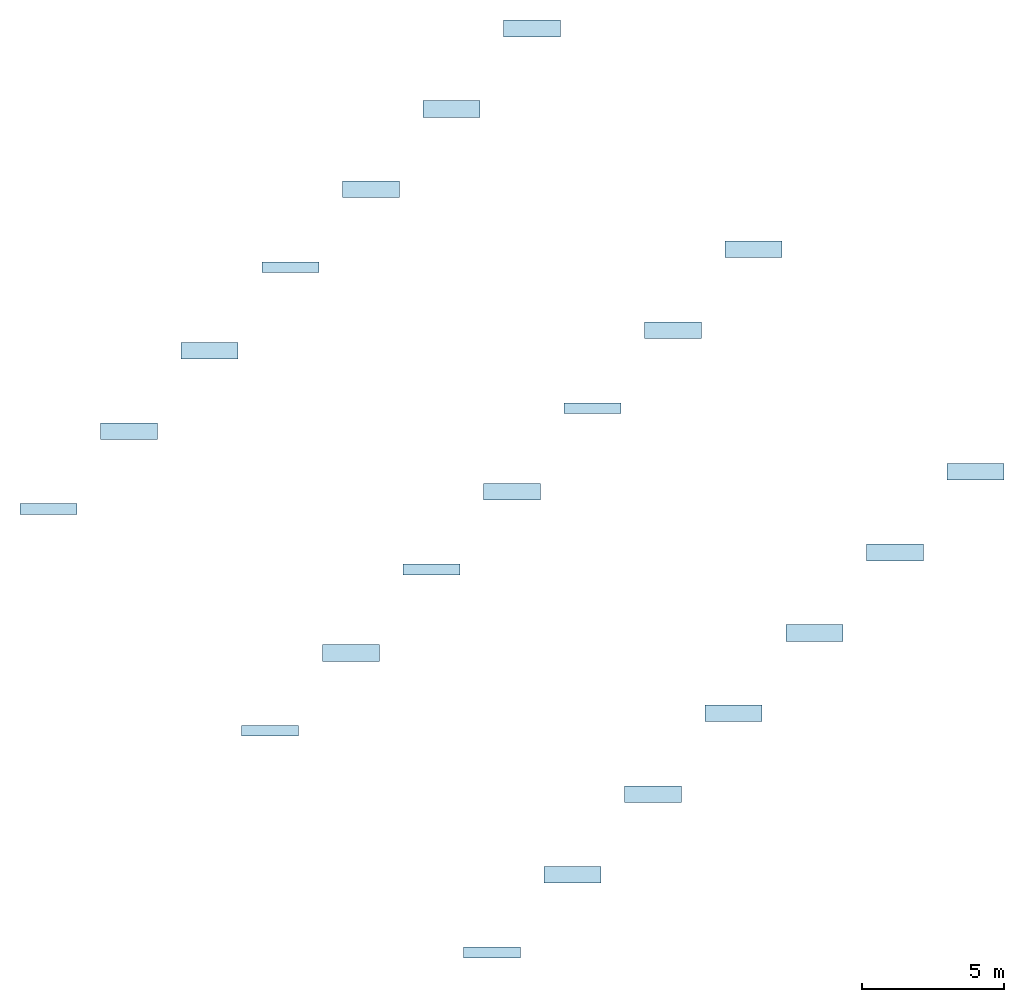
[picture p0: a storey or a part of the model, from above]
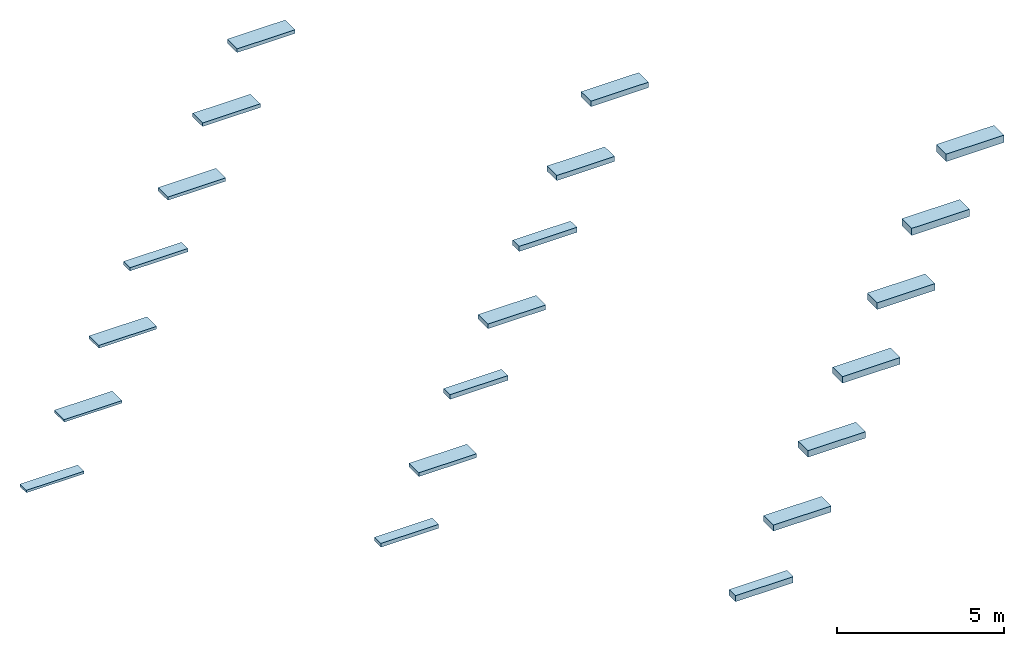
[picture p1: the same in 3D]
Properties of the parts of a building model (IFC2X3), part 1 of 3

# File
Description: ViewDefinition [CoordinationView]
Time: 2023-01-18T10:33:08
Written by: The EXPRESS Data Manager Version 5.02.0100.07 : 28 Aug 2013
Made in: 21.1.70.21 - Exporter 21.1.70.21 - Alternate UI 21.1.70.21
Comment: STEP Physical File produced by: The EXPRESS Data Manager Version 5.02.0100.07 : 28 Aug 2013 * Module: EDMstepFileFactory/EDMstandAlone * Creation date: Wed Jan 18 10:33:08 2023 * Host: BIM-LT03 * Database: C:\Users\DONNEE~1\AppData\Local\Temp\6dfd9f73-01cb-4fe2-bb7c-203e315a706e\b24bc6bb-a7e8-40af-8c49-64323bfd44da\ifc * Database version: 5507 * Database creation date: Wed Jan 18 10:33:06 2023 * Schema: IFC2X3 * Model: DataRepository.ifc * Model creation date: Wed Jan 18 10:33:06 2023 * Header model: DataRepository.ifc_HeaderModel * Header model creation date: Wed Jan 18 10:33:06 2023 * EDMuser: sdai-user * EDMgroup: sdai-group * License ID and type: 5605 : Permanent license. Expiry date: * EDMstepFileFactory options: 020000

# IfcSite, Default
RefLatitude: 42, 24, 53, 508911; RefLongitude: -71, -15, -29, -58837; RefElevation: 0 mm
Pset_ProductRequirements - Category: Project Information

# IfcBuilding
Pset_BuildingCommon - NumberOfStoreys: 2
Pset_ProductRequirements - Category: Project Information

# IfcBuildingStorey: Level:NL_00_niveau (2)
Pset_ProductRequirements - Category: Levels
Name | LongName = Pset_AirSideSystemInformation, Name = Pset_ProductRequirements, Name | Elevation (mm)
Begane grond | Begane grond | 0
Lengte | Lengte | 2500

# IfcRoof: Basic Roof:NLRS_27_RO_Naturoll 035_100x580x7400mm, Basic Roof:NLRS_27_RO_Naturoll 035_100x580x7400mm:35001
In: Lengte
Classification: 27 Daken (Uniformat)
Pset_ElementShading - Roughness: 304.8 mm
Pset_ManufacturerTypeInformation - Manufacturer: Knauf Insulation B.V.
Pset_ProductRequirements - Category: Roofs
Pset_QuantityTakeOff - Reference: Basic Roof:NLRS_27_RO_Naturoll 035_100x580x7400mm
Pset_RoofCommon - IsExternal: yes; Reference: Basic Roof:NLRS_27_RO_Naturoll 035_100x580x7400mm; ProjectedArea: 1.16 m2; TotalArea: 1.16 m2
Pset_Roof Schedule Naturoll 035 LOD400 - rollen / pak: 2; Type: Basic Roof: NLRS_27_RO_Naturoll 035_100x580x7400mm; Assembly Code: 27; Type Image: Raster image: Naturoll 035 .jpg (2); Model: Naturoll 035 is een onbeklede glaswoldeken met ECOSE® Technology; Manufacturer: Knauf Insulation B.V.; URL: www.knaufinsulation.nl; Description: Naturoll 035 - 100mm; phone: +31(0)162-421245; email: customerservice.nl@knaufinsulation.com; product URL: https://www.knaufinsulation.nl/producten-van-knauf-insulation/naturoll-035; warmteweerstand: 2.85; NLRS_C_Code_Brandklasse: A1; warmtegeleidingscoëfficiënt: 0.035; kortstondige waterabsorptie: WS; langdurige waterabsorptie: WL(P); waterdamptransmissie / waterdampdiffusie weerstandsfactor: MU1; luchtstroomweerstand: Afr5; DoP nummer (Declaration of performance): G4220LPCPR; NLRS_C_content_creator: Knauf Insulation; NLRS_C_content_versie: V1.0; diktebereik: 20 - 370; diktetolerantie: T2; pak (m2): 8.58; pakken / pallet: 24; pallet (m2): 206.02

# IfcRoof: Basic Roof:NLRS_27_RO_Naturoll 035_120x380x6200mm, Basic Roof:NLRS_27_RO_Naturoll 035_120x380x6200mm:35023
In: Lengte
Classification: 27 Daken (Uniformat)
Pset_ElementShading - Roughness: 304.8 mm
Pset_ManufacturerTypeInformation - Manufacturer: Knauf Insulation B.V.
Pset_ProductRequirements - Category: Roofs
Pset_QuantityTakeOff - Reference: Basic Roof:NLRS_27_RO_Naturoll 035_120x380x6200mm
Pset_RoofCommon - IsExternal: yes; Reference: Basic Roof:NLRS_27_RO_Naturoll 035_120x380x6200mm; ProjectedArea: 0.76 m2; TotalArea: 0.76 m2
Pset_Roof Schedule Naturoll 035 LOD400 - rollen / pak: 3; Type: Basic Roof: NLRS_27_RO_Naturoll 035_120x380x6200mm; Assembly Code: 27; Type Image: Raster image: Naturoll 035 .jpg (2); Model: Naturoll 035 is een onbeklede glaswoldeken met ECOSE® Technology; Manufacturer: Knauf Insulation B.V.; URL: www.knaufinsulation.nl; Description: Naturoll 035 - 120mm; phone: +31(0)162-421245; email: customerservice.nl@knaufinsulation.com; product URL: https://www.knaufinsulation.nl/producten-van-knauf-insulation/naturoll-035; warmteweerstand: 3.4; NLRS_C_Code_Brandklasse: A1; warmtegeleidingscoëfficiënt: 0.035; kortstondige waterabsorptie: WS; langdurige waterabsorptie: WL(P); waterdamptransmissie / waterdampdiffusie weerstandsfactor: MU1; luchtstroomweerstand: Afr5; DoP nummer (Declaration of performance): G4220LPCPR; NLRS_C_content_creator: Knauf Insulation; NLRS_C_content_versie: V1.0; diktebereik: 20 - 370; diktetolerantie: T2; pak (m2): 7.07; pakken / pallet: 24; pallet (m2): 169.63

# IfcRoof: Basic Roof:NLRS_27_RO_Naturoll 035_120x580x6200mm, Basic Roof:NLRS_27_RO_Naturoll 035_120x580x6200mm:35045
In: Lengte
Classification: 27 Daken (Uniformat)
Pset_ElementShading - Roughness: 304.8 mm
Pset_ManufacturerTypeInformation - Manufacturer: Knauf Insulation B.V.
Pset_ProductRequirements - Category: Roofs
Pset_QuantityTakeOff - Reference: Basic Roof:NLRS_27_RO_Naturoll 035_120x580x6200mm
Pset_RoofCommon - IsExternal: yes; Reference: Basic Roof:NLRS_27_RO_Naturoll 035_120x580x6200mm; ProjectedArea: 1.16 m2; TotalArea: 1.16 m2
Pset_Roof Schedule Naturoll 035 LOD400 - rollen / pak: 2; Type: Basic Roof: NLRS_27_RO_Naturoll 035_120x580x6200mm; Assembly Code: 27; Type Image: Raster image: Naturoll 035 .jpg (2); Model: Naturoll 035 is een onbeklede glaswoldeken met ECOSE® Technology; Manufacturer: Knauf Insulation B.V.; URL: www.knaufinsulation.nl; Description: Naturoll 035 - 120mm; phone: +31(0)162-421245; email: customerservice.nl@knaufinsulation.com; product URL: https://www.knaufinsulation.nl/producten-van-knauf-insulation/naturoll-035; warmteweerstand: 3.4; NLRS_C_Code_Brandklasse: A1; warmtegeleidingscoëfficiënt: 0.035; kortstondige waterabsorptie: WS; langdurige waterabsorptie: WL(P); waterdamptransmissie / waterdampdiffusie weerstandsfactor: MU1; luchtstroomweerstand: Afr5; DoP nummer (Declaration of performance): G4220LPCPR; NLRS_C_content_creator: Knauf Insulation; NLRS_C_content_versie: V1.0; diktebereik: 20 - 370; diktetolerantie: T2; pak (m2): 7.19; pakken / pallet: 24; pallet (m2): 172.61

# IfcRoof: Basic Roof:NLRS_27_RO_Naturoll 035_130x590x5500mm, Basic Roof:NLRS_27_RO_Naturoll 035_130x590x5500mm:35067
In: Lengte
Classification: 27 Daken (Uniformat)
Pset_ElementShading - Roughness: 304.8 mm
Pset_ManufacturerTypeInformation - Manufacturer: Knauf Insulation B.V.
Pset_ProductRequirements - Category: Roofs
Pset_QuantityTakeOff - Reference: Basic Roof:NLRS_27_RO_Naturoll 035_130x590x5500mm
Pset_RoofCommon - IsExternal: yes; Reference: Basic Roof:NLRS_27_RO_Naturoll 035_130x590x5500mm; ProjectedArea: 1.18 m2; TotalArea: 1.18 m2
Pset_Roof Schedule Naturoll 035 LOD400 - rollen / pak: 2; Type: Basic Roof: NLRS_27_RO_Naturoll 035_130x590x5500mm; Assembly Code: 27; Type Image: Raster image: Naturoll 035 .jpg (2); Model: Naturoll 035 is een onbeklede glaswoldeken met ECOSE® Technology; Manufacturer: Knauf Insulation B.V.; URL: www.knaufinsulation.nl; Description: Naturoll 035 - 130mm; phone: +31(0)162-421245; email: customerservice.nl@knaufinsulation.com; product URL: https://www.knaufinsulation.nl/producten-van-knauf-insulation/naturoll-035; warmteweerstand: 3.7; NLRS_C_Code_Brandklasse: A1; warmtegeleidingscoëfficiënt: 0.035; kortstondige waterabsorptie: WS; langdurige waterabsorptie: WL(P); waterdamptransmissie / waterdampdiffusie weerstandsfactor: MU1; luchtstroomweerstand: Afr5; DoP nummer (Declaration of performance): G4220LPCPR; NLRS_C_content_creator: Knauf Insulation; NLRS_C_content_versie: V1.0; diktebereik: 20 - 370; diktetolerantie: T2; pak (m2): 6.49; pakken / pallet: 24; pallet (m2): 155.76

# IfcRoof: Basic Roof:NLRS_27_RO_Naturoll 035_135x590x5300mm, Basic Roof:NLRS_27_RO_Naturoll 035_135x590x5300mm:42298
In: Lengte
Classification: 27 Daken (Uniformat)
Pset_ElementShading - Roughness: 304.8 mm
Pset_ManufacturerTypeInformation - Manufacturer: Knauf Insulation B.V.
Pset_ProductRequirements - Category: Roofs
Pset_QuantityTakeOff - Reference: Basic Roof:NLRS_27_RO_Naturoll 035_135x590x5300mm
Pset_RoofCommon - IsExternal: yes; Reference: Basic Roof:NLRS_27_RO_Naturoll 035_135x590x5300mm; ProjectedArea: 1.18 m2; TotalArea: 1.18 m2
Pset_Roof Schedule Naturoll 035 LOD400 - rollen / pak: 2; Type: Basic Roof: NLRS_27_RO_Naturoll 035_135x590x5300mm; Assembly Code: 27; Type Image: Raster image: Naturoll 035 .jpg (2); Model: Naturoll 035 is een onbeklede glaswoldeken met ECOSE® Technology; Manufacturer: Knauf Insulation B.V.; URL: www.knaufinsulation.nl; Description: Naturoll 035 - 135mm; phone: +31(0)162-421245; email: customerservice.nl@knaufinsulation.com; product URL: https://www.knaufinsulation.nl/producten-van-knauf-insulation/naturoll-035; warmteweerstand: 3.85; NLRS_C_Code_Brandklasse: A1; warmtegeleidingscoëfficiënt: 0.035; kortstondige waterabsorptie: WS; langdurige waterabsorptie: WL(P); waterdamptransmissie / waterdampdiffusie weerstandsfactor: MU1; luchtstroomweerstand: Afr5; DoP nummer (Declaration of performance): G4220LPCPR; NLRS_C_content_creator: Knauf Insulation; NLRS_C_content_versie: V1.0; diktebereik: 20 - 370; diktetolerantie: T2; pak (m2): 6.25; pakken / pallet: 24; pallet (m2): 150.1

# IfcRoof: Basic Roof:NLRS_27_RO_Naturoll 035_140x380x5300mm, Basic Roof:NLRS_27_RO_Naturoll 035_140x380x5300mm:35117
In: Lengte
Classification: 27 Daken (Uniformat)
Pset_ElementShading - Roughness: 304.8 mm
Pset_ManufacturerTypeInformation - Manufacturer: Knauf Insulation B.V.
Pset_ProductRequirements - Category: Roofs
Pset_QuantityTakeOff - Reference: Basic Roof:NLRS_27_RO_Naturoll 035_140x380x5300mm
Pset_RoofCommon - IsExternal: yes; Reference: Basic Roof:NLRS_27_RO_Naturoll 035_140x380x5300mm; ProjectedArea: 0.76 m2; TotalArea: 0.76 m2
Pset_Roof Schedule Naturoll 035 LOD400 - rollen / pak: 3; warmteweerstand: 4; Type: Basic Roof: NLRS_27_RO_Naturoll 035_140x380x5300mm; Assembly Code: 27; Type Image: Raster image: Naturoll 035 .jpg (2); Model: Naturoll 035 is een onbeklede glaswoldeken met ECOSE® Technology; Manufacturer: Knauf Insulation B.V.; URL: www.knaufinsulation.nl; Description: Naturoll 035 - 140mm; phone: +31(0)162-421245; email: customerservice.nl@knaufinsulation.com; product URL: https://www.knaufinsulation.nl/producten-van-knauf-insulation/naturoll-035; NLRS_C_Code_Brandklasse: A1; warmtegeleidingscoëfficiënt: 0.035; kortstondige waterabsorptie: WS; langdurige waterabsorptie: WL(P); waterdamptransmissie / waterdampdiffusie weerstandsfactor: MU1; luchtstroomweerstand: Afr5; DoP nummer (Declaration of performance): G4220LPCPR; NLRS_C_content_creator: Knauf Insulation; NLRS_C_content_versie: V1.0; diktebereik: 20 - 370; diktetolerantie: T2; pak (m2): 6.04; pakken / pallet: 24; pallet (m2): 145.01

# IfcRoof: Basic Roof:NLRS_27_RO_Naturoll 035_140x580x5300mm, Basic Roof:NLRS_27_RO_Naturoll 035_140x580x5300mm:35137
In: Lengte
Classification: 27 Daken (Uniformat)
Pset_ElementShading - Roughness: 304.8 mm
Pset_ManufacturerTypeInformation - Manufacturer: Knauf Insulation B.V.
Pset_ProductRequirements - Category: Roofs
Pset_QuantityTakeOff - Reference: Basic Roof:NLRS_27_RO_Naturoll 035_140x580x5300mm
Pset_RoofCommon - IsExternal: yes; Reference: Basic Roof:NLRS_27_RO_Naturoll 035_140x580x5300mm; ProjectedArea: 1.16 m2; TotalArea: 1.16 m2
Pset_Roof Schedule Naturoll 035 LOD400 - rollen / pak: 2; warmteweerstand: 4; Type: Basic Roof: NLRS_27_RO_Naturoll 035_140x580x5300mm; Assembly Code: 27; Type Image: Raster image: Naturoll 035 .jpg (2); Model: Naturoll 035 is een onbeklede glaswoldeken met ECOSE® Technology; Manufacturer: Knauf Insulation B.V.; URL: www.knaufinsulation.nl; Description: Naturoll 035 - 140mm; phone: +31(0)162-421245; email: customerservice.nl@knaufinsulation.com; product URL: https://www.knaufinsulation.nl/producten-van-knauf-insulation/naturoll-035; NLRS_C_Code_Brandklasse: A1; warmtegeleidingscoëfficiënt: 0.035; kortstondige waterabsorptie: WS; langdurige waterabsorptie: WL(P); waterdamptransmissie / waterdampdiffusie weerstandsfactor: MU1; luchtstroomweerstand: Afr5; DoP nummer (Declaration of performance): G4220LPCPR; NLRS_C_content_creator: Knauf Insulation; NLRS_C_content_versie: V1.0; diktebereik: 20 - 370; diktetolerantie: T2; pak (m2): 6.15; pakken / pallet: 24; pallet (m2): 147.55

# IfcRoof: Basic Roof:NLRS_27_RO_Naturoll 035_170x380x4350mm, Basic Roof:NLRS_27_RO_Naturoll 035_170x380x4350mm:35177
In: Lengte
Classification: 27 Daken (Uniformat)
Pset_ElementShading - Roughness: 304.8 mm
Pset_ManufacturerTypeInformation - Manufacturer: Knauf Insulation B.V.
Pset_ProductRequirements - Category: Roofs
Pset_QuantityTakeOff - Reference: Basic Roof:NLRS_27_RO_Naturoll 035_170x380x4350mm
Pset_RoofCommon - IsExternal: yes; Reference: Basic Roof:NLRS_27_RO_Naturoll 035_170x380x4350mm; ProjectedArea: 0.76 m2; TotalArea: 0.76 m2
Pset_Roof Schedule Naturoll 035 LOD400 - rollen / pak: 3; Type: Basic Roof: NLRS_27_RO_Naturoll 035_170x380x4350mm; Assembly Code: 27; Type Image: Raster image: Naturoll 035 .jpg (2); Model: Naturoll 035 is een onbeklede glaswoldeken met ECOSE® Technology; Manufacturer: Knauf Insulation B.V.; URL: www.knaufinsulation.nl; Description: Naturoll 035 - 170mm; phone: +31(0)162-421245; email: customerservice.nl@knaufinsulation.com; product URL: https://www.knaufinsulation.nl/producten-van-knauf-insulation/naturoll-035; warmteweerstand: 4.85; NLRS_C_Code_Brandklasse: A1; warmtegeleidingscoëfficiënt: 0.035; kortstondige waterabsorptie: WS; langdurige waterabsorptie: WL(P); waterdamptransmissie / waterdampdiffusie weerstandsfactor: MU1; luchtstroomweerstand: Afr5; DoP nummer (Declaration of performance): G4220LPCPR; NLRS_C_content_creator: Knauf Insulation; NLRS_C_content_versie: V1.0; diktebereik: 20 - 370; diktetolerantie: T2; pak (m2): 4.96; pakken / pallet: 24; pallet (m2): 119.02

# IfcRoof: Basic Roof:NLRS_27_RO_Naturoll 035_170x580x4350mm, Basic Roof:NLRS_27_RO_Naturoll 035_170x580x4350mm:35197
In: Lengte
Classification: 27 Daken (Uniformat)
Pset_ElementShading - Roughness: 304.8 mm
Pset_ManufacturerTypeInformation - Manufacturer: Knauf Insulation B.V.
Pset_ProductRequirements - Category: Roofs
Pset_QuantityTakeOff - Reference: Basic Roof:NLRS_27_RO_Naturoll 035_170x580x4350mm
Pset_RoofCommon - IsExternal: yes; Reference: Basic Roof:NLRS_27_RO_Naturoll 035_170x580x4350mm; ProjectedArea: 1.16 m2; TotalArea: 1.16 m2
Pset_Roof Schedule Naturoll 035 LOD400 - rollen / pak: 2; Type: Basic Roof: NLRS_27_RO_Naturoll 035_170x580x4350mm; Assembly Code: 27; Type Image: Raster image: Naturoll 035 .jpg (2); Model: Naturoll 035 is een onbeklede glaswoldeken met ECOSE® Technology; Manufacturer: Knauf Insulation B.V.; URL: www.knaufinsulation.nl; Description: Naturoll 035 - 170mm; phone: +31(0)162-421245; email: customerservice.nl@knaufinsulation.com; product URL: https://www.knaufinsulation.nl/producten-van-knauf-insulation/naturoll-035; warmteweerstand: 4.85; NLRS_C_Code_Brandklasse: A1; warmtegeleidingscoëfficiënt: 0.035; kortstondige waterabsorptie: WS; langdurige waterabsorptie: WL(P); waterdamptransmissie / waterdampdiffusie weerstandsfactor: MU1; luchtstroomweerstand: Afr5; DoP nummer (Declaration of performance): G4220LPCPR; NLRS_C_content_creator: Knauf Insulation; NLRS_C_content_versie: V1.0; diktebereik: 20 - 370; diktetolerantie: T2; pak (m2): 5.05; pakken / pallet: 24; pallet (m2): 121.1

# IfcRoof: Basic Roof:NLRS_27_RO_Naturoll 035_185x380x4000mm, Basic Roof:NLRS_27_RO_Naturoll 035_185x380x4000mm:35217
In: Lengte
Classification: 27 Daken (Uniformat)
Pset_ElementShading - Roughness: 304.8 mm
Pset_ManufacturerTypeInformation - Manufacturer: Knauf Insulation B.V.
Pset_ProductRequirements - Category: Roofs
Pset_QuantityTakeOff - Reference: Basic Roof:NLRS_27_RO_Naturoll 035_185x380x4000mm
Pset_RoofCommon - IsExternal: yes; Reference: Basic Roof:NLRS_27_RO_Naturoll 035_185x380x4000mm; ProjectedArea: 0.76 m2; TotalArea: 0.76 m2
Pset_Roof Schedule Naturoll 035 LOD400 - rollen / pak: 3; Type: Basic Roof: NLRS_27_RO_Naturoll 035_185x380x4000mm; Assembly Code: 27; Type Image: Raster image: Naturoll 035 .jpg (2); Model: Naturoll 035 is een onbeklede glaswoldeken met ECOSE® Technology; Manufacturer: Knauf Insulation B.V.; URL: www.knaufinsulation.nl; Description: Naturoll 035 - 185mm; phone: +31(0)162-421245; email: customerservice.nl@knaufinsulation.com; product URL: https://www.knaufinsulation.nl/producten-van-knauf-insulation/naturoll-035; warmteweerstand: 5.25; NLRS_C_Code_Brandklasse: A1; warmtegeleidingscoëfficiënt: 0.035; kortstondige waterabsorptie: WS; langdurige waterabsorptie: WL(P); waterdamptransmissie / waterdampdiffusie weerstandsfactor: MU1; luchtstroomweerstand: Afr5; DoP nummer (Declaration of performance): G4220LPCPR; NLRS_C_content_creator: Knauf Insulation; NLRS_C_content_versie: V1.0; diktebereik: 20 - 370; diktetolerantie: T2; pak (m2): 4.56; pakken / pallet: 24; pallet (m2): 109.44

# IfcRoof: Basic Roof:NLRS_27_RO_Naturoll 035_185x580x4000mm, Basic Roof:NLRS_27_RO_Naturoll 035_185x580x4000mm:37505
In: Lengte
Classification: 27 Daken (Uniformat)
Pset_ElementShading - Roughness: 304.8 mm
Pset_ManufacturerTypeInformation - Manufacturer: Knauf Insulation B.V.
Pset_ProductRequirements - Category: Roofs
Pset_QuantityTakeOff - Reference: Basic Roof:NLRS_27_RO_Naturoll 035_185x580x4000mm
Pset_RoofCommon - IsExternal: yes; Reference: Basic Roof:NLRS_27_RO_Naturoll 035_185x580x4000mm; ProjectedArea: 1.16 m2; TotalArea: 1.16 m2
Pset_Roof Schedule Naturoll 035 LOD400 - rollen / pak: 2; Type: Basic Roof: NLRS_27_RO_Naturoll 035_185x580x4000mm; Assembly Code: 27; Type Image: Raster image: Naturoll 035 .jpg (2); Model: Naturoll 035 is een onbeklede glaswoldeken met ECOSE® Technology; Manufacturer: Knauf Insulation B.V.; URL: www.knaufinsulation.nl; Description: Naturoll 035 - 185mm; phone: +31(0)162-421245; email: customerservice.nl@knaufinsulation.com; product URL: https://www.knaufinsulation.nl/producten-van-knauf-insulation/naturoll-035; warmteweerstand: 5.25; NLRS_C_Code_Brandklasse: A1; warmtegeleidingscoëfficiënt: 0.035; kortstondige waterabsorptie: WS; langdurige waterabsorptie: WL(P); waterdamptransmissie / waterdampdiffusie weerstandsfactor: MU1; luchtstroomweerstand: Afr5; DoP nummer (Declaration of performance): G4220LPCPR; NLRS_C_content_creator: Knauf Insulation; NLRS_C_content_versie: V1.0; diktebereik: 20 - 370; diktetolerantie: T2; pak (m2): 4.64; pakken / pallet: 24; pallet (m2): 111.36

# IfcRoof: Basic Roof:NLRS_27_RO_Naturoll 035_200x580x3700mm, Basic Roof:NLRS_27_RO_Naturoll 035_200x580x3700mm:35405
In: Lengte
Classification: 27 Daken (Uniformat)
Pset_ElementShading - Roughness: 304.8 mm
Pset_ManufacturerTypeInformation - Manufacturer: Knauf Insulation B.V.
Pset_ProductRequirements - Category: Roofs
Pset_QuantityTakeOff - Reference: Basic Roof:NLRS_27_RO_Naturoll 035_200x580x3700mm
Pset_RoofCommon - IsExternal: yes; Reference: Basic Roof:NLRS_27_RO_Naturoll 035_200x580x3700mm; ProjectedArea: 1.16 m2; TotalArea: 1.16 m2
Pset_Roof Schedule Naturoll 035 LOD400 - rollen / pak: 2; Type: Basic Roof: NLRS_27_RO_Naturoll 035_200x580x3700mm; Assembly Code: 27; Type Image: Raster image: Naturoll 035 .jpg (2); Model: Naturoll 035 is een onbeklede glaswoldeken met ECOSE® Technology; Manufacturer: Knauf Insulation B.V.; URL: www.knaufinsulation.nl; Description: Naturoll 035 - 200mm; phone: +31(0)162-421245; email: customerservice.nl@knaufinsulation.com; product URL: https://www.knaufinsulation.nl/producten-van-knauf-insulation/naturoll-035; warmteweerstand: 5.7; NLRS_C_Code_Brandklasse: A1; warmtegeleidingscoëfficiënt: 0.035; kortstondige waterabsorptie: WS; langdurige waterabsorptie: WL(P); waterdamptransmissie / waterdampdiffusie weerstandsfactor: MU1; luchtstroomweerstand: Afr5; DoP nummer (Declaration of performance): G4220LPCPR; NLRS_C_content_creator: Knauf Insulation; NLRS_C_content_versie: V1.0; diktebereik: 20 - 370; diktetolerantie: T2; pak (m2): 4.29; pakken / pallet: 24; pallet (m2): 103.01

# IfcRoof: Basic Roof:NLRS_27_RO_Naturoll 035_220x380x3400mm, Basic Roof:NLRS_27_RO_Naturoll 035_220x380x3400mm:35424
In: Lengte
Classification: 27 Daken (Uniformat)
Pset_ElementShading - Roughness: 304.8 mm
Pset_ManufacturerTypeInformation - Manufacturer: Knauf Insulation B.V.
Pset_ProductRequirements - Category: Roofs
Pset_QuantityTakeOff - Reference: Basic Roof:NLRS_27_RO_Naturoll 035_220x380x3400mm
Pset_RoofCommon - IsExternal: yes; Reference: Basic Roof:NLRS_27_RO_Naturoll 035_220x380x3400mm; ProjectedArea: 0.76 m2; TotalArea: 0.76 m2
Pset_Roof Schedule Naturoll 035 LOD400 - rollen / pak: 3; Type: Basic Roof: NLRS_27_RO_Naturoll 035_220x380x3400mm; Assembly Code: 27; Type Image: Raster image: Naturoll 035 .jpg (2); Model: Naturoll 035 is een onbeklede glaswoldeken met ECOSE® Technology; Manufacturer: Knauf Insulation B.V.; URL: www.knaufinsulation.nl; Description: Naturoll 035 - 220mm; phone: +31(0)162-421245; email: customerservice.nl@knaufinsulation.com; product URL: https://www.knaufinsulation.nl/producten-van-knauf-insulation/naturoll-035; warmteweerstand: 6.25; NLRS_C_Code_Brandklasse: A1; warmtegeleidingscoëfficiënt: 0.035; kortstondige waterabsorptie: WS; langdurige waterabsorptie: WL(P); waterdamptransmissie / waterdampdiffusie weerstandsfactor: MU1; luchtstroomweerstand: Afr5; DoP nummer (Declaration of performance): G4220LPCPR; NLRS_C_content_creator: Knauf Insulation; NLRS_C_content_versie: V1.0; diktebereik: 20 - 370; diktetolerantie: T2; pak (m2): 3.88; pakken / pallet: 24; pallet (m2): 93.02

# IfcRoof: Basic Roof:NLRS_27_RO_Naturoll 035_220x580x3400mm, Basic Roof:NLRS_27_RO_Naturoll 035_220x580x3400mm:35443
In: Lengte
Classification: 27 Daken (Uniformat)
Pset_ElementShading - Roughness: 304.8 mm
Pset_ManufacturerTypeInformation - Manufacturer: Knauf Insulation B.V.
Pset_ProductRequirements - Category: Roofs
Pset_QuantityTakeOff - Reference: Basic Roof:NLRS_27_RO_Naturoll 035_220x580x3400mm
Pset_RoofCommon - IsExternal: yes; Reference: Basic Roof:NLRS_27_RO_Naturoll 035_220x580x3400mm; ProjectedArea: 1.16 m2; TotalArea: 1.16 m2
Pset_Roof Schedule Naturoll 035 LOD400 - rollen / pak: 2; Type: Basic Roof: NLRS_27_RO_Naturoll 035_220x580x3400mm; Assembly Code: 27; Type Image: Raster image: Naturoll 035 .jpg (2); Model: Naturoll 035 is een onbeklede glaswoldeken met ECOSE® Technology; Manufacturer: Knauf Insulation B.V.; URL: www.knaufinsulation.nl; Description: Naturoll 035 - 220mm; phone: +31(0)162-421245; email: customerservice.nl@knaufinsulation.com; product URL: https://www.knaufinsulation.nl/producten-van-knauf-insulation/naturoll-035; warmteweerstand: 6.25; NLRS_C_Code_Brandklasse: A1; warmtegeleidingscoëfficiënt: 0.035; kortstondige waterabsorptie: WS; langdurige waterabsorptie: WL(P); waterdamptransmissie / waterdampdiffusie weerstandsfactor: MU1; luchtstroomweerstand: Afr5; DoP nummer (Declaration of performance): G4220LPCPR; NLRS_C_content_creator: Knauf Insulation; NLRS_C_content_versie: V1.0; diktebereik: 20 - 370; diktetolerantie: T2; pak (m2): 3.94; pakken / pallet: 24; pallet (m2): 94.66

# IfcRoof: Basic Roof:NLRS_27_RO_Naturoll 035_235x580x3100mm, Basic Roof:NLRS_27_RO_Naturoll 035_235x580x3100mm:35462
In: Lengte
Classification: 27 Daken (Uniformat)
Pset_ElementShading - Roughness: 304.8 mm
Pset_ManufacturerTypeInformation - Manufacturer: Knauf Insulation B.V.
Pset_ProductRequirements - Category: Roofs
Pset_QuantityTakeOff - Reference: Basic Roof:NLRS_27_RO_Naturoll 035_235x580x3100mm
Pset_RoofCommon - IsExternal: yes; Reference: Basic Roof:NLRS_27_RO_Naturoll 035_235x580x3100mm; ProjectedArea: 1.16 m2; TotalArea: 1.16 m2
Pset_Roof Schedule Naturoll 035 LOD400 - rollen / pak: 2; Type: Basic Roof: NLRS_27_RO_Naturoll 035_235x580x3100mm; Assembly Code: 27; Type Image: Raster image: Naturoll 035 .jpg (2); Model: Naturoll 035 is een onbeklede glaswoldeken met ECOSE® Technology; Manufacturer: Knauf Insulation B.V.; URL: www.knaufinsulation.nl; Description: Naturoll 035 - 235mm; phone: +31(0)162-421245; email: customerservice.nl@knaufinsulation.com; product URL: https://www.knaufinsulation.nl/producten-van-knauf-insulation/naturoll-035; warmteweerstand: 6.7; NLRS_C_Code_Brandklasse: A1; warmtegeleidingscoëfficiënt: 0.035; kortstondige waterabsorptie: WS; langdurige waterabsorptie: WL(P); waterdamptransmissie / waterdampdiffusie weerstandsfactor: MU1; luchtstroomweerstand: Afr5; DoP nummer (Declaration of performance): G4220LPCPR; NLRS_C_content_creator: Knauf Insulation; NLRS_C_content_versie: V1.0; diktebereik: 20 - 370; diktetolerantie: T2; pak (m2): 3.6; pakken / pallet: 24; pallet (m2): 86.3

# IfcRoof: Basic Roof:NLRS_27_RO_Naturoll 035_240x580x3100mm, Basic Roof:NLRS_27_RO_Naturoll 035_240x580x3100mm:35481
In: Lengte
Classification: 27 Daken (Uniformat)
Pset_ElementShading - Roughness: 304.8 mm
Pset_ManufacturerTypeInformation - Manufacturer: Knauf Insulation B.V.
Pset_ProductRequirements - Category: Roofs
Pset_QuantityTakeOff - Reference: Basic Roof:NLRS_27_RO_Naturoll 035_240x580x3100mm
Pset_RoofCommon - IsExternal: yes; Reference: Basic Roof:NLRS_27_RO_Naturoll 035_240x580x3100mm; ProjectedArea: 1.16 m2; TotalArea: 1.16 m2
Pset_Roof Schedule Naturoll 035 LOD400 - rollen / pak: 2; Type: Basic Roof: NLRS_27_RO_Naturoll 035_240x580x3100mm; Assembly Code: 27; Type Image: Raster image: Naturoll 035 .jpg (2); Model: Naturoll 035 is een onbeklede glaswoldeken met ECOSE® Technology; Manufacturer: Knauf Insulation B.V.; URL: www.knaufinsulation.nl; Description: Naturoll 035 - 240mm; phone: +31(0)162-421245; email: customerservice.nl@knaufinsulation.com; product URL: https://www.knaufinsulation.nl/producten-van-knauf-insulation/naturoll-035; warmteweerstand: 6.85; NLRS_C_Code_Brandklasse: A1; warmtegeleidingscoëfficiënt: 0.035; kortstondige waterabsorptie: WS; langdurige waterabsorptie: WL(P); waterdamptransmissie / waterdampdiffusie weerstandsfactor: MU1; luchtstroomweerstand: Afr5; DoP nummer (Declaration of performance): G4220LPCPR; NLRS_C_content_creator: Knauf Insulation; NLRS_C_content_versie: V1.0; diktebereik: 20 - 370; diktetolerantie: T2; pak (m2): 3.6; pakken / pallet: 24; pallet (m2): 86.3

# IfcRoof: Basic Roof:NLRS_27_RO_Naturoll 035_245x590x2600mm, Basic Roof:NLRS_27_RO_Naturoll 035_245x590x2600mm:42674
In: Lengte
Classification: 27 Daken (Uniformat)
Pset_ElementShading - Roughness: 304.8 mm
Pset_ManufacturerTypeInformation - Manufacturer: Knauf Insulation B.V.
Pset_ProductRequirements - Category: Roofs
Pset_QuantityTakeOff - Reference: Basic Roof:NLRS_27_RO_Naturoll 035_245x590x2600mm
Pset_RoofCommon - IsExternal: yes; Reference: Basic Roof:NLRS_27_RO_Naturoll 035_245x590x2600mm; ProjectedArea: 1.18 m2; TotalArea: 1.18 m2
Pset_Roof Schedule Naturoll 035 LOD400 - rollen / pak: 2; warmteweerstand: 7; Type: Basic Roof: NLRS_27_RO_Naturoll 035_245x590x2600mm; Assembly Code: 27; Type Image: Raster image: Naturoll 035 .jpg (2); Model: Naturoll 035 is een onbeklede glaswoldeken met ECOSE® Technology; Manufacturer: Knauf Insulation B.V.; URL: www.knaufinsulation.nl; Description: Naturoll 035 - 245mm; phone: +31(0)162-421245; email: customerservice.nl@knaufinsulation.com; product URL: https://www.knaufinsulation.nl/producten-van-knauf-insulation/naturoll-035; NLRS_C_Code_Brandklasse: A1; warmtegeleidingscoëfficiënt: 0.035; kortstondige waterabsorptie: WS; langdurige waterabsorptie: WL(P); waterdamptransmissie / waterdampdiffusie weerstandsfactor: MU1; luchtstroomweerstand: Afr5; DoP nummer (Declaration of performance): G4220LPCPR; NLRS_C_content_creator: Knauf Insulation; NLRS_C_content_versie: V1.0; diktebereik: 20 - 370; diktetolerantie: T2; pak (m2): 3.07; pakken / pallet: 24; pallet (m2): 73.63

# IfcRoof: Basic Roof:NLRS_27_RO_Naturoll 035_260x590x2700mm, Basic Roof:NLRS_27_RO_Naturoll 035_260x590x2700mm:42613
In: Lengte
Classification: 27 Daken (Uniformat)
Pset_ElementShading - Roughness: 304.8 mm
Pset_ManufacturerTypeInformation - Manufacturer: Knauf Insulation B.V.
Pset_ProductRequirements - Category: Roofs
Pset_QuantityTakeOff - Reference: Basic Roof:NLRS_27_RO_Naturoll 035_260x590x2700mm
Pset_RoofCommon - IsExternal: yes; Reference: Basic Roof:NLRS_27_RO_Naturoll 035_260x590x2700mm; ProjectedArea: 1.18 m2; TotalArea: 1.18 m2
Pset_Roof Schedule Naturoll 035 LOD400 - rollen / pak: 2; Type: Basic Roof: NLRS_27_RO_Naturoll 035_260x590x2700mm; Assembly Code: 27; Type Image: Raster image: Naturoll 035 .jpg (2); Model: Naturoll 035 is een onbeklede glaswoldeken met ECOSE® Technology; Manufacturer: Knauf Insulation B.V.; URL: www.knaufinsulation.nl; Description: Naturoll 035 - 260mm; phone: +31(0)162-421245; email: customerservice.nl@knaufinsulation.com; product URL: https://www.knaufinsulation.nl/producten-van-knauf-insulation/naturoll-035; warmteweerstand: 7.4; NLRS_C_Code_Brandklasse: A1; warmtegeleidingscoëfficiënt: 0.035; kortstondige waterabsorptie: WS; langdurige waterabsorptie: WL(P); waterdamptransmissie / waterdampdiffusie weerstandsfactor: MU1; luchtstroomweerstand: Afr5; DoP nummer (Declaration of performance): G4220LPCPR; NLRS_C_content_creator: Knauf Insulation; NLRS_C_content_versie: V1.0; diktebereik: 20 - 370; diktetolerantie: T2; pak (m2): 3.19; pakken / pallet: 24; pallet (m2): 76.05

# IfcRoof: Basic Roof:NLRS_27_RO_Naturoll 035_270x590x2600mm, Basic Roof:NLRS_27_RO_Naturoll 035_270x590x2600mm:35500
In: Lengte
Classification: 27 Daken (Uniformat)
Pset_ElementShading - Roughness: 304.8 mm
Pset_ManufacturerTypeInformation - Manufacturer: Knauf Insulation B.V.
Pset_ProductRequirements - Category: Roofs
Pset_QuantityTakeOff - Reference: Basic Roof:NLRS_27_RO_Naturoll 035_270x590x2600mm
Pset_RoofCommon - IsExternal: yes; Reference: Basic Roof:NLRS_27_RO_Naturoll 035_270x590x2600mm; ProjectedArea: 1.18 m2; TotalArea: 1.18 m2
Pset_Roof Schedule Naturoll 035 LOD400 - rollen / pak: 2; Type: Basic Roof: NLRS_27_RO_Naturoll 035_270x590x2600mm; Assembly Code: 27; Type Image: Raster image: Naturoll 035 .jpg (2); Model: Naturoll 035 is een onbeklede glaswoldeken met ECOSE® Technology; Manufacturer: Knauf Insulation B.V.; URL: www.knaufinsulation.nl; Description: Naturoll 035 - 270mm; phone: +31(0)162-421245; email: customerservice.nl@knaufinsulation.com; product URL: https://www.knaufinsulation.nl/producten-van-knauf-insulation/naturoll-035; warmteweerstand: 7.7; NLRS_C_Code_Brandklasse: A1; warmtegeleidingscoëfficiënt: 0.035; kortstondige waterabsorptie: WS; langdurige waterabsorptie: WL(P); waterdamptransmissie / waterdampdiffusie weerstandsfactor: MU1; luchtstroomweerstand: Afr5; DoP nummer (Declaration of performance): G4220LPCPR; NLRS_C_content_creator: Knauf Insulation; NLRS_C_content_versie: V1.0; diktebereik: 20 - 370; diktetolerantie: T2; pak (m2): 3.07; pakken / pallet: 24; pallet (m2): 73.63

# IfcRoof: Basic Roof:NLRS_27_RO_Naturoll 035_90x380x7600mm, Basic Roof:NLRS_27_RO_Naturoll 035_90x380x7600mm:34727
In: Lengte
Classification: 27 Daken (Uniformat)
Pset_ElementShading - Roughness: 304.8 mm
Pset_ManufacturerTypeInformation - Manufacturer: Knauf Insulation B.V.
Pset_ProductRequirements - Category: Roofs
Pset_QuantityTakeOff - Reference: Basic Roof:NLRS_27_RO_Naturoll 035_90x380x7600mm
Pset_RoofCommon - IsExternal: yes; Reference: Basic Roof:NLRS_27_RO_Naturoll 035_90x380x7600mm; ProjectedArea: 0.76 m2; TotalArea: 0.76 m2
Pset_Roof Schedule Naturoll 035 LOD400 - rollen / pak: 3; Type: Basic Roof: NLRS_27_RO_Naturoll 035_90x380x7600mm; Assembly Code: 27; Type Image: Raster image: Naturoll 035 .jpg (2); Model: Naturoll 035 is een onbeklede glaswoldeken met ECOSE® Technology; Manufacturer: Knauf Insulation B.V.; URL: www.knaufinsulation.nl; Description: Naturoll 035 - 90mm; phone: +31(0)162-421245; email: customerservice.nl@knaufinsulation.com; product URL: https://www.knaufinsulation.nl/producten-van-knauf-insulation/naturoll-035; warmteweerstand: 2.55; NLRS_C_Code_Brandklasse: A1; warmtegeleidingscoëfficiënt: 0.035; kortstondige waterabsorptie: WS; langdurige waterabsorptie: WL(P); waterdamptransmissie / waterdampdiffusie weerstandsfactor: MU1; luchtstroomweerstand: Afr5; DoP nummer (Declaration of performance): G4220LPCPR; NLRS_C_content_creator: Knauf Insulation; NLRS_C_content_versie: V1.0; diktebereik: 20 - 370; diktetolerantie: T2; pak (m2): 8.66; pakken / pallet: 24; pallet (m2): 207.94

# IfcRoof: Basic Roof:NLRS_27_RO_Naturoll 035_90x580x7600mm, Basic Roof:NLRS_27_RO_Naturoll 035_90x580x7600mm:34921
In: Lengte
Classification: 27 Daken (Uniformat)
Pset_ElementShading - Roughness: 304.8 mm
Pset_ManufacturerTypeInformation - Manufacturer: Knauf Insulation B.V.
Pset_ProductRequirements - Category: Roofs
Pset_QuantityTakeOff - Reference: Basic Roof:NLRS_27_RO_Naturoll 035_90x580x7600mm
Pset_RoofCommon - IsExternal: yes; Reference: Basic Roof:NLRS_27_RO_Naturoll 035_90x580x7600mm; ProjectedArea: 1.16 m2; TotalArea: 1.16 m2
Pset_Roof Schedule Naturoll 035 LOD400 - rollen / pak: 2; Type: Basic Roof: NLRS_27_RO_Naturoll 035_90x580x7600mm; Assembly Code: 27; Type Image: Raster image: Naturoll 035 .jpg (2); Model: Naturoll 035 is een onbeklede glaswoldeken met ECOSE® Technology; Manufacturer: Knauf Insulation B.V.; URL: www.knaufinsulation.nl; Description: Naturoll 035 - 90mm; phone: +31(0)162-421245; email: customerservice.nl@knaufinsulation.com; product URL: https://www.knaufinsulation.nl/producten-van-knauf-insulation/naturoll-035; warmteweerstand: 2.55; NLRS_C_Code_Brandklasse: A1; warmtegeleidingscoëfficiënt: 0.035; kortstondige waterabsorptie: WS; langdurige waterabsorptie: WL(P); waterdamptransmissie / waterdampdiffusie weerstandsfactor: MU1; luchtstroomweerstand: Afr5; DoP nummer (Declaration of performance): G4220LPCPR; NLRS_C_content_creator: Knauf Insulation; NLRS_C_content_versie: V1.0; diktebereik: 20 - 370; diktetolerantie: T2; pak (m2): 8.82; pakken / pallet: 24; pallet (m2): 211.58

# IfcSlab: Basic Roof:NLRS_27_RO_Naturoll 035_100x580x7400mm, Basic Roof:NLRS_27_RO_Naturoll 035_100x580x7400mm:35001
In: Lengte
Type - PredefinedType: ROOF
Type - Pset_ElementShading - Roughness: 304.8 mm
Type - Pset_ManufacturerTypeInformation - Manufacturer: Knauf Insulation B.V.
Type - Pset_ProductRequirements - Category: Roofs
Type - Pset_QuantityTakeOff - Reference: Basic Roof:NLRS_27_RO_Naturoll 035_100x580x7400mm
Type - Pset_ReinforcementBarPitchOfSlab - Description: Naturoll 035 - 100mm; Reference: Basic Roof:NLRS_27_RO_Naturoll 035_100x580x7400mm
Type - Pset_SlabCommon - IsExternal: yes; ThermalTransmittance: 0.35 kg/K/s3; Reference: Basic Roof:NLRS_27_RO_Naturoll 035_100x580x7400mm
Type - Pset_Roof Schedule Naturoll 035 LOD400 - rollen / pak: 2; Assembly Code: 27; Type Image: Raster image: Naturoll 035 .jpg (2); Model: Naturoll 035 is een onbeklede glaswoldeken met ECOSE® Technology; Manufacturer: Knauf Insulation B.V.; URL: www.knaufinsulation.nl; Description: Naturoll 035 - 100mm; phone: +31(0)162-421245; email: customerservice.nl@knaufinsulation.com; product URL: https://www.knaufinsulation.nl/producten-van-knauf-insulation/naturoll-035; warmteweerstand: 2.85; NLRS_C_Code_Brandklasse: A1; warmtegeleidingscoëfficiënt: 0.035; kortstondige waterabsorptie: WS; langdurige waterabsorptie: WL(P); waterdamptransmissie / waterdampdiffusie weerstandsfactor: MU1; luchtstroomweerstand: Afr5; DoP nummer (Declaration of performance): G4220LPCPR; NLRS_C_content_creator: Knauf Insulation; NLRS_C_content_versie: V1.0; diktebereik: 20 - 370; diktetolerantie: T2; pak (m2): 8.58; pakken / pallet: 24; pallet (m2): 206.02
Classification: 27 Daken (Uniformat); Material: Knauf Insulation_Ecose® glaswol_naturoll 035; Knauf Insulation_Ecose® glaswol_naturoll 035 100 mm
Pset_SlabCommon - PitchAngle: 0 deg
Pset_Roof Schedule Naturoll 035 LOD400 - Type: Basic Roof: NLRS_27_RO_Naturoll 035_100x580x7400mm

# IfcSlab: Basic Roof:NLRS_27_RO_Naturoll 035_120x380x6200mm, Basic Roof:NLRS_27_RO_Naturoll 035_120x380x6200mm:35023
In: Lengte
Type - PredefinedType: ROOF
Type - Pset_ElementShading - Roughness: 304.8 mm
Type - Pset_ManufacturerTypeInformation - Manufacturer: Knauf Insulation B.V.
Type - Pset_ProductRequirements - Category: Roofs
Type - Pset_QuantityTakeOff - Reference: Basic Roof:NLRS_27_RO_Naturoll 035_120x380x6200mm
Type - Pset_ReinforcementBarPitchOfSlab - Description: Naturoll 035 - 120mm; Reference: Basic Roof:NLRS_27_RO_Naturoll 035_120x380x6200mm
Type - Pset_SlabCommon - IsExternal: yes; Reference: Basic Roof:NLRS_27_RO_Naturoll 035_120x380x6200mm; ThermalTransmittance: 0.291667 kg/K/s3
Type - Pset_Roof Schedule Naturoll 035 LOD400 - rollen / pak: 3; Assembly Code: 27; Type Image: Raster image: Naturoll 035 .jpg (2); Model: Naturoll 035 is een onbeklede glaswoldeken met ECOSE® Technology; Manufacturer: Knauf Insulation B.V.; URL: www.knaufinsulation.nl; Description: Naturoll 035 - 120mm; phone: +31(0)162-421245; email: customerservice.nl@knaufinsulation.com; product URL: https://www.knaufinsulation.nl/producten-van-knauf-insulation/naturoll-035; warmteweerstand: 3.4; NLRS_C_Code_Brandklasse: A1; warmtegeleidingscoëfficiënt: 0.035; kortstondige waterabsorptie: WS; langdurige waterabsorptie: WL(P); waterdamptransmissie / waterdampdiffusie weerstandsfactor: MU1; luchtstroomweerstand: Afr5; DoP nummer (Declaration of performance): G4220LPCPR; NLRS_C_content_creator: Knauf Insulation; NLRS_C_content_versie: V1.0; diktebereik: 20 - 370; diktetolerantie: T2; pak (m2): 7.07; pakken / pallet: 24; pallet (m2): 169.63
Classification: 27 Daken (Uniformat); Material: Knauf Insulation_Ecose® glaswol_naturoll 035; Knauf Insulation_Ecose® glaswol_naturoll 035 120 mm
Pset_SlabCommon - PitchAngle: 0 deg
Pset_Roof Schedule Naturoll 035 LOD400 - Type: Basic Roof: NLRS_27_RO_Naturoll 035_120x380x6200mm

# IfcSlab: Basic Roof:NLRS_27_RO_Naturoll 035_120x580x6200mm, Basic Roof:NLRS_27_RO_Naturoll 035_120x580x6200mm:35045
In: Lengte
Type - PredefinedType: ROOF
Type - Pset_ElementShading - Roughness: 304.8 mm
Type - Pset_ManufacturerTypeInformation - Manufacturer: Knauf Insulation B.V.
Type - Pset_ProductRequirements - Category: Roofs
Type - Pset_QuantityTakeOff - Reference: Basic Roof:NLRS_27_RO_Naturoll 035_120x580x6200mm
Type - Pset_ReinforcementBarPitchOfSlab - Description: Naturoll 035 - 120mm; Reference: Basic Roof:NLRS_27_RO_Naturoll 035_120x580x6200mm
Type - Pset_SlabCommon - IsExternal: yes; Reference: Basic Roof:NLRS_27_RO_Naturoll 035_120x580x6200mm; ThermalTransmittance: 0.291667 kg/K/s3
Type - Pset_Roof Schedule Naturoll 035 LOD400 - rollen / pak: 2; Assembly Code: 27; Type Image: Raster image: Naturoll 035 .jpg (2); Model: Naturoll 035 is een onbeklede glaswoldeken met ECOSE® Technology; Manufacturer: Knauf Insulation B.V.; URL: www.knaufinsulation.nl; Description: Naturoll 035 - 120mm; phone: +31(0)162-421245; email: customerservice.nl@knaufinsulation.com; product URL: https://www.knaufinsulation.nl/producten-van-knauf-insulation/naturoll-035; warmteweerstand: 3.4; NLRS_C_Code_Brandklasse: A1; warmtegeleidingscoëfficiënt: 0.035; kortstondige waterabsorptie: WS; langdurige waterabsorptie: WL(P); waterdamptransmissie / waterdampdiffusie weerstandsfactor: MU1; luchtstroomweerstand: Afr5; DoP nummer (Declaration of performance): G4220LPCPR; NLRS_C_content_creator: Knauf Insulation; NLRS_C_content_versie: V1.0; diktebereik: 20 - 370; diktetolerantie: T2; pak (m2): 7.19; pakken / pallet: 24; pallet (m2): 172.61
Classification: 27 Daken (Uniformat); Material: Knauf Insulation_Ecose® glaswol_naturoll 035; Knauf Insulation_Ecose® glaswol_naturoll 035 120 mm
Pset_SlabCommon - PitchAngle: 0 deg
Pset_Roof Schedule Naturoll 035 LOD400 - Type: Basic Roof: NLRS_27_RO_Naturoll 035_120x580x6200mm

# IfcSlab: Basic Roof:NLRS_27_RO_Naturoll 035_130x590x5500mm, Basic Roof:NLRS_27_RO_Naturoll 035_130x590x5500mm:35067
In: Lengte
Type - PredefinedType: ROOF
Type - Pset_ElementShading - Roughness: 304.8 mm
Type - Pset_ManufacturerTypeInformation - Manufacturer: Knauf Insulation B.V.
Type - Pset_ProductRequirements - Category: Roofs
Type - Pset_QuantityTakeOff - Reference: Basic Roof:NLRS_27_RO_Naturoll 035_130x590x5500mm
Type - Pset_ReinforcementBarPitchOfSlab - Description: Naturoll 035 - 130mm; Reference: Basic Roof:NLRS_27_RO_Naturoll 035_130x590x5500mm
Type - Pset_SlabCommon - IsExternal: yes; Reference: Basic Roof:NLRS_27_RO_Naturoll 035_130x590x5500mm; ThermalTransmittance: 0.269231 kg/K/s3
Type - Pset_Roof Schedule Naturoll 035 LOD400 - rollen / pak: 2; Assembly Code: 27; Type Image: Raster image: Naturoll 035 .jpg (2); Model: Naturoll 035 is een onbeklede glaswoldeken met ECOSE® Technology; Manufacturer: Knauf Insulation B.V.; URL: www.knaufinsulation.nl; Description: Naturoll 035 - 130mm; phone: +31(0)162-421245; email: customerservice.nl@knaufinsulation.com; product URL: https://www.knaufinsulation.nl/producten-van-knauf-insulation/naturoll-035; warmteweerstand: 3.7; NLRS_C_Code_Brandklasse: A1; warmtegeleidingscoëfficiënt: 0.035; kortstondige waterabsorptie: WS; langdurige waterabsorptie: WL(P); waterdamptransmissie / waterdampdiffusie weerstandsfactor: MU1; luchtstroomweerstand: Afr5; DoP nummer (Declaration of performance): G4220LPCPR; NLRS_C_content_creator: Knauf Insulation; NLRS_C_content_versie: V1.0; diktebereik: 20 - 370; diktetolerantie: T2; pak (m2): 6.49; pakken / pallet: 24; pallet (m2): 155.76
Classification: 27 Daken (Uniformat); Material: Knauf Insulation_Ecose® glaswol_naturoll 035; Knauf Insulation_Ecose® glaswol_naturoll 035 130 mm
Pset_SlabCommon - PitchAngle: 0 deg
Pset_Roof Schedule Naturoll 035 LOD400 - Type: Basic Roof: NLRS_27_RO_Naturoll 035_130x590x5500mm

# IfcSlab: Basic Roof:NLRS_27_RO_Naturoll 035_135x590x5300mm, Basic Roof:NLRS_27_RO_Naturoll 035_135x590x5300mm:42298
In: Lengte
Type - PredefinedType: ROOF
Type - Pset_ElementShading - Roughness: 304.8 mm
Type - Pset_ManufacturerTypeInformation - Manufacturer: Knauf Insulation B.V.
Type - Pset_ProductRequirements - Category: Roofs
Type - Pset_QuantityTakeOff - Reference: Basic Roof:NLRS_27_RO_Naturoll 035_135x590x5300mm
Type - Pset_ReinforcementBarPitchOfSlab - Description: Naturoll 035 - 135mm; Reference: Basic Roof:NLRS_27_RO_Naturoll 035_135x590x5300mm
Type - Pset_SlabCommon - IsExternal: yes; Reference: Basic Roof:NLRS_27_RO_Naturoll 035_135x590x5300mm; ThermalTransmittance: 0.259259 kg/K/s3
Type - Pset_Roof Schedule Naturoll 035 LOD400 - rollen / pak: 2; Assembly Code: 27; Type Image: Raster image: Naturoll 035 .jpg (2); Model: Naturoll 035 is een onbeklede glaswoldeken met ECOSE® Technology; Manufacturer: Knauf Insulation B.V.; URL: www.knaufinsulation.nl; Description: Naturoll 035 - 135mm; phone: +31(0)162-421245; email: customerservice.nl@knaufinsulation.com; product URL: https://www.knaufinsulation.nl/producten-van-knauf-insulation/naturoll-035; warmteweerstand: 3.85; NLRS_C_Code_Brandklasse: A1; warmtegeleidingscoëfficiënt: 0.035; kortstondige waterabsorptie: WS; langdurige waterabsorptie: WL(P); waterdamptransmissie / waterdampdiffusie weerstandsfactor: MU1; luchtstroomweerstand: Afr5; DoP nummer (Declaration of performance): G4220LPCPR; NLRS_C_content_creator: Knauf Insulation; NLRS_C_content_versie: V1.0; diktebereik: 20 - 370; diktetolerantie: T2; pak (m2): 6.25; pakken / pallet: 24; pallet (m2): 150.1
Classification: 27 Daken (Uniformat); Material: Knauf Insulation_Ecose® glaswol_naturoll 035; Knauf Insulation_Ecose® glaswol_naturoll 035 135 mm
Pset_SlabCommon - PitchAngle: 0 deg
Pset_Roof Schedule Naturoll 035 LOD400 - Type: Basic Roof: NLRS_27_RO_Naturoll 035_135x590x5300mm

# IfcSlab: Basic Roof:NLRS_27_RO_Naturoll 035_140x380x5300mm, Basic Roof:NLRS_27_RO_Naturoll 035_140x380x5300mm:35117
In: Lengte
Type - PredefinedType: ROOF
Type - Pset_ElementShading - Roughness: 304.8 mm
Type - Pset_ManufacturerTypeInformation - Manufacturer: Knauf Insulation B.V.
Type - Pset_ProductRequirements - Category: Roofs
Type - Pset_QuantityTakeOff - Reference: Basic Roof:NLRS_27_RO_Naturoll 035_140x380x5300mm
Type - Pset_ReinforcementBarPitchOfSlab - Description: Naturoll 035 - 140mm; Reference: Basic Roof:NLRS_27_RO_Naturoll 035_140x380x5300mm
Type - Pset_SlabCommon - IsExternal: yes; ThermalTransmittance: 0.25 kg/K/s3; Reference: Basic Roof:NLRS_27_RO_Naturoll 035_140x380x5300mm
Type - Pset_Roof Schedule Naturoll 035 LOD400 - rollen / pak: 3; warmteweerstand: 4; Assembly Code: 27; Type Image: Raster image: Naturoll 035 .jpg (2); Model: Naturoll 035 is een onbeklede glaswoldeken met ECOSE® Technology; Manufacturer: Knauf Insulation B.V.; URL: www.knaufinsulation.nl; Description: Naturoll 035 - 140mm; phone: +31(0)162-421245; email: customerservice.nl@knaufinsulation.com; product URL: https://www.knaufinsulation.nl/producten-van-knauf-insulation/naturoll-035; NLRS_C_Code_Brandklasse: A1; warmtegeleidingscoëfficiënt: 0.035; kortstondige waterabsorptie: WS; langdurige waterabsorptie: WL(P); waterdamptransmissie / waterdampdiffusie weerstandsfactor: MU1; luchtstroomweerstand: Afr5; DoP nummer (Declaration of performance): G4220LPCPR; NLRS_C_content_creator: Knauf Insulation; NLRS_C_content_versie: V1.0; diktebereik: 20 - 370; diktetolerantie: T2; pak (m2): 6.04; pakken / pallet: 24; pallet (m2): 145.01
Classification: 27 Daken (Uniformat); Material: Knauf Insulation_Ecose® glaswol_naturoll 035; Knauf Insulation_Ecose® glaswol_naturoll 035 140 mm
Pset_SlabCommon - PitchAngle: 0 deg
Pset_Roof Schedule Naturoll 035 LOD400 - Type: Basic Roof: NLRS_27_RO_Naturoll 035_140x380x5300mm

# IfcSlab: Basic Roof:NLRS_27_RO_Naturoll 035_140x580x5300mm, Basic Roof:NLRS_27_RO_Naturoll 035_140x580x5300mm:35137
In: Lengte
Type - PredefinedType: ROOF
Type - Pset_ElementShading - Roughness: 304.8 mm
Type - Pset_ManufacturerTypeInformation - Manufacturer: Knauf Insulation B.V.
Type - Pset_ProductRequirements - Category: Roofs
Type - Pset_QuantityTakeOff - Reference: Basic Roof:NLRS_27_RO_Naturoll 035_140x580x5300mm
Type - Pset_ReinforcementBarPitchOfSlab - Description: Naturoll 035 - 140mm; Reference: Basic Roof:NLRS_27_RO_Naturoll 035_140x580x5300mm
Type - Pset_SlabCommon - IsExternal: yes; ThermalTransmittance: 0.25 kg/K/s3; Reference: Basic Roof:NLRS_27_RO_Naturoll 035_140x580x5300mm
Type - Pset_Roof Schedule Naturoll 035 LOD400 - rollen / pak: 2; warmteweerstand: 4; Assembly Code: 27; Type Image: Raster image: Naturoll 035 .jpg (2); Model: Naturoll 035 is een onbeklede glaswoldeken met ECOSE® Technology; Manufacturer: Knauf Insulation B.V.; URL: www.knaufinsulation.nl; Description: Naturoll 035 - 140mm; phone: +31(0)162-421245; email: customerservice.nl@knaufinsulation.com; product URL: https://www.knaufinsulation.nl/producten-van-knauf-insulation/naturoll-035; NLRS_C_Code_Brandklasse: A1; warmtegeleidingscoëfficiënt: 0.035; kortstondige waterabsorptie: WS; langdurige waterabsorptie: WL(P); waterdamptransmissie / waterdampdiffusie weerstandsfactor: MU1; luchtstroomweerstand: Afr5; DoP nummer (Declaration of performance): G4220LPCPR; NLRS_C_content_creator: Knauf Insulation; NLRS_C_content_versie: V1.0; diktebereik: 20 - 370; diktetolerantie: T2; pak (m2): 6.15; pakken / pallet: 24; pallet (m2): 147.55
Classification: 27 Daken (Uniformat); Material: Knauf Insulation_Ecose® glaswol_naturoll 035; Knauf Insulation_Ecose® glaswol_naturoll 035 140 mm
Pset_SlabCommon - PitchAngle: 0 deg
Pset_Roof Schedule Naturoll 035 LOD400 - Type: Basic Roof: NLRS_27_RO_Naturoll 035_140x580x5300mm

# IfcSlab: Basic Roof:NLRS_27_RO_Naturoll 035_170x380x4350mm, Basic Roof:NLRS_27_RO_Naturoll 035_170x380x4350mm:35177
In: Lengte
Type - PredefinedType: ROOF
Type - Pset_ElementShading - Roughness: 304.8 mm
Type - Pset_ManufacturerTypeInformation - Manufacturer: Knauf Insulation B.V.
Type - Pset_ProductRequirements - Category: Roofs
Type - Pset_QuantityTakeOff - Reference: Basic Roof:NLRS_27_RO_Naturoll 035_170x380x4350mm
Type - Pset_ReinforcementBarPitchOfSlab - Description: Naturoll 035 - 170mm; Reference: Basic Roof:NLRS_27_RO_Naturoll 035_170x380x4350mm
Type - Pset_SlabCommon - IsExternal: yes; Reference: Basic Roof:NLRS_27_RO_Naturoll 035_170x380x4350mm; ThermalTransmittance: 0.205882 kg/K/s3
Type - Pset_Roof Schedule Naturoll 035 LOD400 - rollen / pak: 3; Assembly Code: 27; Type Image: Raster image: Naturoll 035 .jpg (2); Model: Naturoll 035 is een onbeklede glaswoldeken met ECOSE® Technology; Manufacturer: Knauf Insulation B.V.; URL: www.knaufinsulation.nl; Description: Naturoll 035 - 170mm; phone: +31(0)162-421245; email: customerservice.nl@knaufinsulation.com; product URL: https://www.knaufinsulation.nl/producten-van-knauf-insulation/naturoll-035; warmteweerstand: 4.85; NLRS_C_Code_Brandklasse: A1; warmtegeleidingscoëfficiënt: 0.035; kortstondige waterabsorptie: WS; langdurige waterabsorptie: WL(P); waterdamptransmissie / waterdampdiffusie weerstandsfactor: MU1; luchtstroomweerstand: Afr5; DoP nummer (Declaration of performance): G4220LPCPR; NLRS_C_content_creator: Knauf Insulation; NLRS_C_content_versie: V1.0; diktebereik: 20 - 370; diktetolerantie: T2; pak (m2): 4.96; pakken / pallet: 24; pallet (m2): 119.02
Classification: 27 Daken (Uniformat); Material: Knauf Insulation_Ecose® glaswol_naturoll 035; Knauf Insulation_Ecose® glaswol_naturoll 035 170 mm
Pset_SlabCommon - PitchAngle: 0 deg
Pset_Roof Schedule Naturoll 035 LOD400 - Type: Basic Roof: NLRS_27_RO_Naturoll 035_170x380x4350mm

# IfcSlab: Basic Roof:NLRS_27_RO_Naturoll 035_170x580x4350mm, Basic Roof:NLRS_27_RO_Naturoll 035_170x580x4350mm:35197
In: Lengte
Type - PredefinedType: ROOF
Type - Pset_ElementShading - Roughness: 304.8 mm
Type - Pset_ManufacturerTypeInformation - Manufacturer: Knauf Insulation B.V.
Type - Pset_ProductRequirements - Category: Roofs
Type - Pset_QuantityTakeOff - Reference: Basic Roof:NLRS_27_RO_Naturoll 035_170x580x4350mm
Type - Pset_ReinforcementBarPitchOfSlab - Description: Naturoll 035 - 170mm; Reference: Basic Roof:NLRS_27_RO_Naturoll 035_170x580x4350mm
Type - Pset_SlabCommon - IsExternal: yes; Reference: Basic Roof:NLRS_27_RO_Naturoll 035_170x580x4350mm; ThermalTransmittance: 0.205882 kg/K/s3
Type - Pset_Roof Schedule Naturoll 035 LOD400 - rollen / pak: 2; Assembly Code: 27; Type Image: Raster image: Naturoll 035 .jpg (2); Model: Naturoll 035 is een onbeklede glaswoldeken met ECOSE® Technology; Manufacturer: Knauf Insulation B.V.; URL: www.knaufinsulation.nl; Description: Naturoll 035 - 170mm; phone: +31(0)162-421245; email: customerservice.nl@knaufinsulation.com; product URL: https://www.knaufinsulation.nl/producten-van-knauf-insulation/naturoll-035; warmteweerstand: 4.85; NLRS_C_Code_Brandklasse: A1; warmtegeleidingscoëfficiënt: 0.035; kortstondige waterabsorptie: WS; langdurige waterabsorptie: WL(P); waterdamptransmissie / waterdampdiffusie weerstandsfactor: MU1; luchtstroomweerstand: Afr5; DoP nummer (Declaration of performance): G4220LPCPR; NLRS_C_content_creator: Knauf Insulation; NLRS_C_content_versie: V1.0; diktebereik: 20 - 370; diktetolerantie: T2; pak (m2): 5.05; pakken / pallet: 24; pallet (m2): 121.1
Classification: 27 Daken (Uniformat); Material: Knauf Insulation_Ecose® glaswol_naturoll 035; Knauf Insulation_Ecose® glaswol_naturoll 035 170 mm
Pset_SlabCommon - PitchAngle: 0 deg
Pset_Roof Schedule Naturoll 035 LOD400 - Type: Basic Roof: NLRS_27_RO_Naturoll 035_170x580x4350mm

# IfcSlab: Basic Roof:NLRS_27_RO_Naturoll 035_185x380x4000mm, Basic Roof:NLRS_27_RO_Naturoll 035_185x380x4000mm:35217
In: Lengte
Type - PredefinedType: ROOF
Type - Pset_ElementShading - Roughness: 304.8 mm
Type - Pset_ManufacturerTypeInformation - Manufacturer: Knauf Insulation B.V.
Type - Pset_ProductRequirements - Category: Roofs
Type - Pset_QuantityTakeOff - Reference: Basic Roof:NLRS_27_RO_Naturoll 035_185x380x4000mm
Type - Pset_ReinforcementBarPitchOfSlab - Description: Naturoll 035 - 185mm; Reference: Basic Roof:NLRS_27_RO_Naturoll 035_185x380x4000mm
Type - Pset_SlabCommon - IsExternal: yes; Reference: Basic Roof:NLRS_27_RO_Naturoll 035_185x380x4000mm; ThermalTransmittance: 0.189189 kg/K/s3
Type - Pset_Roof Schedule Naturoll 035 LOD400 - rollen / pak: 3; Assembly Code: 27; Type Image: Raster image: Naturoll 035 .jpg (2); Model: Naturoll 035 is een onbeklede glaswoldeken met ECOSE® Technology; Manufacturer: Knauf Insulation B.V.; URL: www.knaufinsulation.nl; Description: Naturoll 035 - 185mm; phone: +31(0)162-421245; email: customerservice.nl@knaufinsulation.com; product URL: https://www.knaufinsulation.nl/producten-van-knauf-insulation/naturoll-035; warmteweerstand: 5.25; NLRS_C_Code_Brandklasse: A1; warmtegeleidingscoëfficiënt: 0.035; kortstondige waterabsorptie: WS; langdurige waterabsorptie: WL(P); waterdamptransmissie / waterdampdiffusie weerstandsfactor: MU1; luchtstroomweerstand: Afr5; DoP nummer (Declaration of performance): G4220LPCPR; NLRS_C_content_creator: Knauf Insulation; NLRS_C_content_versie: V1.0; diktebereik: 20 - 370; diktetolerantie: T2; pak (m2): 4.56; pakken / pallet: 24; pallet (m2): 109.44
Classification: 27 Daken (Uniformat); Material: Knauf Insulation_Ecose® glaswol_naturoll 035; Knauf Insulation_Ecose® glaswol_naturoll 035 185 mm
Pset_SlabCommon - PitchAngle: 0 deg
Pset_Roof Schedule Naturoll 035 LOD400 - Type: Basic Roof: NLRS_27_RO_Naturoll 035_185x380x4000mm

# IfcSlab: Basic Roof:NLRS_27_RO_Naturoll 035_185x580x4000mm, Basic Roof:NLRS_27_RO_Naturoll 035_185x580x4000mm:37505
In: Lengte
Type - PredefinedType: ROOF
Type - Pset_ElementShading - Roughness: 304.8 mm
Type - Pset_ManufacturerTypeInformation - Manufacturer: Knauf Insulation B.V.
Type - Pset_ProductRequirements - Category: Roofs
Type - Pset_QuantityTakeOff - Reference: Basic Roof:NLRS_27_RO_Naturoll 035_185x580x4000mm
Type - Pset_ReinforcementBarPitchOfSlab - Description: Naturoll 035 - 185mm; Reference: Basic Roof:NLRS_27_RO_Naturoll 035_185x580x4000mm
Type - Pset_SlabCommon - IsExternal: yes; Reference: Basic Roof:NLRS_27_RO_Naturoll 035_185x580x4000mm; ThermalTransmittance: 0.189189 kg/K/s3
Type - Pset_Roof Schedule Naturoll 035 LOD400 - rollen / pak: 2; Assembly Code: 27; Type Image: Raster image: Naturoll 035 .jpg (2); Model: Naturoll 035 is een onbeklede glaswoldeken met ECOSE® Technology; Manufacturer: Knauf Insulation B.V.; URL: www.knaufinsulation.nl; Description: Naturoll 035 - 185mm; phone: +31(0)162-421245; email: customerservice.nl@knaufinsulation.com; product URL: https://www.knaufinsulation.nl/producten-van-knauf-insulation/naturoll-035; warmteweerstand: 5.25; NLRS_C_Code_Brandklasse: A1; warmtegeleidingscoëfficiënt: 0.035; kortstondige waterabsorptie: WS; langdurige waterabsorptie: WL(P); waterdamptransmissie / waterdampdiffusie weerstandsfactor: MU1; luchtstroomweerstand: Afr5; DoP nummer (Declaration of performance): G4220LPCPR; NLRS_C_content_creator: Knauf Insulation; NLRS_C_content_versie: V1.0; diktebereik: 20 - 370; diktetolerantie: T2; pak (m2): 4.64; pakken / pallet: 24; pallet (m2): 111.36
Classification: 27 Daken (Uniformat); Material: Knauf Insulation_Ecose® glaswol_naturoll 035; Knauf Insulation_Ecose® glaswol_naturoll 035 185 mm
Pset_SlabCommon - PitchAngle: 0 deg
Pset_Roof Schedule Naturoll 035 LOD400 - Type: Basic Roof: NLRS_27_RO_Naturoll 035_185x580x4000mm

# IfcSlab: Basic Roof:NLRS_27_RO_Naturoll 035_200x580x3700mm, Basic Roof:NLRS_27_RO_Naturoll 035_200x580x3700mm:35405
In: Lengte
Type - PredefinedType: ROOF
Type - Pset_ElementShading - Roughness: 304.8 mm
Type - Pset_ManufacturerTypeInformation - Manufacturer: Knauf Insulation B.V.
Type - Pset_ProductRequirements - Category: Roofs
Type - Pset_QuantityTakeOff - Reference: Basic Roof:NLRS_27_RO_Naturoll 035_200x580x3700mm
Type - Pset_ReinforcementBarPitchOfSlab - Description: Naturoll 035 - 200mm; Reference: Basic Roof:NLRS_27_RO_Naturoll 035_200x580x3700mm
Type - Pset_SlabCommon - IsExternal: yes; Reference: Basic Roof:NLRS_27_RO_Naturoll 035_200x580x3700mm; ThermalTransmittance: 0.175 kg/K/s3
Type - Pset_Roof Schedule Naturoll 035 LOD400 - rollen / pak: 2; Assembly Code: 27; Type Image: Raster image: Naturoll 035 .jpg (2); Model: Naturoll 035 is een onbeklede glaswoldeken met ECOSE® Technology; Manufacturer: Knauf Insulation B.V.; URL: www.knaufinsulation.nl; Description: Naturoll 035 - 200mm; phone: +31(0)162-421245; email: customerservice.nl@knaufinsulation.com; product URL: https://www.knaufinsulation.nl/producten-van-knauf-insulation/naturoll-035; warmteweerstand: 5.7; NLRS_C_Code_Brandklasse: A1; warmtegeleidingscoëfficiënt: 0.035; kortstondige waterabsorptie: WS; langdurige waterabsorptie: WL(P); waterdamptransmissie / waterdampdiffusie weerstandsfactor: MU1; luchtstroomweerstand: Afr5; DoP nummer (Declaration of performance): G4220LPCPR; NLRS_C_content_creator: Knauf Insulation; NLRS_C_content_versie: V1.0; diktebereik: 20 - 370; diktetolerantie: T2; pak (m2): 4.29; pakken / pallet: 24; pallet (m2): 103.01
Classification: 27 Daken (Uniformat); Material: Knauf Insulation_Ecose® glaswol_naturoll 035; Knauf Insulation_Ecose® glaswol_naturoll 035 200 mm
Pset_SlabCommon - PitchAngle: 0 deg
Pset_Roof Schedule Naturoll 035 LOD400 - Type: Basic Roof: NLRS_27_RO_Naturoll 035_200x580x3700mm

# IfcSlab: Basic Roof:NLRS_27_RO_Naturoll 035_220x380x3400mm, Basic Roof:NLRS_27_RO_Naturoll 035_220x380x3400mm:35424
In: Lengte
Type - PredefinedType: ROOF
Type - Pset_ElementShading - Roughness: 304.8 mm
Type - Pset_ManufacturerTypeInformation - Manufacturer: Knauf Insulation B.V.
Type - Pset_ProductRequirements - Category: Roofs
Type - Pset_QuantityTakeOff - Reference: Basic Roof:NLRS_27_RO_Naturoll 035_220x380x3400mm
Type - Pset_ReinforcementBarPitchOfSlab - Description: Naturoll 035 - 220mm; Reference: Basic Roof:NLRS_27_RO_Naturoll 035_220x380x3400mm
Type - Pset_SlabCommon - IsExternal: yes; Reference: Basic Roof:NLRS_27_RO_Naturoll 035_220x380x3400mm; ThermalTransmittance: 0.159091 kg/K/s3
Type - Pset_Roof Schedule Naturoll 035 LOD400 - rollen / pak: 3; Assembly Code: 27; Type Image: Raster image: Naturoll 035 .jpg (2); Model: Naturoll 035 is een onbeklede glaswoldeken met ECOSE® Technology; Manufacturer: Knauf Insulation B.V.; URL: www.knaufinsulation.nl; Description: Naturoll 035 - 220mm; phone: +31(0)162-421245; email: customerservice.nl@knaufinsulation.com; product URL: https://www.knaufinsulation.nl/producten-van-knauf-insulation/naturoll-035; warmteweerstand: 6.25; NLRS_C_Code_Brandklasse: A1; warmtegeleidingscoëfficiënt: 0.035; kortstondige waterabsorptie: WS; langdurige waterabsorptie: WL(P); waterdamptransmissie / waterdampdiffusie weerstandsfactor: MU1; luchtstroomweerstand: Afr5; DoP nummer (Declaration of performance): G4220LPCPR; NLRS_C_content_creator: Knauf Insulation; NLRS_C_content_versie: V1.0; diktebereik: 20 - 370; diktetolerantie: T2; pak (m2): 3.88; pakken / pallet: 24; pallet (m2): 93.02
Classification: 27 Daken (Uniformat); Material: Knauf Insulation_Ecose® glaswol_naturoll 035; Knauf Insulation_Ecose® glaswol_naturoll 035 220 mm
Pset_SlabCommon - PitchAngle: 0 deg
Pset_Roof Schedule Naturoll 035 LOD400 - Type: Basic Roof: NLRS_27_RO_Naturoll 035_220x380x3400mm

# IfcSlab: Basic Roof:NLRS_27_RO_Naturoll 035_220x580x3400mm, Basic Roof:NLRS_27_RO_Naturoll 035_220x580x3400mm:35443
In: Lengte
Type - PredefinedType: ROOF
Type - Pset_ElementShading - Roughness: 304.8 mm
Type - Pset_ManufacturerTypeInformation - Manufacturer: Knauf Insulation B.V.
Type - Pset_ProductRequirements - Category: Roofs
Type - Pset_QuantityTakeOff - Reference: Basic Roof:NLRS_27_RO_Naturoll 035_220x580x3400mm
Type - Pset_ReinforcementBarPitchOfSlab - Description: Naturoll 035 - 220mm; Reference: Basic Roof:NLRS_27_RO_Naturoll 035_220x580x3400mm
Type - Pset_SlabCommon - IsExternal: yes; Reference: Basic Roof:NLRS_27_RO_Naturoll 035_220x580x3400mm; ThermalTransmittance: 0.159091 kg/K/s3
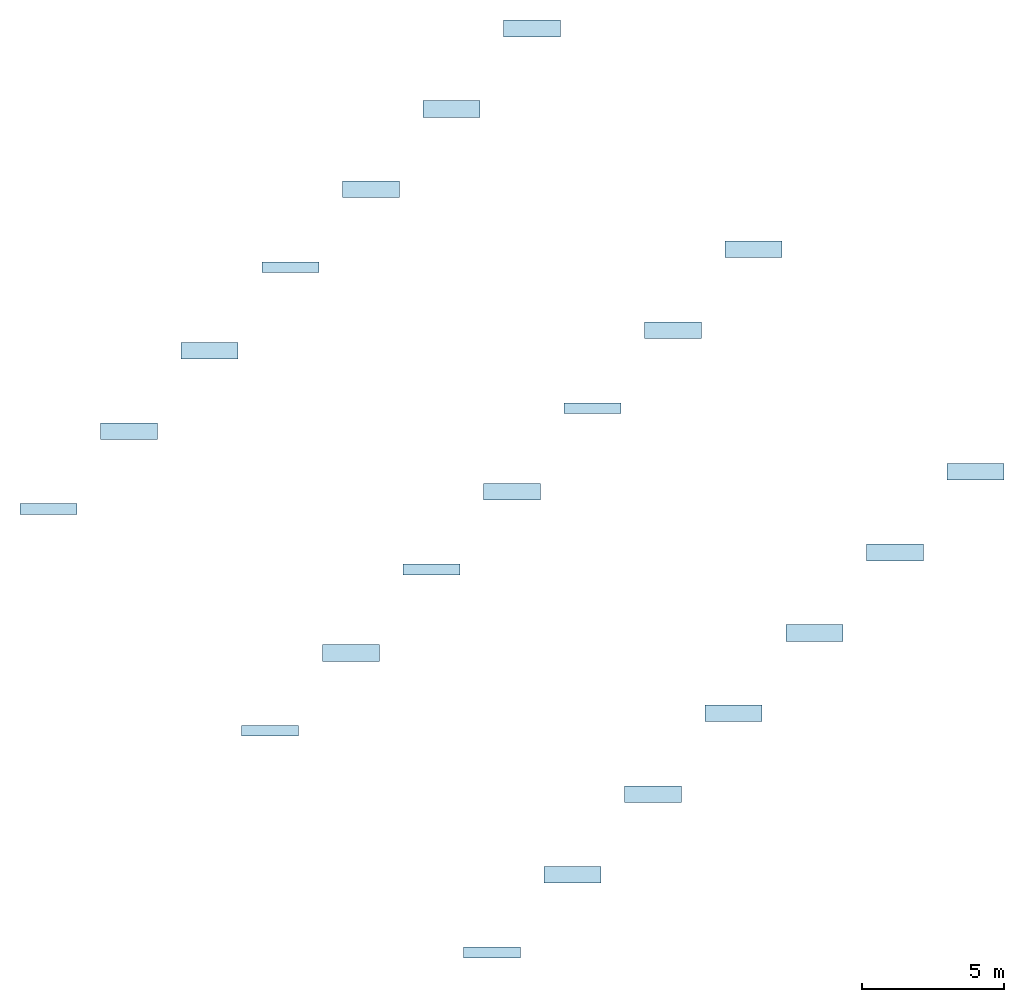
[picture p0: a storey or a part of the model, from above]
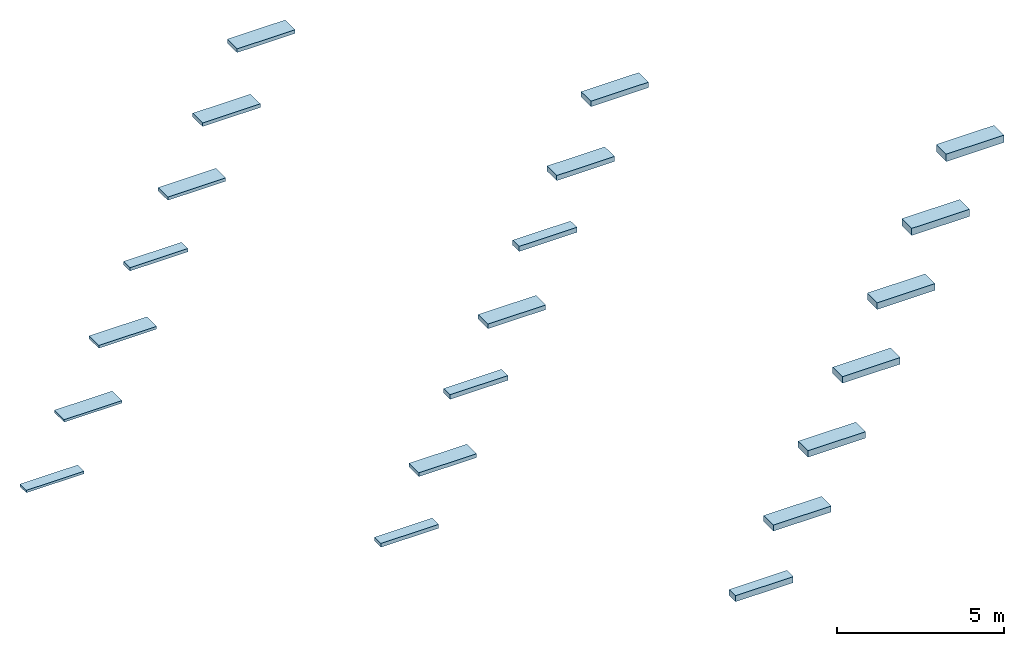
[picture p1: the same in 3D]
Properties of the parts of a building model (IFC2X3), part 2 of 3

# IfcSlab: Basic Roof:NLRS_27_RO_Naturoll 035_220x580x3400mm, Basic Roof:NLRS_27_RO_Naturoll 035_220x580x3400mm:35443
Type - Pset_Roof Schedule Naturoll 035 LOD400 - rollen / pak: 2; Assembly Code: 27; Type Image: Raster image: Naturoll 035 .jpg (2); Model: Naturoll 035 is een onbeklede glaswoldeken met ECOSE® Technology; Manufacturer: Knauf Insulation B.V.; URL: www.knaufinsulation.nl; Description: Naturoll 035 - 220mm; phone: +31(0)162-421245; email: customerservice.nl@knaufinsulation.com; product URL: https://www.knaufinsulation.nl/producten-van-knauf-insulation/naturoll-035; warmteweerstand: 6.25; NLRS_C_Code_Brandklasse: A1; warmtegeleidingscoëfficiënt: 0.035; kortstondige waterabsorptie: WS; langdurige waterabsorptie: WL(P); waterdamptransmissie / waterdampdiffusie weerstandsfactor: MU1; luchtstroomweerstand: Afr5; DoP nummer (Declaration of performance): G4220LPCPR; NLRS_C_content_creator: Knauf Insulation; NLRS_C_content_versie: V1.0; diktebereik: 20 - 370; diktetolerantie: T2; pak (m2): 3.94; pakken / pallet: 24; pallet (m2): 94.66
Classification: 27 Daken (Uniformat); Material: Knauf Insulation_Ecose® glaswol_naturoll 035; Knauf Insulation_Ecose® glaswol_naturoll 035 220 mm
Pset_SlabCommon - PitchAngle: 0 deg
Pset_Roof Schedule Naturoll 035 LOD400 - Type: Basic Roof: NLRS_27_RO_Naturoll 035_220x580x3400mm

# IfcSlab: Basic Roof:NLRS_27_RO_Naturoll 035_235x580x3100mm, Basic Roof:NLRS_27_RO_Naturoll 035_235x580x3100mm:35462
In: Lengte
Type - PredefinedType: ROOF
Type - Pset_ElementShading - Roughness: 304.8 mm
Type - Pset_ManufacturerTypeInformation - Manufacturer: Knauf Insulation B.V.
Type - Pset_ProductRequirements - Category: Roofs
Type - Pset_QuantityTakeOff - Reference: Basic Roof:NLRS_27_RO_Naturoll 035_235x580x3100mm
Type - Pset_ReinforcementBarPitchOfSlab - Description: Naturoll 035 - 235mm; Reference: Basic Roof:NLRS_27_RO_Naturoll 035_235x580x3100mm
Type - Pset_SlabCommon - IsExternal: yes; Reference: Basic Roof:NLRS_27_RO_Naturoll 035_235x580x3100mm; ThermalTransmittance: 0.148936 kg/K/s3
Type - Pset_Roof Schedule Naturoll 035 LOD400 - rollen / pak: 2; Assembly Code: 27; Type Image: Raster image: Naturoll 035 .jpg (2); Model: Naturoll 035 is een onbeklede glaswoldeken met ECOSE® Technology; Manufacturer: Knauf Insulation B.V.; URL: www.knaufinsulation.nl; Description: Naturoll 035 - 235mm; phone: +31(0)162-421245; email: customerservice.nl@knaufinsulation.com; product URL: https://www.knaufinsulation.nl/producten-van-knauf-insulation/naturoll-035; warmteweerstand: 6.7; NLRS_C_Code_Brandklasse: A1; warmtegeleidingscoëfficiënt: 0.035; kortstondige waterabsorptie: WS; langdurige waterabsorptie: WL(P); waterdamptransmissie / waterdampdiffusie weerstandsfactor: MU1; luchtstroomweerstand: Afr5; DoP nummer (Declaration of performance): G4220LPCPR; NLRS_C_content_creator: Knauf Insulation; NLRS_C_content_versie: V1.0; diktebereik: 20 - 370; diktetolerantie: T2; pak (m2): 3.6; pakken / pallet: 24; pallet (m2): 86.3
Classification: 27 Daken (Uniformat); Material: Knauf Insulation_Ecose® glaswol_naturoll 035; Knauf Insulation_Ecose® glaswol_naturoll 035 235 mm
Pset_SlabCommon - PitchAngle: 0 deg
Pset_Roof Schedule Naturoll 035 LOD400 - Type: Basic Roof: NLRS_27_RO_Naturoll 035_235x580x3100mm

# IfcSlab: Basic Roof:NLRS_27_RO_Naturoll 035_240x580x3100mm, Basic Roof:NLRS_27_RO_Naturoll 035_240x580x3100mm:35481
In: Lengte
Type - PredefinedType: ROOF
Type - Pset_ElementShading - Roughness: 304.8 mm
Type - Pset_ManufacturerTypeInformation - Manufacturer: Knauf Insulation B.V.
Type - Pset_ProductRequirements - Category: Roofs
Type - Pset_QuantityTakeOff - Reference: Basic Roof:NLRS_27_RO_Naturoll 035_240x580x3100mm
Type - Pset_ReinforcementBarPitchOfSlab - Description: Naturoll 035 - 240mm; Reference: Basic Roof:NLRS_27_RO_Naturoll 035_240x580x3100mm
Type - Pset_SlabCommon - IsExternal: yes; Reference: Basic Roof:NLRS_27_RO_Naturoll 035_240x580x3100mm; ThermalTransmittance: 0.145833 kg/K/s3
Type - Pset_Roof Schedule Naturoll 035 LOD400 - rollen / pak: 2; Assembly Code: 27; Type Image: Raster image: Naturoll 035 .jpg (2); Model: Naturoll 035 is een onbeklede glaswoldeken met ECOSE® Technology; Manufacturer: Knauf Insulation B.V.; URL: www.knaufinsulation.nl; Description: Naturoll 035 - 240mm; phone: +31(0)162-421245; email: customerservice.nl@knaufinsulation.com; product URL: https://www.knaufinsulation.nl/producten-van-knauf-insulation/naturoll-035; warmteweerstand: 6.85; NLRS_C_Code_Brandklasse: A1; warmtegeleidingscoëfficiënt: 0.035; kortstondige waterabsorptie: WS; langdurige waterabsorptie: WL(P); waterdamptransmissie / waterdampdiffusie weerstandsfactor: MU1; luchtstroomweerstand: Afr5; DoP nummer (Declaration of performance): G4220LPCPR; NLRS_C_content_creator: Knauf Insulation; NLRS_C_content_versie: V1.0; diktebereik: 20 - 370; diktetolerantie: T2; pak (m2): 3.6; pakken / pallet: 24; pallet (m2): 86.3
Classification: 27 Daken (Uniformat); Material: Knauf Insulation_Ecose® glaswol_naturoll 035; Knauf Insulation_Ecose® glaswol_naturoll 035 240 mm
Pset_SlabCommon - PitchAngle: 0 deg
Pset_Roof Schedule Naturoll 035 LOD400 - Type: Basic Roof: NLRS_27_RO_Naturoll 035_240x580x3100mm

# IfcSlab: Basic Roof:NLRS_27_RO_Naturoll 035_245x590x2600mm, Basic Roof:NLRS_27_RO_Naturoll 035_245x590x2600mm:42674
In: Lengte
Type - PredefinedType: ROOF
Type - Pset_ElementShading - Roughness: 304.8 mm
Type - Pset_ManufacturerTypeInformation - Manufacturer: Knauf Insulation B.V.
Type - Pset_ProductRequirements - Category: Roofs
Type - Pset_QuantityTakeOff - Reference: Basic Roof:NLRS_27_RO_Naturoll 035_245x590x2600mm
Type - Pset_ReinforcementBarPitchOfSlab - Description: Naturoll 035 - 245mm; Reference: Basic Roof:NLRS_27_RO_Naturoll 035_245x590x2600mm
Type - Pset_SlabCommon - IsExternal: yes; Reference: Basic Roof:NLRS_27_RO_Naturoll 035_245x590x2600mm; ThermalTransmittance: 0.142857 kg/K/s3
Type - Pset_Roof Schedule Naturoll 035 LOD400 - rollen / pak: 2; warmteweerstand: 7; Assembly Code: 27; Type Image: Raster image: Naturoll 035 .jpg (2); Model: Naturoll 035 is een onbeklede glaswoldeken met ECOSE® Technology; Manufacturer: Knauf Insulation B.V.; URL: www.knaufinsulation.nl; Description: Naturoll 035 - 245mm; phone: +31(0)162-421245; email: customerservice.nl@knaufinsulation.com; product URL: https://www.knaufinsulation.nl/producten-van-knauf-insulation/naturoll-035; NLRS_C_Code_Brandklasse: A1; warmtegeleidingscoëfficiënt: 0.035; kortstondige waterabsorptie: WS; langdurige waterabsorptie: WL(P); waterdamptransmissie / waterdampdiffusie weerstandsfactor: MU1; luchtstroomweerstand: Afr5; DoP nummer (Declaration of performance): G4220LPCPR; NLRS_C_content_creator: Knauf Insulation; NLRS_C_content_versie: V1.0; diktebereik: 20 - 370; diktetolerantie: T2; pak (m2): 3.07; pakken / pallet: 24; pallet (m2): 73.63
Classification: 27 Daken (Uniformat); Material: Knauf Insulation_Ecose® glaswol_naturoll 035; Knauf Insulation_Ecose® glaswol_naturoll 035 245 mm
Pset_SlabCommon - PitchAngle: 0 deg
Pset_Roof Schedule Naturoll 035 LOD400 - Type: Basic Roof: NLRS_27_RO_Naturoll 035_245x590x2600mm

# IfcSlab: Basic Roof:NLRS_27_RO_Naturoll 035_260x590x2700mm, Basic Roof:NLRS_27_RO_Naturoll 035_260x590x2700mm:42613
In: Lengte
Type - PredefinedType: ROOF
Type - Pset_ElementShading - Roughness: 304.8 mm
Type - Pset_ManufacturerTypeInformation - Manufacturer: Knauf Insulation B.V.
Type - Pset_ProductRequirements - Category: Roofs
Type - Pset_QuantityTakeOff - Reference: Basic Roof:NLRS_27_RO_Naturoll 035_260x590x2700mm
Type - Pset_ReinforcementBarPitchOfSlab - Description: Naturoll 035 - 260mm; Reference: Basic Roof:NLRS_27_RO_Naturoll 035_260x590x2700mm
Type - Pset_SlabCommon - IsExternal: yes; Reference: Basic Roof:NLRS_27_RO_Naturoll 035_260x590x2700mm; ThermalTransmittance: 0.134615 kg/K/s3
Type - Pset_Roof Schedule Naturoll 035 LOD400 - rollen / pak: 2; Assembly Code: 27; Type Image: Raster image: Naturoll 035 .jpg (2); Model: Naturoll 035 is een onbeklede glaswoldeken met ECOSE® Technology; Manufacturer: Knauf Insulation B.V.; URL: www.knaufinsulation.nl; Description: Naturoll 035 - 260mm; phone: +31(0)162-421245; email: customerservice.nl@knaufinsulation.com; product URL: https://www.knaufinsulation.nl/producten-van-knauf-insulation/naturoll-035; warmteweerstand: 7.4; NLRS_C_Code_Brandklasse: A1; warmtegeleidingscoëfficiënt: 0.035; kortstondige waterabsorptie: WS; langdurige waterabsorptie: WL(P); waterdamptransmissie / waterdampdiffusie weerstandsfactor: MU1; luchtstroomweerstand: Afr5; DoP nummer (Declaration of performance): G4220LPCPR; NLRS_C_content_creator: Knauf Insulation; NLRS_C_content_versie: V1.0; diktebereik: 20 - 370; diktetolerantie: T2; pak (m2): 3.19; pakken / pallet: 24; pallet (m2): 76.05
Classification: 27 Daken (Uniformat); Material: Knauf Insulation_Ecose® glaswol_naturoll 035; Knauf Insulation_Ecose® glaswol_naturoll 035 260 mm
Pset_SlabCommon - PitchAngle: 0 deg
Pset_Roof Schedule Naturoll 035 LOD400 - Type: Basic Roof: NLRS_27_RO_Naturoll 035_260x590x2700mm

# IfcSlab: Basic Roof:NLRS_27_RO_Naturoll 035_270x590x2600mm, Basic Roof:NLRS_27_RO_Naturoll 035_270x590x2600mm:35500
In: Lengte
Type - PredefinedType: ROOF
Type - Pset_ElementShading - Roughness: 304.8 mm
Type - Pset_ManufacturerTypeInformation - Manufacturer: Knauf Insulation B.V.
Type - Pset_ProductRequirements - Category: Roofs
Type - Pset_QuantityTakeOff - Reference: Basic Roof:NLRS_27_RO_Naturoll 035_270x590x2600mm
Type - Pset_ReinforcementBarPitchOfSlab - Description: Naturoll 035 - 270mm; Reference: Basic Roof:NLRS_27_RO_Naturoll 035_270x590x2600mm
Type - Pset_SlabCommon - IsExternal: yes; Reference: Basic Roof:NLRS_27_RO_Naturoll 035_270x590x2600mm; ThermalTransmittance: 0.12963 kg/K/s3
Type - Pset_Roof Schedule Naturoll 035 LOD400 - rollen / pak: 2; Assembly Code: 27; Type Image: Raster image: Naturoll 035 .jpg (2); Model: Naturoll 035 is een onbeklede glaswoldeken met ECOSE® Technology; Manufacturer: Knauf Insulation B.V.; URL: www.knaufinsulation.nl; Description: Naturoll 035 - 270mm; phone: +31(0)162-421245; email: customerservice.nl@knaufinsulation.com; product URL: https://www.knaufinsulation.nl/producten-van-knauf-insulation/naturoll-035; warmteweerstand: 7.7; NLRS_C_Code_Brandklasse: A1; warmtegeleidingscoëfficiënt: 0.035; kortstondige waterabsorptie: WS; langdurige waterabsorptie: WL(P); waterdamptransmissie / waterdampdiffusie weerstandsfactor: MU1; luchtstroomweerstand: Afr5; DoP nummer (Declaration of performance): G4220LPCPR; NLRS_C_content_creator: Knauf Insulation; NLRS_C_content_versie: V1.0; diktebereik: 20 - 370; diktetolerantie: T2; pak (m2): 3.07; pakken / pallet: 24; pallet (m2): 73.63
Classification: 27 Daken (Uniformat); Material: Knauf Insulation_Ecose® glaswol_naturoll 035; Knauf Insulation_Ecose® glaswol_naturoll 035 270 mm
Pset_SlabCommon - PitchAngle: 0 deg
Pset_Roof Schedule Naturoll 035 LOD400 - Type: Basic Roof: NLRS_27_RO_Naturoll 035_270x590x2600mm

# IfcSlab: Basic Roof:NLRS_27_RO_Naturoll 035_90x380x7600mm, Basic Roof:NLRS_27_RO_Naturoll 035_90x380x7600mm:34727
In: Lengte
Type - PredefinedType: ROOF
Type - Pset_ElementShading - Roughness: 304.8 mm
Type - Pset_ManufacturerTypeInformation - Manufacturer: Knauf Insulation B.V.
Type - Pset_ProductRequirements - Category: Roofs
Type - Pset_QuantityTakeOff - Reference: Basic Roof:NLRS_27_RO_Naturoll 035_90x380x7600mm
Type - Pset_ReinforcementBarPitchOfSlab - Description: Naturoll 035 - 90mm; Reference: Basic Roof:NLRS_27_RO_Naturoll 035_90x380x7600mm
Type - Pset_SlabCommon - IsExternal: yes; Reference: Basic Roof:NLRS_27_RO_Naturoll 035_90x380x7600mm; ThermalTransmittance: 0.388889 kg/K/s3
Type - Pset_Roof Schedule Naturoll 035 LOD400 - rollen / pak: 3; Assembly Code: 27; Type Image: Raster image: Naturoll 035 .jpg (2); Model: Naturoll 035 is een onbeklede glaswoldeken met ECOSE® Technology; Manufacturer: Knauf Insulation B.V.; URL: www.knaufinsulation.nl; Description: Naturoll 035 - 90mm; phone: +31(0)162-421245; email: customerservice.nl@knaufinsulation.com; product URL: https://www.knaufinsulation.nl/producten-van-knauf-insulation/naturoll-035; warmteweerstand: 2.55; NLRS_C_Code_Brandklasse: A1; warmtegeleidingscoëfficiënt: 0.035; kortstondige waterabsorptie: WS; langdurige waterabsorptie: WL(P); waterdamptransmissie / waterdampdiffusie weerstandsfactor: MU1; luchtstroomweerstand: Afr5; DoP nummer (Declaration of performance): G4220LPCPR; NLRS_C_content_creator: Knauf Insulation; NLRS_C_content_versie: V1.0; diktebereik: 20 - 370; diktetolerantie: T2; pak (m2): 8.66; pakken / pallet: 24; pallet (m2): 207.94
Classification: 27 Daken (Uniformat); Material: Knauf Insulation_Ecose® glaswol_naturoll 035; Knauf Insulation_Ecose® glaswol_naturoll 035 90 mm
Pset_SlabCommon - PitchAngle: 0 deg
Pset_Roof Schedule Naturoll 035 LOD400 - Type: Basic Roof: NLRS_27_RO_Naturoll 035_90x380x7600mm

# IfcSlab: Basic Roof:NLRS_27_RO_Naturoll 035_90x580x7600mm, Basic Roof:NLRS_27_RO_Naturoll 035_90x580x7600mm:34921
In: Lengte
Type - PredefinedType: ROOF
Type - Pset_ElementShading - Roughness: 304.8 mm
Type - Pset_ManufacturerTypeInformation - Manufacturer: Knauf Insulation B.V.
Type - Pset_ProductRequirements - Category: Roofs
Type - Pset_QuantityTakeOff - Reference: Basic Roof:NLRS_27_RO_Naturoll 035_90x580x7600mm
Type - Pset_ReinforcementBarPitchOfSlab - Description: Naturoll 035 - 90mm; Reference: Basic Roof:NLRS_27_RO_Naturoll 035_90x580x7600mm
Type - Pset_SlabCommon - IsExternal: yes; Reference: Basic Roof:NLRS_27_RO_Naturoll 035_90x580x7600mm; ThermalTransmittance: 0.388889 kg/K/s3
Type - Pset_Roof Schedule Naturoll 035 LOD400 - rollen / pak: 2; Assembly Code: 27; Type Image: Raster image: Naturoll 035 .jpg (2); Model: Naturoll 035 is een onbeklede glaswoldeken met ECOSE® Technology; Manufacturer: Knauf Insulation B.V.; URL: www.knaufinsulation.nl; Description: Naturoll 035 - 90mm; phone: +31(0)162-421245; email: customerservice.nl@knaufinsulation.com; product URL: https://www.knaufinsulation.nl/producten-van-knauf-insulation/naturoll-035; warmteweerstand: 2.55; NLRS_C_Code_Brandklasse: A1; warmtegeleidingscoëfficiënt: 0.035; kortstondige waterabsorptie: WS; langdurige waterabsorptie: WL(P); waterdamptransmissie / waterdampdiffusie weerstandsfactor: MU1; luchtstroomweerstand: Afr5; DoP nummer (Declaration of performance): G4220LPCPR; NLRS_C_content_creator: Knauf Insulation; NLRS_C_content_versie: V1.0; diktebereik: 20 - 370; diktetolerantie: T2; pak (m2): 8.82; pakken / pallet: 24; pallet (m2): 211.58
Classification: 27 Daken (Uniformat); Material: Knauf Insulation_Ecose® glaswol_naturoll 035; Knauf Insulation_Ecose® glaswol_naturoll 035 90 mm
Pset_SlabCommon - PitchAngle: 0 deg
Pset_Roof Schedule Naturoll 035 LOD400 - Type: Basic Roof: NLRS_27_RO_Naturoll 035_90x580x7600mm

# IfcSlab: Floor:NLRS_23_FL_Naturoll 035_100x580x7400mm, Floor:NLRS_23_FL_Naturoll 035_100x580x7400mm:34991
In: Begane grond
Type - PredefinedType: FLOOR; Material: Knauf Insulation_Ecose® glaswol_naturoll 035 100 mm
Type - Pset_ElementShading - Roughness: 304.8 mm
Type - Pset_ManufacturerTypeInformation - Manufacturer: Knauf Insulation B.V.
Type - Pset_ProductRequirements - Category: Floors
Type - Pset_QuantityTakeOff - Reference: Floor:NLRS_23_FL_Naturoll 035_100x580x7400mm
Type - Pset_ReinforcementBarPitchOfSlab - Description: Naturoll 035 - 100mm; Reference: Floor:NLRS_23_FL_Naturoll 035_100x580x7400mm
Type - Pset_SlabCommon - IsExternal: no; Reference: Floor:NLRS_23_FL_Naturoll 035_100x580x7400mm; ThermalTransmittance: 0.35 kg/K/s3
Type - Pset_Floor Schedule Naturoll 035 LOD400 - rollen / pak: 2; Assembly Code: 23; Type Image: Raster image: Naturoll 035 .jpg (2); Model: Naturoll 035 is een onbeklede glaswoldeken met ECOSE® Technology; Manufacturer: Knauf Insulation B.V.; URL: www.knaufinsulation.nl; Description: Naturoll 035 - 100mm; phone: +31(0)162-421245; email: customerservice.nl@knaufinsulation.com; product URL: https://www.knaufinsulation.nl/producten-van-knauf-insulation/naturoll-035; warmteweerstand: 2.85; NLRS_C_Code_Brandklasse: A1; warmtegeleidingscoëfficiënt: 0.035; kortstondige waterabsorptie: WS; langdurige waterabsorptie: WL(P); waterdamptransmissie / waterdampdiffusie weerstandsfactor: MU1; luchtstroomweerstand: Afr5; DoP nummer (Declaration of performance): G4220LPCPR; NLRS_C_content_creator: Knauf Insulation; NLRS_C_content_versie: V1.0; diktebereik: 20 - 370; diktetolerantie: T2; pak (m2): 8.58; pakken / pallet: 24; pallet (m2): 206.02
Classification: 23 Vloeren (Uniformat)
Pset_SlabCommon - LoadBearing: no; PitchAngle: 0 deg
Pset_Floor Schedule Naturoll 035 LOD400 - Type: Floor: NLRS_23_FL_Naturoll 035_100x580x7400mm

# IfcSlab: Floor:NLRS_23_FL_Naturoll 035_120x380x6200mm, Floor:NLRS_23_FL_Naturoll 035_120x380x6200mm:35013
In: Begane grond
Type - PredefinedType: FLOOR; Material: Knauf Insulation_Ecose® glaswol_naturoll 035 120 mm
Type - Pset_ElementShading - Roughness: 304.8 mm
Type - Pset_ManufacturerTypeInformation - Manufacturer: Knauf Insulation B.V.
Type - Pset_ProductRequirements - Category: Floors
Type - Pset_QuantityTakeOff - Reference: Floor:NLRS_23_FL_Naturoll 035_120x380x6200mm
Type - Pset_ReinforcementBarPitchOfSlab - Description: Naturoll 035 - 120mm; Reference: Floor:NLRS_23_FL_Naturoll 035_120x380x6200mm
Type - Pset_SlabCommon - IsExternal: no; Reference: Floor:NLRS_23_FL_Naturoll 035_120x380x6200mm; ThermalTransmittance: 0.291667 kg/K/s3
Type - Pset_Floor Schedule Naturoll 035 LOD400 - rollen / pak: 3; Assembly Code: 23; Type Image: Raster image: Naturoll 035 .jpg (2); Model: Naturoll 035 is een onbeklede glaswoldeken met ECOSE® Technology; Manufacturer: Knauf Insulation B.V.; URL: www.knaufinsulation.nl; Description: Naturoll 035 - 120mm; phone: +31(0)162-421245; email: customerservice.nl@knaufinsulation.com; product URL: https://www.knaufinsulation.nl/producten-van-knauf-insulation/naturoll-035; warmteweerstand: 3.4; NLRS_C_Code_Brandklasse: A1; warmtegeleidingscoëfficiënt: 0.035; kortstondige waterabsorptie: WS; langdurige waterabsorptie: WL(P); waterdamptransmissie / waterdampdiffusie weerstandsfactor: MU1; luchtstroomweerstand: Afr5; DoP nummer (Declaration of performance): G4220LPCPR; NLRS_C_content_creator: Knauf Insulation; NLRS_C_content_versie: V1.0; diktebereik: 20 - 370; diktetolerantie: T2; pak (m2): 7.07; pakken / pallet: 24; pallet (m2): 169.63
Classification: 23 Vloeren (Uniformat)
Pset_SlabCommon - LoadBearing: no; PitchAngle: 0 deg
Pset_Floor Schedule Naturoll 035 LOD400 - Type: Floor: NLRS_23_FL_Naturoll 035_120x380x6200mm

# IfcSlab: Floor:NLRS_23_FL_Naturoll 035_120x580x6200mm, Floor:NLRS_23_FL_Naturoll 035_120x580x6200mm:35035
In: Begane grond
Type - PredefinedType: FLOOR; Material: Knauf Insulation_Ecose® glaswol_naturoll 035 120 mm
Type - Pset_ElementShading - Roughness: 304.8 mm
Type - Pset_ManufacturerTypeInformation - Manufacturer: Knauf Insulation B.V.
Type - Pset_ProductRequirements - Category: Floors
Type - Pset_QuantityTakeOff - Reference: Floor:NLRS_23_FL_Naturoll 035_120x580x6200mm
Type - Pset_ReinforcementBarPitchOfSlab - Description: Naturoll 035 - 120mm; Reference: Floor:NLRS_23_FL_Naturoll 035_120x580x6200mm
Type - Pset_SlabCommon - IsExternal: no; Reference: Floor:NLRS_23_FL_Naturoll 035_120x580x6200mm; ThermalTransmittance: 0.291667 kg/K/s3
Type - Pset_Floor Schedule Naturoll 035 LOD400 - rollen / pak: 2; Assembly Code: 23; Type Image: Raster image: Naturoll 035 .jpg (2); Model: Naturoll 035 is een onbeklede glaswoldeken met ECOSE® Technology; Manufacturer: Knauf Insulation B.V.; URL: www.knaufinsulation.nl; Description: Naturoll 035 - 120mm; phone: +31(0)162-421245; email: customerservice.nl@knaufinsulation.com; product URL: https://www.knaufinsulation.nl/producten-van-knauf-insulation/naturoll-035; warmteweerstand: 3.4; NLRS_C_Code_Brandklasse: A1; warmtegeleidingscoëfficiënt: 0.035; kortstondige waterabsorptie: WS; langdurige waterabsorptie: WL(P); waterdamptransmissie / waterdampdiffusie weerstandsfactor: MU1; luchtstroomweerstand: Afr5; DoP nummer (Declaration of performance): G4220LPCPR; NLRS_C_content_creator: Knauf Insulation; NLRS_C_content_versie: V1.0; diktebereik: 20 - 370; diktetolerantie: T2; pak (m2): 7.19; pakken / pallet: 24; pallet (m2): 172.61
Classification: 23 Vloeren (Uniformat)
Pset_SlabCommon - LoadBearing: no; PitchAngle: 0 deg
Pset_Floor Schedule Naturoll 035 LOD400 - Type: Floor: NLRS_23_FL_Naturoll 035_120x580x6200mm

# IfcSlab: Floor:NLRS_23_FL_Naturoll 035_130x590x5500mm, Floor:NLRS_23_FL_Naturoll 035_130x590x5500mm:35057
In: Begane grond
Type - PredefinedType: FLOOR; Material: Knauf Insulation_Ecose® glaswol_naturoll 035 130 mm
Type - Pset_ElementShading - Roughness: 304.8 mm
Type - Pset_ManufacturerTypeInformation - Manufacturer: Knauf Insulation B.V.
Type - Pset_ProductRequirements - Category: Floors
Type - Pset_QuantityTakeOff - Reference: Floor:NLRS_23_FL_Naturoll 035_130x590x5500mm
Type - Pset_ReinforcementBarPitchOfSlab - Description: Naturoll 035 - 130mm; Reference: Floor:NLRS_23_FL_Naturoll 035_130x590x5500mm
Type - Pset_SlabCommon - IsExternal: no; Reference: Floor:NLRS_23_FL_Naturoll 035_130x590x5500mm; ThermalTransmittance: 0.269231 kg/K/s3
Type - Pset_Floor Schedule Naturoll 035 LOD400 - rollen / pak: 2; Assembly Code: 23; Type Image: Raster image: Naturoll 035 .jpg (2); Model: Naturoll 035 is een onbeklede glaswoldeken met ECOSE® Technology; Manufacturer: Knauf Insulation B.V.; URL: www.knaufinsulation.nl; Description: Naturoll 035 - 130mm; phone: +31(0)162-421245; email: customerservice.nl@knaufinsulation.com; product URL: https://www.knaufinsulation.nl/producten-van-knauf-insulation/naturoll-035; warmteweerstand: 3.7; NLRS_C_Code_Brandklasse: A1; warmtegeleidingscoëfficiënt: 0.035; kortstondige waterabsorptie: WS; langdurige waterabsorptie: WL(P); waterdamptransmissie / waterdampdiffusie weerstandsfactor: MU1; luchtstroomweerstand: Afr5; DoP nummer (Declaration of performance): G4220LPCPR; NLRS_C_content_creator: Knauf Insulation; NLRS_C_content_versie: V1.0; diktebereik: 20 - 370; diktetolerantie: T2; pak (m2): 6.49; pakken / pallet: 24; pallet (m2): 155.76
Classification: 23 Vloeren (Uniformat)
Pset_SlabCommon - LoadBearing: no; PitchAngle: 0 deg
Pset_Floor Schedule Naturoll 035 LOD400 - Type: Floor: NLRS_23_FL_Naturoll 035_130x590x5500mm

# IfcSlab: Floor:NLRS_23_FL_Naturoll 035_135x590x5300mm, Floor:NLRS_23_FL_Naturoll 035_135x590x5300mm:42288
In: Begane grond
Type - PredefinedType: FLOOR; Material: Knauf Insulation_Ecose® glaswol_naturoll 035 135 mm
Type - Pset_ElementShading - Roughness: 304.8 mm
Type - Pset_ManufacturerTypeInformation - Manufacturer: Knauf Insulation B.V.
Type - Pset_ProductRequirements - Category: Floors
Type - Pset_QuantityTakeOff - Reference: Floor:NLRS_23_FL_Naturoll 035_135x590x5300mm
Type - Pset_ReinforcementBarPitchOfSlab - Description: Naturoll 035 - 135mm; Reference: Floor:NLRS_23_FL_Naturoll 035_135x590x5300mm
Type - Pset_SlabCommon - IsExternal: no; Reference: Floor:NLRS_23_FL_Naturoll 035_135x590x5300mm; ThermalTransmittance: 0.259259 kg/K/s3
Type - Pset_Floor Schedule Naturoll 035 LOD400 - rollen / pak: 2; Assembly Code: 23; Type Image: Raster image: Naturoll 035 .jpg (2); Model: Naturoll 035 is een onbeklede glaswoldeken met ECOSE® Technology; Manufacturer: Knauf Insulation B.V.; URL: www.knaufinsulation.nl; Description: Naturoll 035 - 135mm; phone: +31(0)162-421245; email: customerservice.nl@knaufinsulation.com; product URL: https://www.knaufinsulation.nl/producten-van-knauf-insulation/naturoll-035; warmteweerstand: 3.85; NLRS_C_Code_Brandklasse: A1; warmtegeleidingscoëfficiënt: 0.035; kortstondige waterabsorptie: WS; langdurige waterabsorptie: WL(P); waterdamptransmissie / waterdampdiffusie weerstandsfactor: MU1; luchtstroomweerstand: Afr5; DoP nummer (Declaration of performance): G4220LPCPR; NLRS_C_content_creator: Knauf Insulation; NLRS_C_content_versie: V1.0; diktebereik: 20 - 370; diktetolerantie: T2; pak (m2): 6.25; pakken / pallet: 24; pallet (m2): 150.1
Classification: 23 Vloeren (Uniformat)
Pset_SlabCommon - LoadBearing: no; PitchAngle: 0 deg
Pset_Floor Schedule Naturoll 035 LOD400 - Type: Floor: NLRS_23_FL_Naturoll 035_135x590x5300mm

# IfcSlab: Floor:NLRS_23_FL_Naturoll 035_140x380x5300mm, Floor:NLRS_23_FL_Naturoll 035_140x380x5300mm:35107
In: Begane grond
Type - PredefinedType: FLOOR; Material: Knauf Insulation_Ecose® glaswol_naturoll 035 140 mm
Type - Pset_ElementShading - Roughness: 304.8 mm
Type - Pset_ManufacturerTypeInformation - Manufacturer: Knauf Insulation B.V.
Type - Pset_ProductRequirements - Category: Floors
Type - Pset_QuantityTakeOff - Reference: Floor:NLRS_23_FL_Naturoll 035_140x380x5300mm
Type - Pset_ReinforcementBarPitchOfSlab - Description: Naturoll 035 - 140mm; Reference: Floor:NLRS_23_FL_Naturoll 035_140x380x5300mm
Type - Pset_SlabCommon - IsExternal: no; Reference: Floor:NLRS_23_FL_Naturoll 035_140x380x5300mm; ThermalTransmittance: 0.25 kg/K/s3
Type - Pset_Floor Schedule Naturoll 035 LOD400 - rollen / pak: 3; warmteweerstand: 4; Assembly Code: 23; Type Image: Raster image: Naturoll 035 .jpg (2); Model: Naturoll 035 is een onbeklede glaswoldeken met ECOSE® Technology; Manufacturer: Knauf Insulation B.V.; URL: www.knaufinsulation.nl; Description: Naturoll 035 - 140mm; phone: +31(0)162-421245; email: customerservice.nl@knaufinsulation.com; product URL: https://www.knaufinsulation.nl/producten-van-knauf-insulation/naturoll-035; NLRS_C_Code_Brandklasse: A1; warmtegeleidingscoëfficiënt: 0.035; kortstondige waterabsorptie: WS; langdurige waterabsorptie: WL(P); waterdamptransmissie / waterdampdiffusie weerstandsfactor: MU1; luchtstroomweerstand: Afr5; DoP nummer (Declaration of performance): G4220LPCPR; NLRS_C_content_creator: Knauf Insulation; NLRS_C_content_versie: V1.0; diktebereik: 20 - 370; diktetolerantie: T2; pak (m2): 6.04; pakken / pallet: 24; pallet (m2): 145.01
Classification: 23 Vloeren (Uniformat)
Pset_SlabCommon - LoadBearing: no; PitchAngle: 0 deg
Pset_Floor Schedule Naturoll 035 LOD400 - Type: Floor: NLRS_23_FL_Naturoll 035_140x380x5300mm

# IfcSlab: Floor:NLRS_23_FL_Naturoll 035_140x580x5300mm, Floor:NLRS_23_FL_Naturoll 035_140x580x5300mm:35127
In: Begane grond
Type - PredefinedType: FLOOR; Material: Knauf Insulation_Ecose® glaswol_naturoll 035 140 mm
Type - Pset_ElementShading - Roughness: 304.8 mm
Type - Pset_ManufacturerTypeInformation - Manufacturer: Knauf Insulation B.V.
Type - Pset_ProductRequirements - Category: Floors
Type - Pset_QuantityTakeOff - Reference: Floor:NLRS_23_FL_Naturoll 035_140x580x5300mm
Type - Pset_ReinforcementBarPitchOfSlab - Description: Naturoll 035 - 140mm; Reference: Floor:NLRS_23_FL_Naturoll 035_140x580x5300mm
Type - Pset_SlabCommon - IsExternal: no; ThermalTransmittance: 0.25 kg/K/s3; Reference: Floor:NLRS_23_FL_Naturoll 035_140x580x5300mm
Type - Pset_Floor Schedule Naturoll 035 LOD400 - rollen / pak: 2; warmteweerstand: 4; Assembly Code: 23; Type Image: Raster image: Naturoll 035 .jpg (2); Model: Naturoll 035 is een onbeklede glaswoldeken met ECOSE® Technology; Manufacturer: Knauf Insulation B.V.; URL: www.knaufinsulation.nl; Description: Naturoll 035 - 140mm; phone: +31(0)162-421245; email: customerservice.nl@knaufinsulation.com; product URL: https://www.knaufinsulation.nl/producten-van-knauf-insulation/naturoll-035; NLRS_C_Code_Brandklasse: A1; warmtegeleidingscoëfficiënt: 0.035; kortstondige waterabsorptie: WS; langdurige waterabsorptie: WL(P); waterdamptransmissie / waterdampdiffusie weerstandsfactor: MU1; luchtstroomweerstand: Afr5; DoP nummer (Declaration of performance): G4220LPCPR; NLRS_C_content_creator: Knauf Insulation; NLRS_C_content_versie: V1.0; diktebereik: 20 - 370; diktetolerantie: T2; pak (m2): 6.15; pakken / pallet: 24; pallet (m2): 147.55
Classification: 23 Vloeren (Uniformat)
Pset_SlabCommon - LoadBearing: no; PitchAngle: 0 deg
Pset_Floor Schedule Naturoll 035 LOD400 - Type: Floor: NLRS_23_FL_Naturoll 035_140x580x5300mm

# IfcSlab: Floor:NLRS_23_FL_Naturoll 035_170x380x4350mm, Floor:NLRS_23_FL_Naturoll 035_170x380x4350mm:35167
In: Begane grond
Type - PredefinedType: FLOOR; Material: Knauf Insulation_Ecose® glaswol_naturoll 035 170 mm
Type - Pset_ElementShading - Roughness: 304.8 mm
Type - Pset_ManufacturerTypeInformation - Manufacturer: Knauf Insulation B.V.
Type - Pset_ProductRequirements - Category: Floors
Type - Pset_QuantityTakeOff - Reference: Floor:NLRS_23_FL_Naturoll 035_170x380x4350mm
Type - Pset_ReinforcementBarPitchOfSlab - Description: Naturoll 035 - 170mm; Reference: Floor:NLRS_23_FL_Naturoll 035_170x380x4350mm
Type - Pset_SlabCommon - IsExternal: no; Reference: Floor:NLRS_23_FL_Naturoll 035_170x380x4350mm; ThermalTransmittance: 0.205882 kg/K/s3
Type - Pset_Floor Schedule Naturoll 035 LOD400 - rollen / pak: 3; Assembly Code: 23; Type Image: Raster image: Naturoll 035 .jpg (2); Model: Naturoll 035 is een onbeklede glaswoldeken met ECOSE® Technology; Manufacturer: Knauf Insulation B.V.; URL: www.knaufinsulation.nl; Description: Naturoll 035 - 170mm; phone: +31(0)162-421245; email: customerservice.nl@knaufinsulation.com; product URL: https://www.knaufinsulation.nl/producten-van-knauf-insulation/naturoll-035; warmteweerstand: 4.85; NLRS_C_Code_Brandklasse: A1; warmtegeleidingscoëfficiënt: 0.035; kortstondige waterabsorptie: WS; langdurige waterabsorptie: WL(P); waterdamptransmissie / waterdampdiffusie weerstandsfactor: MU1; luchtstroomweerstand: Afr5; DoP nummer (Declaration of performance): G4220LPCPR; NLRS_C_content_creator: Knauf Insulation; NLRS_C_content_versie: V1.0; diktebereik: 20 - 370; diktetolerantie: T2; pak (m2): 4.96; pakken / pallet: 24; pallet (m2): 119.02
Classification: 23 Vloeren (Uniformat)
Pset_SlabCommon - LoadBearing: no; PitchAngle: 0 deg
Pset_Floor Schedule Naturoll 035 LOD400 - Type: Floor: NLRS_23_FL_Naturoll 035_170x380x4350mm

# IfcSlab: Floor:NLRS_23_FL_Naturoll 035_170x580x4350mm, Floor:NLRS_23_FL_Naturoll 035_170x580x4350mm:35187
In: Begane grond
Type - PredefinedType: FLOOR; Material: Knauf Insulation_Ecose® glaswol_naturoll 035 170 mm
Type - Pset_ElementShading - Roughness: 304.8 mm
Type - Pset_ManufacturerTypeInformation - Manufacturer: Knauf Insulation B.V.
Type - Pset_ProductRequirements - Category: Floors
Type - Pset_QuantityTakeOff - Reference: Floor:NLRS_23_FL_Naturoll 035_170x580x4350mm
Type - Pset_ReinforcementBarPitchOfSlab - Description: Naturoll 035 - 170mm; Reference: Floor:NLRS_23_FL_Naturoll 035_170x580x4350mm
Type - Pset_SlabCommon - IsExternal: no; Reference: Floor:NLRS_23_FL_Naturoll 035_170x580x4350mm; ThermalTransmittance: 0.205882 kg/K/s3
Type - Pset_Floor Schedule Naturoll 035 LOD400 - rollen / pak: 2; Assembly Code: 23; Type Image: Raster image: Naturoll 035 .jpg (2); Model: Naturoll 035 is een onbeklede glaswoldeken met ECOSE® Technology; Manufacturer: Knauf Insulation B.V.; URL: www.knaufinsulation.nl; Description: Naturoll 035 - 170mm; phone: +31(0)162-421245; email: customerservice.nl@knaufinsulation.com; product URL: https://www.knaufinsulation.nl/producten-van-knauf-insulation/naturoll-035; warmteweerstand: 4.85; NLRS_C_Code_Brandklasse: A1; warmtegeleidingscoëfficiënt: 0.035; kortstondige waterabsorptie: WS; langdurige waterabsorptie: WL(P); waterdamptransmissie / waterdampdiffusie weerstandsfactor: MU1; luchtstroomweerstand: Afr5; DoP nummer (Declaration of performance): G4220LPCPR; NLRS_C_content_creator: Knauf Insulation; NLRS_C_content_versie: V1.0; diktebereik: 20 - 370; diktetolerantie: T2; pak (m2): 5.05; pakken / pallet: 24; pallet (m2): 121.1
Classification: 23 Vloeren (Uniformat)
Pset_SlabCommon - LoadBearing: no; PitchAngle: 0 deg
Pset_Floor Schedule Naturoll 035 LOD400 - Type: Floor: NLRS_23_FL_Naturoll 035_170x580x4350mm

# IfcSlab: Floor:NLRS_23_FL_Naturoll 035_185x380x4000mm, Floor:NLRS_23_FL_Naturoll 035_185x380x4000mm:35207
In: Begane grond
Type - PredefinedType: FLOOR; Material: Knauf Insulation_Ecose® glaswol_naturoll 035 185 mm
Type - Pset_ElementShading - Roughness: 304.8 mm
Type - Pset_ManufacturerTypeInformation - Manufacturer: Knauf Insulation B.V.
Type - Pset_ProductRequirements - Category: Floors
Type - Pset_QuantityTakeOff - Reference: Floor:NLRS_23_FL_Naturoll 035_185x380x4000mm
Type - Pset_ReinforcementBarPitchOfSlab - Description: Naturoll 035 - 185mm; Reference: Floor:NLRS_23_FL_Naturoll 035_185x380x4000mm
Type - Pset_SlabCommon - IsExternal: no; Reference: Floor:NLRS_23_FL_Naturoll 035_185x380x4000mm; ThermalTransmittance: 0.189189 kg/K/s3
Type - Pset_Floor Schedule Naturoll 035 LOD400 - rollen / pak: 3; Assembly Code: 23; Type Image: Raster image: Naturoll 035 .jpg (2); Model: Naturoll 035 is een onbeklede glaswoldeken met ECOSE® Technology; Manufacturer: Knauf Insulation B.V.; URL: www.knaufinsulation.nl; Description: Naturoll 035 - 185mm; phone: +31(0)162-421245; email: customerservice.nl@knaufinsulation.com; product URL: https://www.knaufinsulation.nl/producten-van-knauf-insulation/naturoll-035; warmteweerstand: 5.25; NLRS_C_Code_Brandklasse: A1; warmtegeleidingscoëfficiënt: 0.035; kortstondige waterabsorptie: WS; langdurige waterabsorptie: WL(P); waterdamptransmissie / waterdampdiffusie weerstandsfactor: MU1; luchtstroomweerstand: Afr5; DoP nummer (Declaration of performance): G4220LPCPR; NLRS_C_content_creator: Knauf Insulation; NLRS_C_content_versie: V1.0; diktebereik: 20 - 370; diktetolerantie: T2; pak (m2): 4.56; pakken / pallet: 24; pallet (m2): 109.44
Classification: 23 Vloeren (Uniformat)
Pset_SlabCommon - LoadBearing: no; PitchAngle: 0 deg
Pset_Floor Schedule Naturoll 035 LOD400 - Type: Floor: NLRS_23_FL_Naturoll 035_185x380x4000mm

# IfcSlab: Floor:NLRS_23_FL_Naturoll 035_185x580x4000mm, Floor:NLRS_23_FL_Naturoll 035_185x580x4000mm:37495
In: Begane grond
Type - PredefinedType: FLOOR; Material: Knauf Insulation_Ecose® glaswol_naturoll 035 185 mm
Type - Pset_ElementShading - Roughness: 304.8 mm
Type - Pset_ManufacturerTypeInformation - Manufacturer: Knauf Insulation B.V.
Type - Pset_ProductRequirements - Category: Floors
Type - Pset_QuantityTakeOff - Reference: Floor:NLRS_23_FL_Naturoll 035_185x580x4000mm
Type - Pset_ReinforcementBarPitchOfSlab - Description: Naturoll 035 - 185mm; Reference: Floor:NLRS_23_FL_Naturoll 035_185x580x4000mm
Type - Pset_SlabCommon - IsExternal: no; Reference: Floor:NLRS_23_FL_Naturoll 035_185x580x4000mm; ThermalTransmittance: 0.189189 kg/K/s3
Type - Pset_Floor Schedule Naturoll 035 LOD400 - rollen / pak: 2; Assembly Code: 23; Type Image: Raster image: Naturoll 035 .jpg (2); Model: Naturoll 035 is een onbeklede glaswoldeken met ECOSE® Technology; Manufacturer: Knauf Insulation B.V.; URL: www.knaufinsulation.nl; Description: Naturoll 035 - 185mm; phone: +31(0)162-421245; email: customerservice.nl@knaufinsulation.com; product URL: https://www.knaufinsulation.nl/producten-van-knauf-insulation/naturoll-035; warmteweerstand: 5.25; NLRS_C_Code_Brandklasse: A1; warmtegeleidingscoëfficiënt: 0.035; kortstondige waterabsorptie: WS; langdurige waterabsorptie: WL(P); waterdamptransmissie / waterdampdiffusie weerstandsfactor: MU1; luchtstroomweerstand: Afr5; DoP nummer (Declaration of performance): G4220LPCPR; NLRS_C_content_creator: Knauf Insulation; NLRS_C_content_versie: V1.0; diktebereik: 20 - 370; diktetolerantie: T2; pak (m2): 4.64; pakken / pallet: 24; pallet (m2): 111.36
Classification: 23 Vloeren (Uniformat)
Pset_SlabCommon - LoadBearing: no; PitchAngle: 0 deg
Pset_Floor Schedule Naturoll 035 LOD400 - Type: Floor: NLRS_23_FL_Naturoll 035_185x580x4000mm

# IfcSlab: Floor:NLRS_23_FL_Naturoll 035_200x580x3700mm, Floor:NLRS_23_FL_Naturoll 035_200x580x3700mm:35395
In: Begane grond
Type - PredefinedType: FLOOR; Material: Knauf Insulation_Ecose® glaswol_naturoll 035 200 mm
Type - Pset_ElementShading - Roughness: 304.8 mm
Type - Pset_ManufacturerTypeInformation - Manufacturer: Knauf Insulation B.V.
Type - Pset_ProductRequirements - Category: Floors
Type - Pset_QuantityTakeOff - Reference: Floor:NLRS_23_FL_Naturoll 035_200x580x3700mm
Type - Pset_ReinforcementBarPitchOfSlab - Description: Naturoll 035 - 200mm; Reference: Floor:NLRS_23_FL_Naturoll 035_200x580x3700mm
Type - Pset_SlabCommon - IsExternal: no; Reference: Floor:NLRS_23_FL_Naturoll 035_200x580x3700mm; ThermalTransmittance: 0.175 kg/K/s3
Type - Pset_Floor Schedule Naturoll 035 LOD400 - rollen / pak: 2; Assembly Code: 23; Type Image: Raster image: Naturoll 035 .jpg (2); Model: Naturoll 035 is een onbeklede glaswoldeken met ECOSE® Technology; Manufacturer: Knauf Insulation B.V.; URL: www.knaufinsulation.nl; Description: Naturoll 035 - 200mm; phone: +31(0)162-421245; email: customerservice.nl@knaufinsulation.com; product URL: https://www.knaufinsulation.nl/producten-van-knauf-insulation/naturoll-035; warmteweerstand: 5.7; NLRS_C_Code_Brandklasse: A1; warmtegeleidingscoëfficiënt: 0.035; kortstondige waterabsorptie: WS; langdurige waterabsorptie: WL(P); waterdamptransmissie / waterdampdiffusie weerstandsfactor: MU1; luchtstroomweerstand: Afr5; DoP nummer (Declaration of performance): G4220LPCPR; NLRS_C_content_creator: Knauf Insulation; NLRS_C_content_versie: V1.0; diktebereik: 20 - 370; diktetolerantie: T2; pak (m2): 4.29; pakken / pallet: 24; pallet (m2): 103.01
Classification: 23 Vloeren (Uniformat)
Pset_SlabCommon - LoadBearing: no; PitchAngle: 0 deg
Pset_Floor Schedule Naturoll 035 LOD400 - Type: Floor: NLRS_23_FL_Naturoll 035_200x580x3700mm

# IfcSlab: Floor:NLRS_23_FL_Naturoll 035_220x380x3400mm, Floor:NLRS_23_FL_Naturoll 035_220x380x3400mm:35414
In: Begane grond
Type - PredefinedType: FLOOR; Material: Knauf Insulation_Ecose® glaswol_naturoll 035 220 mm
Type - Pset_ElementShading - Roughness: 304.8 mm
Type - Pset_ManufacturerTypeInformation - Manufacturer: Knauf Insulation B.V.
Type - Pset_ProductRequirements - Category: Floors
Type - Pset_QuantityTakeOff - Reference: Floor:NLRS_23_FL_Naturoll 035_220x380x3400mm
Type - Pset_ReinforcementBarPitchOfSlab - Description: Naturoll 035 - 220mm; Reference: Floor:NLRS_23_FL_Naturoll 035_220x380x3400mm
Type - Pset_SlabCommon - IsExternal: no; Reference: Floor:NLRS_23_FL_Naturoll 035_220x380x3400mm; ThermalTransmittance: 0.159091 kg/K/s3
Type - Pset_Floor Schedule Naturoll 035 LOD400 - rollen / pak: 3; Assembly Code: 23; Type Image: Raster image: Naturoll 035 .jpg (2); Model: Naturoll 035 is een onbeklede glaswoldeken met ECOSE® Technology; Manufacturer: Knauf Insulation B.V.; URL: www.knaufinsulation.nl; Description: Naturoll 035 - 220mm; phone: +31(0)162-421245; email: customerservice.nl@knaufinsulation.com; product URL: https://www.knaufinsulation.nl/producten-van-knauf-insulation/naturoll-035; warmteweerstand: 6.25; NLRS_C_Code_Brandklasse: A1; warmtegeleidingscoëfficiënt: 0.035; kortstondige waterabsorptie: WS; langdurige waterabsorptie: WL(P); waterdamptransmissie / waterdampdiffusie weerstandsfactor: MU1; luchtstroomweerstand: Afr5; DoP nummer (Declaration of performance): G4220LPCPR; NLRS_C_content_creator: Knauf Insulation; NLRS_C_content_versie: V1.0; diktebereik: 20 - 370; diktetolerantie: T2; pak (m2): 3.88; pakken / pallet: 24; pallet (m2): 93.02
Classification: 23 Vloeren (Uniformat)
Pset_SlabCommon - LoadBearing: no; PitchAngle: 0 deg
Pset_Floor Schedule Naturoll 035 LOD400 - Type: Floor: NLRS_23_FL_Naturoll 035_220x380x3400mm

# IfcSlab: Floor:NLRS_23_FL_Naturoll 035_220x580x3400mm, Floor:NLRS_23_FL_Naturoll 035_220x580x3400mm:35433
In: Begane grond
Type - PredefinedType: FLOOR; Material: Knauf Insulation_Ecose® glaswol_naturoll 035 220 mm
Type - Pset_ElementShading - Roughness: 304.8 mm
Type - Pset_ManufacturerTypeInformation - Manufacturer: Knauf Insulation B.V.
Type - Pset_ProductRequirements - Category: Floors
Type - Pset_QuantityTakeOff - Reference: Floor:NLRS_23_FL_Naturoll 035_220x580x3400mm
Type - Pset_ReinforcementBarPitchOfSlab - Description: Naturoll 035 - 220mm; Reference: Floor:NLRS_23_FL_Naturoll 035_220x580x3400mm
Type - Pset_SlabCommon - IsExternal: no; Reference: Floor:NLRS_23_FL_Naturoll 035_220x580x3400mm; ThermalTransmittance: 0.159091 kg/K/s3
Type - Pset_Floor Schedule Naturoll 035 LOD400 - rollen / pak: 2; Assembly Code: 23; Type Image: Raster image: Naturoll 035 .jpg (2); Model: Naturoll 035 is een onbeklede glaswoldeken met ECOSE® Technology; Manufacturer: Knauf Insulation B.V.; URL: www.knaufinsulation.nl; Description: Naturoll 035 - 220mm; phone: +31(0)162-421245; email: customerservice.nl@knaufinsulation.com; product URL: https://www.knaufinsulation.nl/producten-van-knauf-insulation/naturoll-035; warmteweerstand: 6.25; NLRS_C_Code_Brandklasse: A1; warmtegeleidingscoëfficiënt: 0.035; kortstondige waterabsorptie: WS; langdurige waterabsorptie: WL(P); waterdamptransmissie / waterdampdiffusie weerstandsfactor: MU1; luchtstroomweerstand: Afr5; DoP nummer (Declaration of performance): G4220LPCPR; NLRS_C_content_creator: Knauf Insulation; NLRS_C_content_versie: V1.0; diktebereik: 20 - 370; diktetolerantie: T2; pak (m2): 3.94; pakken / pallet: 24; pallet (m2): 94.66
Classification: 23 Vloeren (Uniformat)
Pset_SlabCommon - LoadBearing: no; PitchAngle: 0 deg
Pset_Floor Schedule Naturoll 035 LOD400 - Type: Floor: NLRS_23_FL_Naturoll 035_220x580x3400mm

# IfcSlab: Floor:NLRS_23_FL_Naturoll 035_235x580x3100mm, Floor:NLRS_23_FL_Naturoll 035_235x580x3100mm:35452
In: Begane grond
Type - PredefinedType: FLOOR; Material: Knauf Insulation_Ecose® glaswol_naturoll 035 235 mm
Type - Pset_ElementShading - Roughness: 304.8 mm
Type - Pset_ManufacturerTypeInformation - Manufacturer: Knauf Insulation B.V.
Type - Pset_ProductRequirements - Category: Floors
Type - Pset_QuantityTakeOff - Reference: Floor:NLRS_23_FL_Naturoll 035_235x580x3100mm
Type - Pset_ReinforcementBarPitchOfSlab - Description: Naturoll 035 - 235mm; Reference: Floor:NLRS_23_FL_Naturoll 035_235x580x3100mm
Type - Pset_SlabCommon - IsExternal: no; Reference: Floor:NLRS_23_FL_Naturoll 035_235x580x3100mm; ThermalTransmittance: 0.148936 kg/K/s3
Type - Pset_Floor Schedule Naturoll 035 LOD400 - rollen / pak: 2; Assembly Code: 23; Type Image: Raster image: Naturoll 035 .jpg (2); Model: Naturoll 035 is een onbeklede glaswoldeken met ECOSE® Technology; Manufacturer: Knauf Insulation B.V.; URL: www.knaufinsulation.nl; Description: Naturoll 035 - 235mm; phone: +31(0)162-421245; email: customerservice.nl@knaufinsulation.com; product URL: https://www.knaufinsulation.nl/producten-van-knauf-insulation/naturoll-035; warmteweerstand: 6.7; NLRS_C_Code_Brandklasse: A1; warmtegeleidingscoëfficiënt: 0.035; kortstondige waterabsorptie: WS; langdurige waterabsorptie: WL(P); waterdamptransmissie / waterdampdiffusie weerstandsfactor: MU1; luchtstroomweerstand: Afr5; DoP nummer (Declaration of performance): G4220LPCPR; NLRS_C_content_creator: Knauf Insulation; NLRS_C_content_versie: V1.0; diktebereik: 20 - 370; diktetolerantie: T2; pak (m2): 3.6; pakken / pallet: 24; pallet (m2): 86.3
Classification: 23 Vloeren (Uniformat)
Pset_SlabCommon - LoadBearing: no; PitchAngle: 0 deg
Pset_Floor Schedule Naturoll 035 LOD400 - Type: Floor: NLRS_23_FL_Naturoll 035_235x580x3100mm

# IfcSlab: Floor:NLRS_23_FL_Naturoll 035_240x580x3100mm, Floor:NLRS_23_FL_Naturoll 035_240x580x3100mm:35471
In: Begane grond
Type - PredefinedType: FLOOR; Material: Knauf Insulation_Ecose® glaswol_naturoll 035 240 mm
Type - Pset_ElementShading - Roughness: 304.8 mm
Type - Pset_ManufacturerTypeInformation - Manufacturer: Knauf Insulation B.V.
Type - Pset_ProductRequirements - Category: Floors
Type - Pset_QuantityTakeOff - Reference: Floor:NLRS_23_FL_Naturoll 035_240x580x3100mm
Type - Pset_ReinforcementBarPitchOfSlab - Description: Naturoll 035 - 240mm; Reference: Floor:NLRS_23_FL_Naturoll 035_240x580x3100mm
Type - Pset_SlabCommon - IsExternal: no; Reference: Floor:NLRS_23_FL_Naturoll 035_240x580x3100mm; ThermalTransmittance: 0.145833 kg/K/s3
Type - Pset_Floor Schedule Naturoll 035 LOD400 - rollen / pak: 2; Assembly Code: 23; Type Image: Raster image: Naturoll 035 .jpg (2); Model: Naturoll 035 is een onbeklede glaswoldeken met ECOSE® Technology; Manufacturer: Knauf Insulation B.V.; URL: www.knaufinsulation.nl; Description: Naturoll 035 - 240mm; phone: +31(0)162-421245; email: customerservice.nl@knaufinsulation.com; product URL: https://www.knaufinsulation.nl/producten-van-knauf-insulation/naturoll-035; warmteweerstand: 6.85; NLRS_C_Code_Brandklasse: A1; warmtegeleidingscoëfficiënt: 0.035; kortstondige waterabsorptie: WS; langdurige waterabsorptie: WL(P); waterdamptransmissie / waterdampdiffusie weerstandsfactor: MU1; luchtstroomweerstand: Afr5; DoP nummer (Declaration of performance): G4220LPCPR; NLRS_C_content_creator: Knauf Insulation; NLRS_C_content_versie: V1.0; diktebereik: 20 - 370; diktetolerantie: T2; pak (m2): 3.6; pakken / pallet: 24; pallet (m2): 86.3
Classification: 23 Vloeren (Uniformat)
Pset_SlabCommon - LoadBearing: no; PitchAngle: 0 deg
Pset_Floor Schedule Naturoll 035 LOD400 - Type: Floor: NLRS_23_FL_Naturoll 035_240x580x3100mm

# IfcSlab: Floor:NLRS_23_FL_Naturoll 035_245x590x2600mm, Floor:NLRS_23_FL_Naturoll 035_245x590x2600mm:42664
In: Begane grond
Type - PredefinedType: FLOOR; Material: Knauf Insulation_Ecose® glaswol_naturoll 035 245 mm
Type - Pset_ElementShading - Roughness: 304.8 mm
Type - Pset_ManufacturerTypeInformation - Manufacturer: Knauf Insulation B.V.
Type - Pset_ProductRequirements - Category: Floors
Type - Pset_QuantityTakeOff - Reference: Floor:NLRS_23_FL_Naturoll 035_245x590x2600mm
Type - Pset_ReinforcementBarPitchOfSlab - Description: Naturoll 035 - 245mm; Reference: Floor:NLRS_23_FL_Naturoll 035_245x590x2600mm
Type - Pset_SlabCommon - IsExternal: no; Reference: Floor:NLRS_23_FL_Naturoll 035_245x590x2600mm; ThermalTransmittance: 0.142857 kg/K/s3
Type - Pset_Floor Schedule Naturoll 035 LOD400 - rollen / pak: 2; warmteweerstand: 7; Assembly Code: 23; Type Image: Raster image: Naturoll 035 .jpg (2); Model: Naturoll 035 is een onbeklede glaswoldeken met ECOSE® Technology; Manufacturer: Knauf Insulation B.V.; URL: www.knaufinsulation.nl; Description: Naturoll 035 - 245mm; phone: +31(0)162-421245; email: customerservice.nl@knaufinsulation.com; product URL: https://www.knaufinsulation.nl/producten-van-knauf-insulation/naturoll-035; NLRS_C_Code_Brandklasse: A1; warmtegeleidingscoëfficiënt: 0.035; kortstondige waterabsorptie: WS; langdurige waterabsorptie: WL(P); waterdamptransmissie / waterdampdiffusie weerstandsfactor: MU1; luchtstroomweerstand: Afr5; DoP nummer (Declaration of performance): G4220LPCPR; NLRS_C_content_creator: Knauf Insulation; NLRS_C_content_versie: V1.0; diktebereik: 20 - 370; diktetolerantie: T2; pak (m2): 3.07; pakken / pallet: 24; pallet (m2): 73.6
Classification: 23 Vloeren (Uniformat)
Pset_SlabCommon - LoadBearing: no; PitchAngle: 0 deg
Pset_Floor Schedule Naturoll 035 LOD400 - Type: Floor: NLRS_23_FL_Naturoll 035_245x590x2600mm

# IfcSlab: Floor:NLRS_23_FL_Naturoll 035_260x590x2700mm, Floor:NLRS_23_FL_Naturoll 035_260x590x2700mm:42603
In: Begane grond
Type - PredefinedType: FLOOR; Material: Knauf Insulation_Ecose® glaswol_naturoll 035 260 mm
Type - Pset_ElementShading - Roughness: 304.8 mm
Type - Pset_ManufacturerTypeInformation - Manufacturer: Knauf Insulation B.V.
Type - Pset_ProductRequirements - Category: Floors
Type - Pset_QuantityTakeOff - Reference: Floor:NLRS_23_FL_Naturoll 035_260x590x2700mm
Type - Pset_ReinforcementBarPitchOfSlab - Description: Naturoll 035 - 260mm; Reference: Floor:NLRS_23_FL_Naturoll 035_260x590x2700mm
Type - Pset_SlabCommon - IsExternal: no; Reference: Floor:NLRS_23_FL_Naturoll 035_260x590x2700mm; ThermalTransmittance: 0.134615 kg/K/s3
Type - Pset_Floor Schedule Naturoll 035 LOD400 - rollen / pak: 2; Assembly Code: 23; Type Image: Raster image: Naturoll 035 .jpg (2); Model: Naturoll 035 is een onbeklede glaswoldeken met ECOSE® Technology; Manufacturer: Knauf Insulation B.V.; URL: www.knaufinsulation.nl; Description: Naturoll 035 - 260mm; phone: +31(0)162-421245; email: customerservice.nl@knaufinsulation.com; product URL: https://www.knaufinsulation.nl/producten-van-knauf-insulation/naturoll-035; warmteweerstand: 7.4; NLRS_C_Code_Brandklasse: A1; warmtegeleidingscoëfficiënt: 0.035; kortstondige waterabsorptie: WS; langdurige waterabsorptie: WL(P); waterdamptransmissie / waterdampdiffusie weerstandsfactor: MU1; luchtstroomweerstand: Afr5; DoP nummer (Declaration of performance): G4220LPCPR; NLRS_C_content_creator: Knauf Insulation; NLRS_C_content_versie: V1.0; diktebereik: 20 - 370; diktetolerantie: T2; pak (m2): 3.19; pakken / pallet: 24; pallet (m2): 76.05
Classification: 23 Vloeren (Uniformat)
Pset_SlabCommon - LoadBearing: no; PitchAngle: 0 deg
Pset_Floor Schedule Naturoll 035 LOD400 - Type: Floor: NLRS_23_FL_Naturoll 035_260x590x2700mm

# IfcSlab: Floor:NLRS_23_FL_Naturoll 035_270x590x2600mm, Floor:NLRS_23_FL_Naturoll 035_270x590x2600mm:35490
In: Begane grond
Type - PredefinedType: FLOOR; Material: Knauf Insulation_Ecose® glaswol_naturoll 035 270 mm
Type - Pset_ElementShading - Roughness: 304.8 mm
Type - Pset_ManufacturerTypeInformation - Manufacturer: Knauf Insulation B.V.
Type - Pset_ProductRequirements - Category: Floors
Type - Pset_QuantityTakeOff - Reference: Floor:NLRS_23_FL_Naturoll 035_270x590x2600mm
Type - Pset_ReinforcementBarPitchOfSlab - Description: Naturoll 035 - 270mm; Reference: Floor:NLRS_23_FL_Naturoll 035_270x590x2600mm
Type - Pset_SlabCommon - IsExternal: no; Reference: Floor:NLRS_23_FL_Naturoll 035_270x590x2600mm; ThermalTransmittance: 0.12963 kg/K/s3
Type - Pset_Floor Schedule Naturoll 035 LOD400 - rollen / pak: 2; Assembly Code: 23; Type Image: Raster image: Naturoll 035 .jpg (2); Model: Naturoll 035 is een onbeklede glaswoldeken met ECOSE® Technology; Manufacturer: Knauf Insulation B.V.; URL: www.knaufinsulation.nl; Description: Naturoll 035 - 270mm; phone: +31(0)162-421245; email: customerservice.nl@knaufinsulation.com; product URL: https://www.knaufinsulation.nl/producten-van-knauf-insulation/naturoll-035; warmteweerstand: 7.7; NLRS_C_Code_Brandklasse: A1; warmtegeleidingscoëfficiënt: 0.035; kortstondige waterabsorptie: WS; langdurige waterabsorptie: WL(P); waterdamptransmissie / waterdampdiffusie weerstandsfactor: MU1; luchtstroomweerstand: Afr5; DoP nummer (Declaration of performance): G4220LPCPR; NLRS_C_content_creator: Knauf Insulation; NLRS_C_content_versie: V1.0; diktebereik: 20 - 370; diktetolerantie: T2; pak (m2): 3.07; pakken / pallet: 24; pallet (m2): 73.6
Classification: 23 Vloeren (Uniformat)
Pset_SlabCommon - LoadBearing: no; PitchAngle: 0 deg
Pset_Floor Schedule Naturoll 035 LOD400 - Type: Floor: NLRS_23_FL_Naturoll 035_270x590x2600mm

# IfcSlab: Floor:NLRS_23_FL_Naturoll 035_90x380x7600mm, Floor:NLRS_23_FL_Naturoll 035_90x380x7600mm:33541
In: Begane grond
Type - PredefinedType: FLOOR; Material: Knauf Insulation_Ecose® glaswol_naturoll 035 90 mm
Type - Pset_ElementShading - Roughness: 304.8 mm
Type - Pset_ManufacturerTypeInformation - Manufacturer: Knauf Insulation B.V.
Type - Pset_ProductRequirements - Category: Floors
Type - Pset_QuantityTakeOff - Reference: Floor:NLRS_23_FL_Naturoll 035_90x380x7600mm
Type - Pset_ReinforcementBarPitchOfSlab - Description: Naturoll 035 - 90mm; Reference: Floor:NLRS_23_FL_Naturoll 035_90x380x7600mm
Type - Pset_SlabCommon - Reference: Floor:NLRS_23_FL_Naturoll 035_90x380x7600mm; IsExternal: no; ThermalTransmittance: 0.388889 kg/K/s3
Type - Pset_Floor Schedule Naturoll 035 LOD400 - rollen / pak: 3; Assembly Code: 23; Type Image: Raster image: Naturoll 035 .jpg (2); Model: Naturoll 035 is een onbeklede glaswoldeken met ECOSE® Technology; Manufacturer: Knauf Insulation B.V.; URL: www.knaufinsulation.nl; Description: Naturoll 035 - 90mm; phone: +31(0)162-421245; email: customerservice.nl@knaufinsulation.com; product URL: https://www.knaufinsulation.nl/producten-van-knauf-insulation/naturoll-035; warmteweerstand: 2.55; NLRS_C_Code_Brandklasse: A1; warmtegeleidingscoëfficiënt: 0.035; kortstondige waterabsorptie: WS; langdurige waterabsorptie: WL(P); waterdamptransmissie / waterdampdiffusie weerstandsfactor: MU1; luchtstroomweerstand: Afr5; DoP nummer (Declaration of performance): G4220LPCPR; NLRS_C_content_creator: Knauf Insulation; NLRS_C_content_versie: V1.0; diktebereik: 20 - 370; diktetolerantie: T2; pak (m2): 8.66; pakken / pallet: 24; pallet (m2): 207.94
Classification: 23 Vloeren (Uniformat)
Pset_SlabCommon - LoadBearing: no; PitchAngle: 0 deg
Pset_Floor Schedule Naturoll 035 LOD400 - Type: Floor: NLRS_23_FL_Naturoll 035_90x380x7600mm

# IfcSlab: Floor:NLRS_23_FL_Naturoll 035_90x580x7600mm, Floor:NLRS_23_FL_Naturoll 035_90x580x7600mm:34911
In: Begane grond
Type - PredefinedType: FLOOR; Material: Knauf Insulation_Ecose® glaswol_naturoll 035 90 mm
Type - Pset_ElementShading - Roughness: 304.8 mm
Type - Pset_ManufacturerTypeInformation - Manufacturer: Knauf Insulation B.V.
Type - Pset_ProductRequirements - Category: Floors
Type - Pset_QuantityTakeOff - Reference: Floor:NLRS_23_FL_Naturoll 035_90x580x7600mm
Type - Pset_ReinforcementBarPitchOfSlab - Description: Naturoll 035 - 90mm; Reference: Floor:NLRS_23_FL_Naturoll 035_90x580x7600mm
Type - Pset_SlabCommon - IsExternal: no; Reference: Floor:NLRS_23_FL_Naturoll 035_90x580x7600mm; ThermalTransmittance: 0.388889 kg/K/s3
Type - Pset_Floor Schedule Naturoll 035 LOD400 - rollen / pak: 2; Assembly Code: 23; Type Image: Raster image: Naturoll 035 .jpg (2); Model: Naturoll 035 is een onbeklede glaswoldeken met ECOSE® Technology; Manufacturer: Knauf Insulation B.V.; URL: www.knaufinsulation.nl; Description: Naturoll 035 - 90mm; phone: +31(0)162-421245; email: customerservice.nl@knaufinsulation.com; product URL: https://www.knaufinsulation.nl/producten-van-knauf-insulation/naturoll-035; warmteweerstand: 2.55; NLRS_C_Code_Brandklasse: A1; warmtegeleidingscoëfficiënt: 0.035; kortstondige waterabsorptie: WS; langdurige waterabsorptie: WL(P); waterdamptransmissie / waterdampdiffusie weerstandsfactor: MU1; luchtstroomweerstand: Afr5; DoP nummer (Declaration of performance): G4220LPCPR; NLRS_C_content_creator: Knauf Insulation; NLRS_C_content_versie: V1.0; diktebereik: 20 - 370; diktetolerantie: T2; pak (m2): 8.82; pakken / pallet: 24; pallet (m2): 211.58
Classification: 23 Vloeren (Uniformat)
Pset_SlabCommon - LoadBearing: no; PitchAngle: 0 deg
Pset_Floor Schedule Naturoll 035 LOD400 - Type: Floor: NLRS_23_FL_Naturoll 035_90x580x7600mm

# IfcWallStandardCase: Basic Wall:NLRS_21_WA_Naturoll 035_100x580x7400mm (2)
In: Begane grond
Type - PredefinedType: STANDARD; Material: Knauf Insulation_Ecose® glaswol_naturoll 035 100 mm
Type - Pset_ElementShading - Roughness: 304.8 mm
Type - Pset_ManufacturerTypeInformation - Manufacturer: Knauf Insulation B.V.
Type - Pset_ProductRequirements - Category: Walls
Type - Pset_QuantityTakeOff - Reference: Basic Wall:NLRS_21_WA_Naturoll 035_100x580x7400mm
Type - Pset_ReinforcementBarPitchOfWall - Description: Naturoll 035 - 100mm; Reference: Basic Wall:NLRS_21_WA_Naturoll 035_100x580x7400mm
Type - Pset_WallCommon - IsExternal: no; ThermalTransmittance: 0.35 kg/K/s3; Reference: Basic Wall:NLRS_21_WA_Naturoll 035_100x580x7400mm
Type - Pset_Wall Schedule Naturoll 035 LOD400 - rollen / pak: 2; Assembly Code: 21; Type Image: Raster image: Naturoll 035 .jpg (2); Model: Naturoll 035 is een onbeklede glaswoldeken met ECOSE® Technology; Manufacturer: Knauf Insulation B.V.; URL: www.knaufinsulation.nl; Description: Naturoll 035 - 100mm; phone: +31(0)162-421245; email: customerservice.nl@knaufinsulation.com; product URL: https://www.knaufinsulation.nl/producten-van-knauf-insulation/naturoll-035; warmteweerstand: 2.85; NLRS_C_Code_Brandklasse: A1; warmtegeleidingscoëfficiënt: 0.035; kortstondige waterabsorptie: WS; langdurige waterabsorptie: WL(P); waterdamptransmissie / waterdampdiffusie weerstandsfactor: MU1; luchtstroomweerstand: Afr5; DoP nummer (Declaration of performance): G4220LPCPR; NLRS_C_content_creator: Knauf Insulation; NLRS_C_content_versie: V1.0; diktebereik: 20 - 370; diktetolerantie: T2; pak (m2): 8.58; pakken / pallet: 24; pallet (m2): 206.02
Classification: 21 Buitenwanden (Uniformat)
Pset_WallCommon - LoadBearing: no; IsExternal: yes; ExtendToStructure: no
Pset_Wall Schedule Naturoll 035 LOD400 - Type: Basic Wall: NLRS_21_WA_Naturoll 035_100x580x7400mm
Name (Basic Wall:NLRS_21_WA_Naturoll 035_100x580x7400mm:...)
34996
34998

# IfcWallStandardCase: Basic Wall:NLRS_21_WA_Naturoll 035_120x380x6200mm (2)
In: Begane grond
Type - PredefinedType: STANDARD; Material: Knauf Insulation_Ecose® glaswol_naturoll 035 120 mm
Type - Pset_ElementShading - Roughness: 304.8 mm
Type - Pset_ManufacturerTypeInformation - Manufacturer: Knauf Insulation B.V.
Type - Pset_ProductRequirements - Category: Walls
Type - Pset_QuantityTakeOff - Reference: Basic Wall:NLRS_21_WA_Naturoll 035_120x380x6200mm
Type - Pset_ReinforcementBarPitchOfWall - Description: Naturoll 035 - 120mm; Reference: Basic Wall:NLRS_21_WA_Naturoll 035_120x380x6200mm
Type - Pset_WallCommon - IsExternal: no; Reference: Basic Wall:NLRS_21_WA_Naturoll 035_120x380x6200mm; ThermalTransmittance: 0.291667 kg/K/s3
Type - Pset_Wall Schedule Naturoll 035 LOD400 - rollen / pak: 2; Assembly Code: 21; Type Image: Raster image: Naturoll 035 .jpg (2); Model: Naturoll 035 is een onbeklede glaswoldeken met ECOSE® Technology; Manufacturer: Knauf Insulation B.V.; URL: www.knaufinsulation.nl; Description: Naturoll 035 - 120mm; phone: +31(0)162-421245; email: customerservice.nl@knaufinsulation.com; product URL: https://www.knaufinsulation.nl/producten-van-knauf-insulation/naturoll-035; warmteweerstand: 3.4; NLRS_C_Code_Brandklasse: A1; warmtegeleidingscoëfficiënt: 0.035; kortstondige waterabsorptie: WS; langdurige waterabsorptie: WL(P); waterdamptransmissie / waterdampdiffusie weerstandsfactor: MU1; luchtstroomweerstand: Afr5; DoP nummer (Declaration of performance): G4220LPCPR; NLRS_C_content_creator: Knauf Insulation; NLRS_C_content_versie: V1.0; diktebereik: 20 - 370; diktetolerantie: T2; pak (m2): 7.07; pakken / pallet: 24; pallet (m2): 169.63
Classification: 21 Buitenwanden (Uniformat)
Pset_WallCommon - LoadBearing: no; IsExternal: yes; ExtendToStructure: no
Pset_Wall Schedule Naturoll 035 LOD400 - Type: Basic Wall: NLRS_21_WA_Naturoll 035_120x380x6200mm
Name (Basic Wall:NLRS_21_WA_Naturoll 035_120x380x6200mm:...)
35018
35020

# IfcWallStandardCase: Basic Wall:NLRS_21_WA_Naturoll 035_120x580x6200mm (2)
In: Begane grond
Type - PredefinedType: STANDARD; Material: Knauf Insulation_Ecose® glaswol_naturoll 035 120 mm
Type - Pset_ElementShading - Roughness: 304.8 mm
Type - Pset_ManufacturerTypeInformation - Manufacturer: Knauf Insulation B.V.
Type - Pset_ProductRequirements - Category: Walls
Type - Pset_QuantityTakeOff - Reference: Basic Wall:NLRS_21_WA_Naturoll 035_120x580x6200mm
Type - Pset_ReinforcementBarPitchOfWall - Description: Naturoll 035 - 120mm; Reference: Basic Wall:NLRS_21_WA_Naturoll 035_120x580x6200mm
Type - Pset_WallCommon - IsExternal: no; Reference: Basic Wall:NLRS_21_WA_Naturoll 035_120x580x6200mm; ThermalTransmittance: 0.291667 kg/K/s3
Type - Pset_Wall Schedule Naturoll 035 LOD400 - rollen / pak: 3; Assembly Code: 21; Type Image: Raster image: Naturoll 035 .jpg (2); Model: Naturoll 035 is een onbeklede glaswoldeken met ECOSE® Technology; Manufacturer: Knauf Insulation B.V.; URL: www.knaufinsulation.nl; Description: Naturoll 035 - 120mm; phone: +31(0)162-421245; email: customerservice.nl@knaufinsulation.com; product URL: https://www.knaufinsulation.nl/producten-van-knauf-insulation/naturoll-035; warmteweerstand: 3.4; NLRS_C_Code_Brandklasse: A1; warmtegeleidingscoëfficiënt: 0.035; kortstondige waterabsorptie: WS; langdurige waterabsorptie: WL(P); waterdamptransmissie / waterdampdiffusie weerstandsfactor: MU1; luchtstroomweerstand: Afr5; DoP nummer (Declaration of performance): G4220LPCPR; NLRS_C_content_creator: Knauf Insulation; NLRS_C_content_versie: V1.0; diktebereik: 20 - 370; diktetolerantie: T2; pak (m2): 7.19; pakken / pallet: 24; pallet (m2): 172.61
Classification: 21 Buitenwanden (Uniformat)
Pset_WallCommon - LoadBearing: no; IsExternal: yes; ExtendToStructure: no
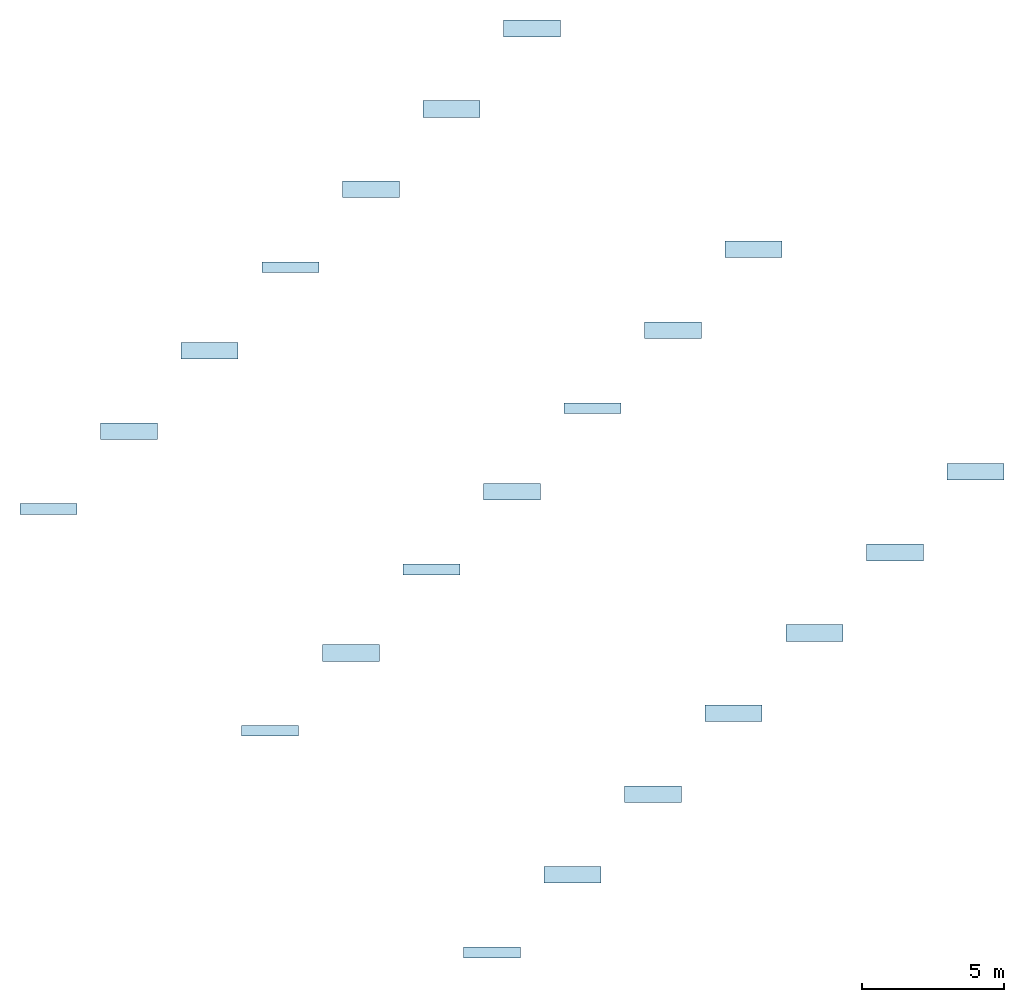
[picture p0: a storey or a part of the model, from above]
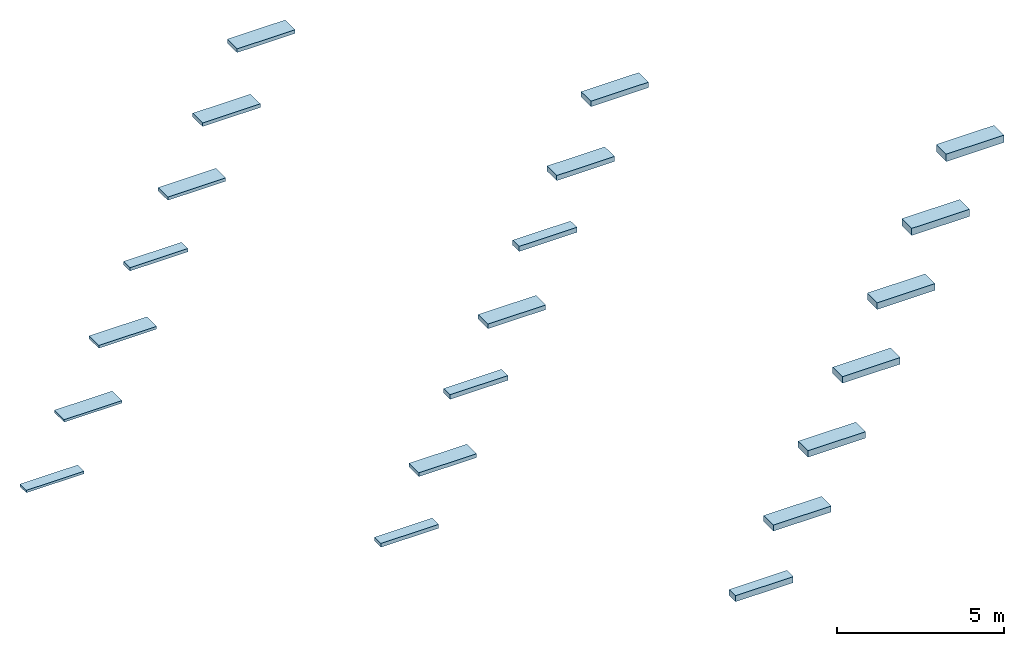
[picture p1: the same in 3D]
Properties of the parts of a building model (IFC2X3), part 3 of 3

# IfcWallStandardCase: Basic Wall:NLRS_21_WA_Naturoll 035_120x580x6200mm (2)
Pset_Wall Schedule Naturoll 035 LOD400 - Type: Basic Wall: NLRS_21_WA_Naturoll 035_120x580x6200mm
Name (Basic Wall:NLRS_21_WA_Naturoll 035_120x580x6200mm:...)
35040
35042

# IfcWallStandardCase: Basic Wall:NLRS_21_WA_Naturoll 035_130x590x5500mm (2)
In: Begane grond
Type - PredefinedType: STANDARD; Material: Knauf Insulation_Ecose® glaswol_naturoll 035 130 mm
Type - Pset_ElementShading - Roughness: 304.8 mm
Type - Pset_ManufacturerTypeInformation - Manufacturer: Knauf Insulation B.V.
Type - Pset_ProductRequirements - Category: Walls
Type - Pset_QuantityTakeOff - Reference: Basic Wall:NLRS_21_WA_Naturoll 035_130x590x5500mm
Type - Pset_ReinforcementBarPitchOfWall - Description: Naturoll 035 - 130mm; Reference: Basic Wall:NLRS_21_WA_Naturoll 035_130x590x5500mm
Type - Pset_WallCommon - IsExternal: no; Reference: Basic Wall:NLRS_21_WA_Naturoll 035_130x590x5500mm; ThermalTransmittance: 0.269231 kg/K/s3
Type - Pset_Wall Schedule Naturoll 035 LOD400 - rollen / pak: 2; Assembly Code: 21; Type Image: Raster image: Naturoll 035 .jpg (2); Model: Naturoll 035 is een onbeklede glaswoldeken met ECOSE® Technology; Manufacturer: Knauf Insulation B.V.; URL: www.knaufinsulation.nl; Description: Naturoll 035 - 130mm; phone: +31(0)162-421245; email: customerservice.nl@knaufinsulation.com; product URL: https://www.knaufinsulation.nl/producten-van-knauf-insulation/naturoll-035; warmteweerstand: 3.7; NLRS_C_Code_Brandklasse: A1; warmtegeleidingscoëfficiënt: 0.035; kortstondige waterabsorptie: WS; langdurige waterabsorptie: WL(P); waterdamptransmissie / waterdampdiffusie weerstandsfactor: MU1; luchtstroomweerstand: Afr5; DoP nummer (Declaration of performance): G4220LPCPR; NLRS_C_content_creator: Knauf Insulation; NLRS_C_content_versie: V1.0; diktebereik: 20 - 370; diktetolerantie: T2; pak (m2): 6.49; pakken / pallet: 24; pallet (m2): 155.76
Classification: 21 Buitenwanden (Uniformat)
Pset_WallCommon - LoadBearing: no; IsExternal: yes; ExtendToStructure: no
Pset_Wall Schedule Naturoll 035 LOD400 - Type: Basic Wall: NLRS_21_WA_Naturoll 035_130x590x5500mm
Name (Basic Wall:NLRS_21_WA_Naturoll 035_130x590x5500mm:...)
35062
35064

# IfcWallStandardCase: Basic Wall:NLRS_21_WA_Naturoll 035_135x590x5300mm (2)
In: Begane grond
Type - PredefinedType: STANDARD; Material: Knauf Insulation_Ecose® glaswol_naturoll 035 135 mm
Type - Pset_ElementShading - Roughness: 304.8 mm
Type - Pset_ManufacturerTypeInformation - Manufacturer: Knauf Insulation B.V.
Type - Pset_ProductRequirements - Category: Walls
Type - Pset_QuantityTakeOff - Reference: Basic Wall:NLRS_21_WA_Naturoll 035_135x590x5300mm
Type - Pset_ReinforcementBarPitchOfWall - Description: Naturoll 035 - 135mm; Reference: Basic Wall:NLRS_21_WA_Naturoll 035_135x590x5300mm
Type - Pset_WallCommon - IsExternal: no; Reference: Basic Wall:NLRS_21_WA_Naturoll 035_135x590x5300mm; ThermalTransmittance: 0.259259 kg/K/s3
Type - Pset_Wall Schedule Naturoll 035 LOD400 - rollen / pak: 2; Assembly Code: 21; Type Image: Raster image: Naturoll 035 .jpg (2); Model: Naturoll 035 is een onbeklede glaswoldeken met ECOSE® Technology; Manufacturer: Knauf Insulation B.V.; URL: www.knaufinsulation.nl; Description: Naturoll 035 - 135mm; phone: +31(0)162-421245; email: customerservice.nl@knaufinsulation.com; product URL: https://www.knaufinsulation.nl/producten-van-knauf-insulation/naturoll-035; warmteweerstand: 3.85; NLRS_C_Code_Brandklasse: A1; warmtegeleidingscoëfficiënt: 0.035; kortstondige waterabsorptie: WS; langdurige waterabsorptie: WL(P); waterdamptransmissie / waterdampdiffusie weerstandsfactor: MU1; luchtstroomweerstand: Afr5; DoP nummer (Declaration of performance): G4220LPCPR; NLRS_C_content_creator: Knauf Insulation; NLRS_C_content_versie: V1.0; diktebereik: 20 - 370; diktetolerantie: T2; pak (m2): 6.25; pakken / pallet: 24; pallet (m2): 150.1
Classification: 21 Buitenwanden (Uniformat)
Pset_WallCommon - LoadBearing: no; IsExternal: yes; ExtendToStructure: no
Pset_Wall Schedule Naturoll 035 LOD400 - Type: Basic Wall: NLRS_21_WA_Naturoll 035_135x590x5300mm
Name (Basic Wall:NLRS_21_WA_Naturoll 035_135x590x5300mm:...)
42293
42295

# IfcWallStandardCase: Basic Wall:NLRS_21_WA_Naturoll 035_140x380x5300mm (2)
In: Begane grond
Type - PredefinedType: STANDARD; Material: Knauf Insulation_Ecose® glaswol_naturoll 035 140 mm
Type - Pset_ElementShading - Roughness: 304.8 mm
Type - Pset_ManufacturerTypeInformation - Manufacturer: Knauf Insulation B.V.
Type - Pset_ProductRequirements - Category: Walls
Type - Pset_QuantityTakeOff - Reference: Basic Wall:NLRS_21_WA_Naturoll 035_140x380x5300mm
Type - Pset_ReinforcementBarPitchOfWall - Description: Naturoll 035 - 140mm; Reference: Basic Wall:NLRS_21_WA_Naturoll 035_140x380x5300mm
Type - Pset_WallCommon - IsExternal: no; ThermalTransmittance: 0.25 kg/K/s3; Reference: Basic Wall:NLRS_21_WA_Naturoll 035_140x380x5300mm
Type - Pset_Wall Schedule Naturoll 035 LOD400 - rollen / pak: 2; warmteweerstand: 4; Assembly Code: 21; Type Image: Raster image: Naturoll 035 .jpg (2); Model: Naturoll 035 is een onbeklede glaswoldeken met ECOSE® Technology; Manufacturer: Knauf Insulation B.V.; URL: www.knaufinsulation.nl; Description: Naturoll 035 - 140mm; phone: +31(0)162-421245; email: customerservice.nl@knaufinsulation.com; product URL: https://www.knaufinsulation.nl/producten-van-knauf-insulation/naturoll-035; NLRS_C_Code_Brandklasse: A1; warmtegeleidingscoëfficiënt: 0.035; kortstondige waterabsorptie: WS; langdurige waterabsorptie: WL(P); waterdamptransmissie / waterdampdiffusie weerstandsfactor: MU1; luchtstroomweerstand: Afr5; DoP nummer (Declaration of performance): G4220LPCPR; NLRS_C_content_creator: Knauf Insulation; NLRS_C_content_versie: V1.0; diktebereik: 20 - 370; diktetolerantie: T2; pak (m2): 6.04; pakken / pallet: 24; pallet (m2): 145.01
Classification: 21 Buitenwanden (Uniformat)
Pset_WallCommon - LoadBearing: no; IsExternal: yes; ExtendToStructure: no
Pset_Wall Schedule Naturoll 035 LOD400 - Type: Basic Wall: NLRS_21_WA_Naturoll 035_140x380x5300mm
Name (Basic Wall:NLRS_21_WA_Naturoll 035_140x380x5300mm:...)
35112
35114

# IfcWallStandardCase: Basic Wall:NLRS_21_WA_Naturoll 035_140x580x5300mm (2)
In: Begane grond
Type - PredefinedType: STANDARD; Material: Knauf Insulation_Ecose® glaswol_naturoll 035 140 mm
Type - Pset_ElementShading - Roughness: 304.8 mm
Type - Pset_ManufacturerTypeInformation - Manufacturer: Knauf Insulation B.V.
Type - Pset_ProductRequirements - Category: Walls
Type - Pset_QuantityTakeOff - Reference: Basic Wall:NLRS_21_WA_Naturoll 035_140x580x5300mm
Type - Pset_ReinforcementBarPitchOfWall - Description: Naturoll 035 - 140mm; Reference: Basic Wall:NLRS_21_WA_Naturoll 035_140x580x5300mm
Type - Pset_WallCommon - IsExternal: no; ThermalTransmittance: 0.25 kg/K/s3; Reference: Basic Wall:NLRS_21_WA_Naturoll 035_140x580x5300mm
Type - Pset_Wall Schedule Naturoll 035 LOD400 - rollen / pak: 3; warmteweerstand: 4; Assembly Code: 21; Type Image: Raster image: Naturoll 035 .jpg (2); Model: Naturoll 035 is een onbeklede glaswoldeken met ECOSE® Technology; Manufacturer: Knauf Insulation B.V.; URL: www.knaufinsulation.nl; Description: Naturoll 035 - 140mm; phone: +31(0)162-421245; email: customerservice.nl@knaufinsulation.com; product URL: https://www.knaufinsulation.nl/producten-van-knauf-insulation/naturoll-035; NLRS_C_Code_Brandklasse: A1; warmtegeleidingscoëfficiënt: 0.035; kortstondige waterabsorptie: WS; langdurige waterabsorptie: WL(P); waterdamptransmissie / waterdampdiffusie weerstandsfactor: MU1; luchtstroomweerstand: Afr5; DoP nummer (Declaration of performance): G4220LPCPR; NLRS_C_content_creator: Knauf Insulation; NLRS_C_content_versie: V1.0; diktebereik: 20 - 370; diktetolerantie: T2; pak (m2): 6.15; pakken / pallet: 24; pallet (m2): 147.55
Classification: 21 Buitenwanden (Uniformat)
Pset_WallCommon - LoadBearing: no; IsExternal: yes; ExtendToStructure: no
Pset_Wall Schedule Naturoll 035 LOD400 - Type: Basic Wall: NLRS_21_WA_Naturoll 035_140x580x5300mm
Name (Basic Wall:NLRS_21_WA_Naturoll 035_140x580x5300mm:...)
35132
35134

# IfcWallStandardCase: Basic Wall:NLRS_21_WA_Naturoll 035_170x380x4350mm (2)
In: Begane grond
Type - PredefinedType: STANDARD; Material: Knauf Insulation_Ecose® glaswol_naturoll 035 170 mm
Type - Pset_ElementShading - Roughness: 304.8 mm
Type - Pset_ManufacturerTypeInformation - Manufacturer: Knauf Insulation B.V.
Type - Pset_ProductRequirements - Category: Walls
Type - Pset_QuantityTakeOff - Reference: Basic Wall:NLRS_21_WA_Naturoll 035_170x380x4350mm
Type - Pset_ReinforcementBarPitchOfWall - Description: Naturoll 035 - 170mm; Reference: Basic Wall:NLRS_21_WA_Naturoll 035_170x380x4350mm
Type - Pset_WallCommon - IsExternal: no; Reference: Basic Wall:NLRS_21_WA_Naturoll 035_170x380x4350mm; ThermalTransmittance: 0.205882 kg/K/s3
Type - Pset_Wall Schedule Naturoll 035 LOD400 - rollen / pak: 2; Assembly Code: 21; Type Image: Raster image: Naturoll 035 .jpg (2); Model: Naturoll 035 is een onbeklede glaswoldeken met ECOSE® Technology; Manufacturer: Knauf Insulation B.V.; URL: www.knaufinsulation.nl; Description: Naturoll 035 - 170mm; phone: +31(0)162-421245; email: customerservice.nl@knaufinsulation.com; product URL: https://www.knaufinsulation.nl/producten-van-knauf-insulation/naturoll-035; warmteweerstand: 4.85; NLRS_C_Code_Brandklasse: A1; warmtegeleidingscoëfficiënt: 0.035; kortstondige waterabsorptie: WS; langdurige waterabsorptie: WL(P); waterdamptransmissie / waterdampdiffusie weerstandsfactor: MU1; luchtstroomweerstand: Afr5; DoP nummer (Declaration of performance): G4220LPCPR; NLRS_C_content_creator: Knauf Insulation; NLRS_C_content_versie: V1.0; diktebereik: 20 - 370; diktetolerantie: T2; pak (m2): 4.96; pakken / pallet: 24; pallet (m2): 119.02
Classification: 21 Buitenwanden (Uniformat)
Pset_WallCommon - LoadBearing: no; IsExternal: yes; ExtendToStructure: no
Pset_Wall Schedule Naturoll 035 LOD400 - Type: Basic Wall: NLRS_21_WA_Naturoll 035_170x380x4350mm
Name (Basic Wall:NLRS_21_WA_Naturoll 035_170x380x4350mm:...)
35172
35174

# IfcWallStandardCase: Basic Wall:NLRS_21_WA_Naturoll 035_170x580x4350mm (2)
In: Begane grond
Type - PredefinedType: STANDARD; Material: Knauf Insulation_Ecose® glaswol_naturoll 035 170 mm
Type - Pset_ElementShading - Roughness: 304.8 mm
Type - Pset_ManufacturerTypeInformation - Manufacturer: Knauf Insulation B.V.
Type - Pset_ProductRequirements - Category: Walls
Type - Pset_QuantityTakeOff - Reference: Basic Wall:NLRS_21_WA_Naturoll 035_170x580x4350mm
Type - Pset_ReinforcementBarPitchOfWall - Description: Naturoll 035 - 170mm; Reference: Basic Wall:NLRS_21_WA_Naturoll 035_170x580x4350mm
Type - Pset_WallCommon - IsExternal: no; Reference: Basic Wall:NLRS_21_WA_Naturoll 035_170x580x4350mm; ThermalTransmittance: 0.205882 kg/K/s3
Type - Pset_Wall Schedule Naturoll 035 LOD400 - rollen / pak: 3; Assembly Code: 21; Type Image: Raster image: Naturoll 035 .jpg (2); Model: Naturoll 035 is een onbeklede glaswoldeken met ECOSE® Technology; Manufacturer: Knauf Insulation B.V.; URL: www.knaufinsulation.nl; Description: Naturoll 035 - 170mm; phone: +31(0)162-421245; email: customerservice.nl@knaufinsulation.com; product URL: https://www.knaufinsulation.nl/producten-van-knauf-insulation/naturoll-035; warmteweerstand: 4.85; NLRS_C_Code_Brandklasse: A1; warmtegeleidingscoëfficiënt: 0.035; kortstondige waterabsorptie: WS; langdurige waterabsorptie: WL(P); waterdamptransmissie / waterdampdiffusie weerstandsfactor: MU1; luchtstroomweerstand: Afr5; DoP nummer (Declaration of performance): G4220LPCPR; NLRS_C_content_creator: Knauf Insulation; NLRS_C_content_versie: V1.0; diktebereik: 20 - 370; diktetolerantie: T2; pak (m2): 5.05; pakken / pallet: 24; pallet (m2): 121.1
Classification: 21 Buitenwanden (Uniformat)
Pset_WallCommon - LoadBearing: no; IsExternal: yes; ExtendToStructure: no
Pset_Wall Schedule Naturoll 035 LOD400 - Type: Basic Wall: NLRS_21_WA_Naturoll 035_170x580x4350mm
Name (Basic Wall:NLRS_21_WA_Naturoll 035_170x580x4350mm:...)
35192
35194

# IfcWallStandardCase: Basic Wall:NLRS_21_WA_Naturoll 035_185x380x4000mm (2)
In: Begane grond
Type - PredefinedType: STANDARD; Material: Knauf Insulation_Ecose® glaswol_naturoll 035 185 mm
Type - Pset_ElementShading - Roughness: 304.8 mm
Type - Pset_ManufacturerTypeInformation - Manufacturer: Knauf Insulation B.V.
Type - Pset_ProductRequirements - Category: Walls
Type - Pset_QuantityTakeOff - Reference: Basic Wall:NLRS_21_WA_Naturoll 035_185x380x4000mm
Type - Pset_ReinforcementBarPitchOfWall - Description: Naturoll 035 - 185mm; Reference: Basic Wall:NLRS_21_WA_Naturoll 035_185x380x4000mm
Type - Pset_WallCommon - IsExternal: no; Reference: Basic Wall:NLRS_21_WA_Naturoll 035_185x380x4000mm; ThermalTransmittance: 0.189189 kg/K/s3
Type - Pset_Wall Schedule Naturoll 035 LOD400 - rollen / pak: 2; Assembly Code: 21; Type Image: Raster image: Naturoll 035 .jpg (2); Model: Naturoll 035 is een onbeklede glaswoldeken met ECOSE® Technology; Manufacturer: Knauf Insulation B.V.; URL: www.knaufinsulation.nl; Description: Naturoll 035 - 185mm; phone: +31(0)162-421245; email: customerservice.nl@knaufinsulation.com; product URL: https://www.knaufinsulation.nl/producten-van-knauf-insulation/naturoll-035; warmteweerstand: 5.25; NLRS_C_Code_Brandklasse: A1; warmtegeleidingscoëfficiënt: 0.035; kortstondige waterabsorptie: WS; langdurige waterabsorptie: WL(P); waterdamptransmissie / waterdampdiffusie weerstandsfactor: MU1; luchtstroomweerstand: Afr5; DoP nummer (Declaration of performance): G4220LPCPR; NLRS_C_content_creator: Knauf Insulation; NLRS_C_content_versie: V1.0; diktebereik: 20 - 370; diktetolerantie: T2; pak (m2): 4.56; pakken / pallet: 24; pallet (m2): 109.44
Classification: 21 Buitenwanden (Uniformat)
Pset_WallCommon - LoadBearing: no; IsExternal: yes; ExtendToStructure: no
Pset_Wall Schedule Naturoll 035 LOD400 - Type: Basic Wall: NLRS_21_WA_Naturoll 035_185x380x4000mm
Name (Basic Wall:NLRS_21_WA_Naturoll 035_185x380x4000mm:...)
35212
35214

# IfcWallStandardCase: Basic Wall:NLRS_21_WA_Naturoll 035_185x580x4000mm (2)
In: Begane grond
Type - PredefinedType: STANDARD; Material: Knauf Insulation_Ecose® glaswol_naturoll 035 185 mm
Type - Pset_ElementShading - Roughness: 304.8 mm
Type - Pset_ManufacturerTypeInformation - Manufacturer: Knauf Insulation B.V.
Type - Pset_ProductRequirements - Category: Walls
Type - Pset_QuantityTakeOff - Reference: Basic Wall:NLRS_21_WA_Naturoll 035_185x580x4000mm
Type - Pset_ReinforcementBarPitchOfWall - Description: Naturoll 035 - 185mm; Reference: Basic Wall:NLRS_21_WA_Naturoll 035_185x580x4000mm
Type - Pset_WallCommon - IsExternal: no; Reference: Basic Wall:NLRS_21_WA_Naturoll 035_185x580x4000mm; ThermalTransmittance: 0.189189 kg/K/s3
Type - Pset_Wall Schedule Naturoll 035 LOD400 - rollen / pak: 3; Assembly Code: 21; Type Image: Raster image: Naturoll 035 .jpg (2); Model: Naturoll 035 is een onbeklede glaswoldeken met ECOSE® Technology; Manufacturer: Knauf Insulation B.V.; URL: www.knaufinsulation.nl; Description: Naturoll 035 - 185mm; phone: +31(0)162-421245; email: customerservice.nl@knaufinsulation.com; product URL: https://www.knaufinsulation.nl/producten-van-knauf-insulation/naturoll-035; warmteweerstand: 5.25; NLRS_C_Code_Brandklasse: A1; warmtegeleidingscoëfficiënt: 0.035; kortstondige waterabsorptie: WS; langdurige waterabsorptie: WL(P); waterdamptransmissie / waterdampdiffusie weerstandsfactor: MU1; luchtstroomweerstand: Afr5; DoP nummer (Declaration of performance): G4220LPCPR; NLRS_C_content_creator: Knauf Insulation; NLRS_C_content_versie: V1.0; diktebereik: 20 - 370; diktetolerantie: T2; pak (m2): 4.64; pakken / pallet: 24; pallet (m2): 111.36
Classification: 21 Buitenwanden (Uniformat)
Pset_WallCommon - LoadBearing: no; IsExternal: yes; ExtendToStructure: no
Pset_Wall Schedule Naturoll 035 LOD400 - Type: Basic Wall: NLRS_21_WA_Naturoll 035_185x580x4000mm
Name (Basic Wall:NLRS_21_WA_Naturoll 035_185x580x4000mm:...)
37500
37502

# IfcWallStandardCase: Basic Wall:NLRS_21_WA_Naturoll 035_200x580x3700mm (2)
In: Begane grond
Type - PredefinedType: STANDARD; Material: Knauf Insulation_Ecose® glaswol_naturoll 035 200 mm
Type - Pset_ElementShading - Roughness: 304.8 mm
Type - Pset_ManufacturerTypeInformation - Manufacturer: Knauf Insulation B.V.
Type - Pset_ProductRequirements - Category: Walls
Type - Pset_QuantityTakeOff - Reference: Basic Wall:NLRS_21_WA_Naturoll 035_200x580x3700mm
Type - Pset_ReinforcementBarPitchOfWall - Description: Naturoll 035 - 200mm; Reference: Basic Wall:NLRS_21_WA_Naturoll 035_200x580x3700mm
Type - Pset_WallCommon - IsExternal: no; Reference: Basic Wall:NLRS_21_WA_Naturoll 035_200x580x3700mm; ThermalTransmittance: 0.175 kg/K/s3
Type - Pset_Wall Schedule Naturoll 035 LOD400 - rollen / pak: 2; Assembly Code: 21; Type Image: Raster image: Naturoll 035 .jpg (2); Model: Naturoll 035 is een onbeklede glaswoldeken met ECOSE® Technology; Manufacturer: Knauf Insulation B.V.; URL: www.knaufinsulation.nl; Description: Naturoll 035 - 200mm; phone: +31(0)162-421245; email: customerservice.nl@knaufinsulation.com; product URL: https://www.knaufinsulation.nl/producten-van-knauf-insulation/naturoll-035; warmteweerstand: 5.7; NLRS_C_Code_Brandklasse: A1; warmtegeleidingscoëfficiënt: 0.035; kortstondige waterabsorptie: WS; langdurige waterabsorptie: WL(P); waterdamptransmissie / waterdampdiffusie weerstandsfactor: MU1; luchtstroomweerstand: Afr5; DoP nummer (Declaration of performance): G4220LPCPR; NLRS_C_content_creator: Knauf Insulation; NLRS_C_content_versie: V1.0; diktebereik: 20 - 370; diktetolerantie: T2; pak (m2): 4.29; pakken / pallet: 24; pallet (m2): 103.01
Classification: 21 Buitenwanden (Uniformat)
Pset_WallCommon - LoadBearing: no; IsExternal: yes; ExtendToStructure: no
Pset_Wall Schedule Naturoll 035 LOD400 - Type: Basic Wall: NLRS_21_WA_Naturoll 035_200x580x3700mm
Name (Basic Wall:NLRS_21_WA_Naturoll 035_200x580x3700mm:...)
35400
35402

# IfcWallStandardCase: Basic Wall:NLRS_21_WA_Naturoll 035_220x380x3400mm (2)
In: Begane grond
Type - PredefinedType: STANDARD; Material: Knauf Insulation_Ecose® glaswol_naturoll 035 220 mm
Type - Pset_ElementShading - Roughness: 304.8 mm
Type - Pset_ManufacturerTypeInformation - Manufacturer: Knauf Insulation B.V.
Type - Pset_ProductRequirements - Category: Walls
Type - Pset_QuantityTakeOff - Reference: Basic Wall:NLRS_21_WA_Naturoll 035_220x380x3400mm
Type - Pset_ReinforcementBarPitchOfWall - Description: Naturoll 035 - 220mm; Reference: Basic Wall:NLRS_21_WA_Naturoll 035_220x380x3400mm
Type - Pset_WallCommon - IsExternal: no; Reference: Basic Wall:NLRS_21_WA_Naturoll 035_220x380x3400mm; ThermalTransmittance: 0.159091 kg/K/s3
Type - Pset_Wall Schedule Naturoll 035 LOD400 - rollen / pak: 3; Assembly Code: 21; Type Image: Raster image: Naturoll 035 .jpg (2); Model: Naturoll 035 is een onbeklede glaswoldeken met ECOSE® Technology; Manufacturer: Knauf Insulation B.V.; URL: www.knaufinsulation.nl; Description: Naturoll 035 - 220mm; phone: +31(0)162-421245; email: customerservice.nl@knaufinsulation.com; product URL: https://www.knaufinsulation.nl/producten-van-knauf-insulation/naturoll-035; warmteweerstand: 6.25; NLRS_C_Code_Brandklasse: A1; warmtegeleidingscoëfficiënt: 0.035; kortstondige waterabsorptie: WS; langdurige waterabsorptie: WL(P); waterdamptransmissie / waterdampdiffusie weerstandsfactor: MU1; luchtstroomweerstand: Afr5; DoP nummer (Declaration of performance): G4220LPCPR; NLRS_C_content_creator: Knauf Insulation; NLRS_C_content_versie: V1.0; diktebereik: 20 - 370; diktetolerantie: T2; pak (m2): 3.88; pakken / pallet: 24; pallet (m2): 93.02
Classification: 21 Buitenwanden (Uniformat)
Pset_WallCommon - LoadBearing: no; IsExternal: yes; ExtendToStructure: no
Pset_Wall Schedule Naturoll 035 LOD400 - Type: Basic Wall: NLRS_21_WA_Naturoll 035_220x380x3400mm
Name (Basic Wall:NLRS_21_WA_Naturoll 035_220x380x3400mm:...)
35419
35421

# IfcWallStandardCase: Basic Wall:NLRS_21_WA_Naturoll 035_220x580x3400mm (2)
In: Begane grond
Type - PredefinedType: STANDARD; Material: Knauf Insulation_Ecose® glaswol_naturoll 035 220 mm
Type - Pset_ElementShading - Roughness: 304.8 mm
Type - Pset_ManufacturerTypeInformation - Manufacturer: Knauf Insulation B.V.
Type - Pset_ProductRequirements - Category: Walls
Type - Pset_QuantityTakeOff - Reference: Basic Wall:NLRS_21_WA_Naturoll 035_220x580x3400mm
Type - Pset_ReinforcementBarPitchOfWall - Description: Naturoll 035 - 220mm; Reference: Basic Wall:NLRS_21_WA_Naturoll 035_220x580x3400mm
Type - Pset_WallCommon - IsExternal: no; Reference: Basic Wall:NLRS_21_WA_Naturoll 035_220x580x3400mm; ThermalTransmittance: 0.159091 kg/K/s3
Type - Pset_Wall Schedule Naturoll 035 LOD400 - rollen / pak: 2; Assembly Code: 21; Type Image: Raster image: Naturoll 035 .jpg (2); Model: Naturoll 035 is een onbeklede glaswoldeken met ECOSE® Technology; Manufacturer: Knauf Insulation B.V.; URL: www.knaufinsulation.nl; Description: Naturoll 035 - 220mm; phone: +31(0)162-421245; email: customerservice.nl@knaufinsulation.com; product URL: https://www.knaufinsulation.nl/producten-van-knauf-insulation/naturoll-035; warmteweerstand: 6.25; NLRS_C_Code_Brandklasse: A1; warmtegeleidingscoëfficiënt: 0.035; kortstondige waterabsorptie: WS; langdurige waterabsorptie: WL(P); waterdamptransmissie / waterdampdiffusie weerstandsfactor: MU1; luchtstroomweerstand: Afr5; DoP nummer (Declaration of performance): G4220LPCPR; NLRS_C_content_creator: Knauf Insulation; NLRS_C_content_versie: V1.0; diktebereik: 20 - 370; diktetolerantie: T2; pak (m2): 3.94; pakken / pallet: 24; pallet (m2): 94.66
Classification: 21 Buitenwanden (Uniformat)
Pset_WallCommon - LoadBearing: no; IsExternal: yes; ExtendToStructure: no
Pset_Wall Schedule Naturoll 035 LOD400 - Type: Basic Wall: NLRS_21_WA_Naturoll 035_220x580x3400mm
Name (Basic Wall:NLRS_21_WA_Naturoll 035_220x580x3400mm:...)
35438
35440

# IfcWallStandardCase: Basic Wall:NLRS_21_WA_Naturoll 035_235x580x3100mm (2)
In: Begane grond
Type - PredefinedType: STANDARD; Material: Knauf Insulation_Ecose® glaswol_naturoll 035 235 mm
Type - Pset_ElementShading - Roughness: 304.8 mm
Type - Pset_ManufacturerTypeInformation - Manufacturer: Knauf Insulation B.V.
Type - Pset_ProductRequirements - Category: Walls
Type - Pset_QuantityTakeOff - Reference: Basic Wall:NLRS_21_WA_Naturoll 035_235x580x3100mm
Type - Pset_ReinforcementBarPitchOfWall - Description: Naturoll 035 - 235mm; Reference: Basic Wall:NLRS_21_WA_Naturoll 035_235x580x3100mm
Type - Pset_WallCommon - IsExternal: no; Reference: Basic Wall:NLRS_21_WA_Naturoll 035_235x580x3100mm; ThermalTransmittance: 0.148936 kg/K/s3
Type - Pset_Wall Schedule Naturoll 035 LOD400 - rollen / pak: 2; Assembly Code: 21; Type Image: Raster image: Naturoll 035 .jpg (2); Model: Naturoll 035 is een onbeklede glaswoldeken met ECOSE® Technology; Manufacturer: Knauf Insulation B.V.; URL: www.knaufinsulation.nl; Description: Naturoll 035 - 235mm; phone: +31(0)162-421245; email: customerservice.nl@knaufinsulation.com; product URL: https://www.knaufinsulation.nl/producten-van-knauf-insulation/naturoll-035; warmteweerstand: 6.7; NLRS_C_Code_Brandklasse: A1; warmtegeleidingscoëfficiënt: 0.035; kortstondige waterabsorptie: WS; langdurige waterabsorptie: WL(P); waterdamptransmissie / waterdampdiffusie weerstandsfactor: MU1; luchtstroomweerstand: Afr5; DoP nummer (Declaration of performance): G4220LPCPR; NLRS_C_content_creator: Knauf Insulation; NLRS_C_content_versie: V1.0; diktebereik: 20 - 370; diktetolerantie: T2; pak (m2): 3.6; pakken / pallet: 24; pallet (m2): 86.3
Classification: 21 Buitenwanden (Uniformat)
Pset_WallCommon - LoadBearing: no; IsExternal: yes; ExtendToStructure: no
Pset_Wall Schedule Naturoll 035 LOD400 - Type: Basic Wall: NLRS_21_WA_Naturoll 035_235x580x3100mm
Name (Basic Wall:NLRS_21_WA_Naturoll 035_235x580x3100mm:...)
35457
35459

# IfcWallStandardCase: Basic Wall:NLRS_21_WA_Naturoll 035_240x580x3100mm (2)
In: Begane grond
Type - PredefinedType: STANDARD; Material: Knauf Insulation_Ecose® glaswol_naturoll 035 240 mm
Type - Pset_ElementShading - Roughness: 304.8 mm
Type - Pset_ManufacturerTypeInformation - Manufacturer: Knauf Insulation B.V.
Type - Pset_ProductRequirements - Category: Walls
Type - Pset_QuantityTakeOff - Reference: Basic Wall:NLRS_21_WA_Naturoll 035_240x580x3100mm
Type - Pset_ReinforcementBarPitchOfWall - Description: Naturoll 035 - 240mm; Reference: Basic Wall:NLRS_21_WA_Naturoll 035_240x580x3100mm
Type - Pset_WallCommon - IsExternal: no; Reference: Basic Wall:NLRS_21_WA_Naturoll 035_240x580x3100mm; ThermalTransmittance: 0.145833 kg/K/s3
Type - Pset_Wall Schedule Naturoll 035 LOD400 - rollen / pak: 2; Assembly Code: 21; Type Image: Raster image: Naturoll 035 .jpg (2); Model: Naturoll 035 is een onbeklede glaswoldeken met ECOSE® Technology; Manufacturer: Knauf Insulation B.V.; URL: www.knaufinsulation.nl; Description: Naturoll 035 - 240mm; phone: +31(0)162-421245; email: customerservice.nl@knaufinsulation.com; product URL: https://www.knaufinsulation.nl/producten-van-knauf-insulation/naturoll-035; warmteweerstand: 6.85; NLRS_C_Code_Brandklasse: A1; warmtegeleidingscoëfficiënt: 0.035; kortstondige waterabsorptie: WS; langdurige waterabsorptie: WL(P); waterdamptransmissie / waterdampdiffusie weerstandsfactor: MU1; luchtstroomweerstand: Afr5; DoP nummer (Declaration of performance): G4220LPCPR; NLRS_C_content_creator: Knauf Insulation; NLRS_C_content_versie: V1.0; diktebereik: 20 - 370; diktetolerantie: T2; pak (m2): 3.6; pakken / pallet: 24; pallet (m2): 86.3
Classification: 21 Buitenwanden (Uniformat)
Pset_WallCommon - LoadBearing: no; IsExternal: yes; ExtendToStructure: no
Pset_Wall Schedule Naturoll 035 LOD400 - Type: Basic Wall: NLRS_21_WA_Naturoll 035_240x580x3100mm
Name (Basic Wall:NLRS_21_WA_Naturoll 035_240x580x3100mm:...)
35476
35478

# IfcWallStandardCase: Basic Wall:NLRS_21_WA_Naturoll 035_245x590x2600mm (2)
In: Begane grond
Type - PredefinedType: STANDARD; Material: Knauf Insulation_Ecose® glaswol_naturoll 035 245 mm
Type - Pset_ElementShading - Roughness: 304.8 mm
Type - Pset_ManufacturerTypeInformation - Manufacturer: Knauf Insulation B.V.
Type - Pset_ProductRequirements - Category: Walls
Type - Pset_QuantityTakeOff - Reference: Basic Wall:NLRS_21_WA_Naturoll 035_245x590x2600mm
Type - Pset_ReinforcementBarPitchOfWall - Description: Naturoll 035 - 245mm; Reference: Basic Wall:NLRS_21_WA_Naturoll 035_245x590x2600mm
Type - Pset_WallCommon - IsExternal: no; Reference: Basic Wall:NLRS_21_WA_Naturoll 035_245x590x2600mm; ThermalTransmittance: 0.142857 kg/K/s3
Type - Pset_Wall Schedule Naturoll 035 LOD400 - rollen / pak: 2; warmteweerstand: 7; Assembly Code: 21; Type Image: Raster image: Naturoll 035 .jpg (2); Model: Naturoll 035 is een onbeklede glaswoldeken met ECOSE® Technology; Manufacturer: Knauf Insulation B.V.; URL: www.knaufinsulation.nl; Description: Naturoll 035 - 245mm; phone: +31(0)162-421245; email: customerservice.nl@knaufinsulation.com; product URL: https://www.knaufinsulation.nl/producten-van-knauf-insulation/naturoll-035; NLRS_C_Code_Brandklasse: A1; warmtegeleidingscoëfficiënt: 0.035; kortstondige waterabsorptie: WS; langdurige waterabsorptie: WL(P); waterdamptransmissie / waterdampdiffusie weerstandsfactor: MU1; luchtstroomweerstand: Afr5; DoP nummer (Declaration of performance): G4220LPCPR; NLRS_C_content_creator: Knauf Insulation; NLRS_C_content_versie: V1.0; diktebereik: 20 - 370; diktetolerantie: T2; pak (m2): 3.07; pakken / pallet: 24; pallet (m2): 73.63
Classification: 21 Buitenwanden (Uniformat)
Pset_WallCommon - LoadBearing: no; IsExternal: yes; ExtendToStructure: no
Pset_Wall Schedule Naturoll 035 LOD400 - Type: Basic Wall: NLRS_21_WA_Naturoll 035_245x590x2600mm
Name (Basic Wall:NLRS_21_WA_Naturoll 035_245x590x2600mm:...)
42669
42671

# IfcWallStandardCase: Basic Wall:NLRS_21_WA_Naturoll 035_260x590x2700mm (2)
In: Begane grond
Type - PredefinedType: STANDARD; Material: Knauf Insulation_Ecose® glaswol_naturoll 035 260 mm
Type - Pset_ElementShading - Roughness: 304.8 mm
Type - Pset_ManufacturerTypeInformation - Manufacturer: Knauf Insulation B.V.
Type - Pset_ProductRequirements - Category: Walls
Type - Pset_QuantityTakeOff - Reference: Basic Wall:NLRS_21_WA_Naturoll 035_260x590x2700mm
Type - Pset_ReinforcementBarPitchOfWall - Description: Naturoll 035 - 260mm; Reference: Basic Wall:NLRS_21_WA_Naturoll 035_260x590x2700mm
Type - Pset_WallCommon - IsExternal: no; Reference: Basic Wall:NLRS_21_WA_Naturoll 035_260x590x2700mm; ThermalTransmittance: 0.134615 kg/K/s3
Type - Pset_Wall Schedule Naturoll 035 LOD400 - rollen / pak: 2; Assembly Code: 21; Type Image: Raster image: Naturoll 035 .jpg (2); Model: Naturoll 035 is een onbeklede glaswoldeken met ECOSE® Technology; Manufacturer: Knauf Insulation B.V.; URL: www.knaufinsulation.nl; Description: Naturoll 035 - 260mm; phone: +31(0)162-421245; email: customerservice.nl@knaufinsulation.com; product URL: https://www.knaufinsulation.nl/producten-van-knauf-insulation/naturoll-035; warmteweerstand: 7.4; NLRS_C_Code_Brandklasse: A1; warmtegeleidingscoëfficiënt: 0.035; kortstondige waterabsorptie: WS; langdurige waterabsorptie: WL(P); waterdamptransmissie / waterdampdiffusie weerstandsfactor: MU1; luchtstroomweerstand: Afr5; DoP nummer (Declaration of performance): G4220LPCPR; NLRS_C_content_creator: Knauf Insulation; NLRS_C_content_versie: V1.0; diktebereik: 20 - 370; diktetolerantie: T2; pak (m2): 3.19; pakken / pallet: 24; pallet (m2): 76.05
Classification: 21 Buitenwanden (Uniformat)
Pset_WallCommon - LoadBearing: no; IsExternal: yes; ExtendToStructure: no
Pset_Wall Schedule Naturoll 035 LOD400 - Type: Basic Wall: NLRS_21_WA_Naturoll 035_260x590x2700mm
Name (Basic Wall:NLRS_21_WA_Naturoll 035_260x590x2700mm:...)
42608
42610

# IfcWallStandardCase: Basic Wall:NLRS_21_WA_Naturoll 035_270x590x2600mm (2)
In: Begane grond
Type - PredefinedType: STANDARD; Material: Knauf Insulation_Ecose® glaswol_naturoll 035 270 mm
Type - Pset_ElementShading - Roughness: 304.8 mm
Type - Pset_ManufacturerTypeInformation - Manufacturer: Knauf Insulation B.V.
Type - Pset_ProductRequirements - Category: Walls
Type - Pset_QuantityTakeOff - Reference: Basic Wall:NLRS_21_WA_Naturoll 035_270x590x2600mm
Type - Pset_ReinforcementBarPitchOfWall - Description: Naturoll 035 - 270mm; Reference: Basic Wall:NLRS_21_WA_Naturoll 035_270x590x2600mm
Type - Pset_WallCommon - IsExternal: no; Reference: Basic Wall:NLRS_21_WA_Naturoll 035_270x590x2600mm; ThermalTransmittance: 0.12963 kg/K/s3
Type - Pset_Wall Schedule Naturoll 035 LOD400 - rollen / pak: 2; Assembly Code: 21; Type Image: Raster image: Naturoll 035 .jpg (2); Model: Naturoll 035 is een onbeklede glaswoldeken met ECOSE® Technology; Manufacturer: Knauf Insulation B.V.; URL: www.knaufinsulation.nl; Description: Naturoll 035 - 270mm; phone: +31(0)162-421245; email: customerservice.nl@knaufinsulation.com; product URL: https://www.knaufinsulation.nl/producten-van-knauf-insulation/naturoll-035; warmteweerstand: 7.7; NLRS_C_Code_Brandklasse: A1; warmtegeleidingscoëfficiënt: 0.035; kortstondige waterabsorptie: WS; langdurige waterabsorptie: WL(P); waterdamptransmissie / waterdampdiffusie weerstandsfactor: MU1; luchtstroomweerstand: Afr5; DoP nummer (Declaration of performance): G4220LPCPR; NLRS_C_content_creator: Knauf Insulation; NLRS_C_content_versie: V1.0; diktebereik: 20 - 370; diktetolerantie: T2; pak (m2): 3.07; pakken / pallet: 24; pallet (m2): 73.63
Classification: 21 Buitenwanden (Uniformat)
Pset_WallCommon - LoadBearing: no; IsExternal: yes; ExtendToStructure: no
Pset_Wall Schedule Naturoll 035 LOD400 - Type: Basic Wall: NLRS_21_WA_Naturoll 035_270x590x2600mm
Name (Basic Wall:NLRS_21_WA_Naturoll 035_270x590x2600mm:...)
35495
35497

# IfcWallStandardCase: Basic Wall:NLRS_21_WA_Naturoll 035_90x380x7600mm (2)
In: Begane grond
Type - PredefinedType: STANDARD; Material: Knauf Insulation_Ecose® glaswol_naturoll 035 90 mm
Type - Pset_ElementShading - Roughness: 304.8 mm
Type - Pset_ManufacturerTypeInformation - Manufacturer: Knauf Insulation B.V.
Type - Pset_ProductRequirements - Category: Walls
Type - Pset_QuantityTakeOff - Reference: Basic Wall:NLRS_21_WA_Naturoll 035_90x380x7600mm
Type - Pset_ReinforcementBarPitchOfWall - Description: Naturoll 035 - 90mm; Reference: Basic Wall:NLRS_21_WA_Naturoll 035_90x380x7600mm
Type - Pset_WallCommon - IsExternal: no; Reference: Basic Wall:NLRS_21_WA_Naturoll 035_90x380x7600mm; ThermalTransmittance: 0.388889 kg/K/s3
Type - Pset_Wall Schedule Naturoll 035 LOD400 - rollen / pak: 3; Assembly Code: 21; Type Image: Raster image: Naturoll 035 .jpg (2); Model: Naturoll 035 is een onbeklede glaswoldeken met ECOSE® Technology; Manufacturer: Knauf Insulation B.V.; URL: www.knaufinsulation.nl; Description: Naturoll 035 - 90mm; phone: +31(0)162-421245; email: customerservice.nl@knaufinsulation.com; product URL: https://www.knaufinsulation.nl/producten-van-knauf-insulation/naturoll-035; warmteweerstand: 2.55; NLRS_C_Code_Brandklasse: A1; warmtegeleidingscoëfficiënt: 0.035; kortstondige waterabsorptie: WS; langdurige waterabsorptie: WL(P); waterdamptransmissie / waterdampdiffusie weerstandsfactor: MU1; luchtstroomweerstand: Afr5; DoP nummer (Declaration of performance): G4220LPCPR; NLRS_C_content_creator: Knauf Insulation; NLRS_C_content_versie: V1.0; diktebereik: 20 - 370; diktetolerantie: T2; pak (m2): 8.66; pakken / pallet: 24; pallet (m2): 207.94
Classification: 21 Buitenwanden (Uniformat)
Pset_WallCommon - LoadBearing: no; IsExternal: yes; ExtendToStructure: no
Pset_Wall Schedule Naturoll 035 LOD400 - Type: Basic Wall: NLRS_21_WA_Naturoll 035_90x380x7600mm
Name (Basic Wall:NLRS_21_WA_Naturoll 035_90x380x7600mm:...)
34411
34652

# IfcWallStandardCase: Basic Wall:NLRS_21_WA_Naturoll 035_90x580x7600mm (2)
In: Begane grond
Type - PredefinedType: STANDARD; Material: Knauf Insulation_Ecose® glaswol_naturoll 035 90 mm
Type - Pset_ElementShading - Roughness: 304.8 mm
Type - Pset_ManufacturerTypeInformation - Manufacturer: Knauf Insulation B.V.
Type - Pset_ProductRequirements - Category: Walls
Type - Pset_QuantityTakeOff - Reference: Basic Wall:NLRS_21_WA_Naturoll 035_90x580x7600mm
Type - Pset_ReinforcementBarPitchOfWall - Description: Naturoll 035 - 90mm; Reference: Basic Wall:NLRS_21_WA_Naturoll 035_90x580x7600mm
Type - Pset_WallCommon - IsExternal: no; Reference: Basic Wall:NLRS_21_WA_Naturoll 035_90x580x7600mm; ThermalTransmittance: 0.388889 kg/K/s3
Type - Pset_Wall Schedule Naturoll 035 LOD400 - rollen / pak: 2; Assembly Code: 21; Type Image: Raster image: Naturoll 035 .jpg (2); Model: Naturoll 035 is een onbeklede glaswoldeken met ECOSE® Technology; Manufacturer: Knauf Insulation B.V.; URL: www.knaufinsulation.nl; Description: Naturoll 035 - 90mm; phone: +31(0)162-421245; email: customerservice.nl@knaufinsulation.com; product URL: https://www.knaufinsulation.nl/producten-van-knauf-insulation/naturoll-035; warmteweerstand: 2.55; NLRS_C_Code_Brandklasse: A1; warmtegeleidingscoëfficiënt: 0.035; kortstondige waterabsorptie: WS; langdurige waterabsorptie: WL(P); waterdamptransmissie / waterdampdiffusie weerstandsfactor: MU1; luchtstroomweerstand: Afr5; DoP nummer (Declaration of performance): G4220LPCPR; NLRS_C_content_creator: Knauf Insulation; NLRS_C_content_versie: V1.0; diktebereik: 20 - 370; diktetolerantie: T2; pak (m2): 8.82; pakken / pallet: 24; pallet (m2): 211.58
Classification: 21 Buitenwanden (Uniformat)
Pset_WallCommon - LoadBearing: no; IsExternal: yes; ExtendToStructure: no
Pset_Wall Schedule Naturoll 035 LOD400 - Type: Basic Wall: NLRS_21_WA_Naturoll 035_90x580x7600mm
Name (Basic Wall:NLRS_21_WA_Naturoll 035_90x580x7600mm:...)
34916
34918
